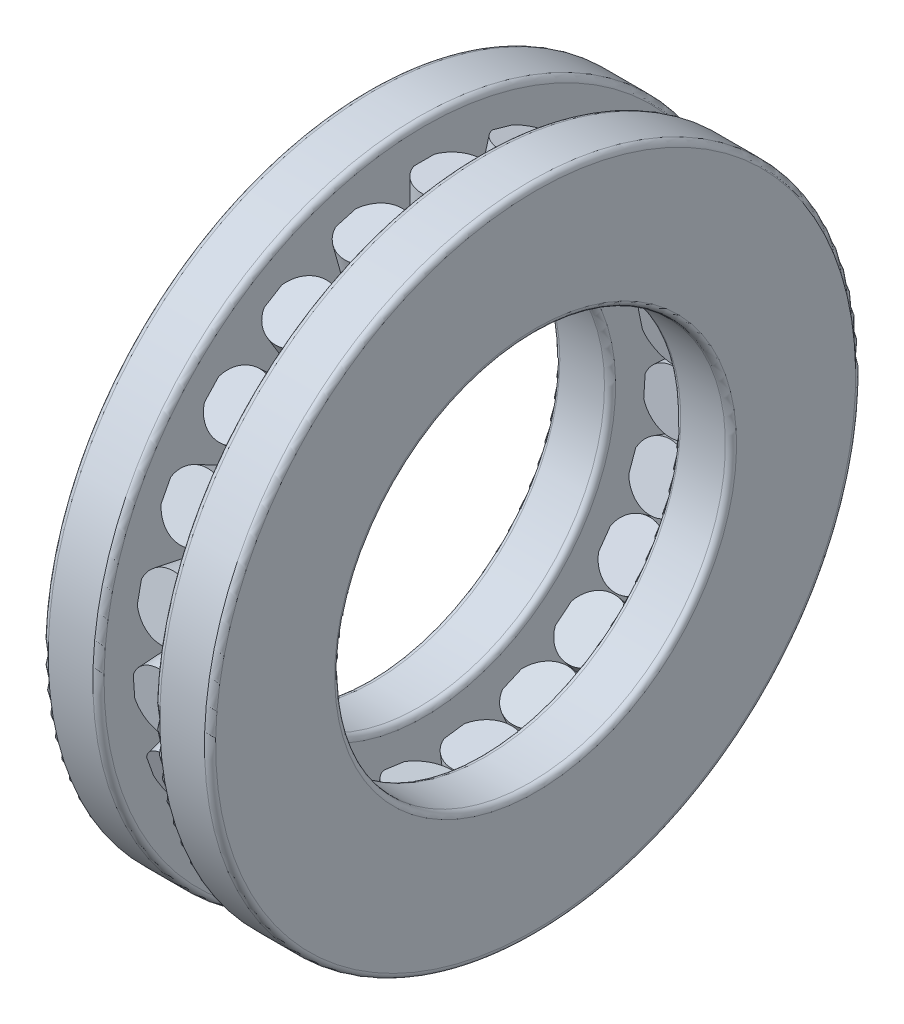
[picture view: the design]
ISO-10303-21;
HEADER;
FILE_DESCRIPTION(('STEP AP214'),'2;1');
FILE_NAME('part.step','',(''),(''),'','','');
FILE_SCHEMA(('AUTOMOTIVE_DESIGN { 1 0 10303 214 1 1 1 1 }'));
ENDSEC;
DATA;
#1=APPLICATION_CONTEXT('core data for automotive mechanical design processes');
#2=APPLICATION_PROTOCOL_DEFINITION('international standard','automotive_design',2000,#1);
#3=PRODUCT_CONTEXT('',#1,'mechanical');
#4=PRODUCT('Part','Part','',(#3));
#5=PRODUCT_RELATED_PRODUCT_CATEGORY('part','',(#4));
#6=PRODUCT_DEFINITION_FORMATION('','',#4);
#7=PRODUCT_DEFINITION_CONTEXT('part definition',#1,'design');
#8=PRODUCT_DEFINITION('design','',#6,#7);
#9=PRODUCT_DEFINITION_SHAPE('','',#8);
#10=(LENGTH_UNIT() NAMED_UNIT(*) SI_UNIT(.MILLI.,.METRE.));
#11=(NAMED_UNIT(*) PLANE_ANGLE_UNIT() SI_UNIT($,.RADIAN.));
#12=(NAMED_UNIT(*) SI_UNIT($,.STERADIAN.) SOLID_ANGLE_UNIT());
#13=UNCERTAINTY_MEASURE_WITH_UNIT(LENGTH_MEASURE(1.E-05),#10,'distance_accuracy_value','');
#14=(GEOMETRIC_REPRESENTATION_CONTEXT(3) GLOBAL_UNCERTAINTY_ASSIGNED_CONTEXT((#13)) GLOBAL_UNIT_ASSIGNED_CONTEXT((#10,
#11,#12)) REPRESENTATION_CONTEXT('',''));
#15=CARTESIAN_POINT('',(0.,0.,0.));
#16=DIRECTION('',(0.,0.,1.));
#17=DIRECTION('',(1.,0.,0.));
#18=AXIS2_PLACEMENT_3D('',#15,#16,#17);
#19=CARTESIAN_POINT('',(0.,-17.5,0.));
#20=DIRECTION('',(1.,0.,0.));
#21=DIRECTION('',(0.,1.,0.));
#22=AXIS2_PLACEMENT_3D('',#19,#20,#21);
#23=PLANE('',#22);
#24=CARTESIAN_POINT('',(0.,0.,0.));
#25=DIRECTION('',(1.,0.,0.));
#26=DIRECTION('',(0.,1.,0.));
#27=AXIS2_PLACEMENT_3D('',#24,#25,#26);
#28=CIRCLE('',#27,10.3);
#29=CARTESIAN_POINT('',(0.,10.3,0.));
#30=VERTEX_POINT('',#29);
#31=EDGE_CURVE('E644',#30,#30,#28,.F.);
#32=ORIENTED_EDGE('',*,*,#31,.T.);
#33=EDGE_LOOP('',(#32));
#34=FACE_BOUND('',#33,.T.);
#35=CARTESIAN_POINT('',(0.,0.,0.));
#36=DIRECTION('',(1.,0.,0.));
#37=DIRECTION('',(0.,1.,0.));
#38=AXIS2_PLACEMENT_3D('',#35,#36,#37);
#39=CIRCLE('',#38,17.2);
#40=CARTESIAN_POINT('',(0.,17.2,0.));
#41=VERTEX_POINT('',#40);
#42=EDGE_CURVE('E641',#41,#41,#39,.T.);
#43=ORIENTED_EDGE('',*,*,#42,.T.);
#44=EDGE_LOOP('',(#43));
#45=FACE_BOUND('',#44,.T.);
#46=DIRECTION('',(0.,1.,0.));
#47=VECTOR('',#46,1.);
#48=CARTESIAN_POINT('',(0.,16.5461402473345,0.556776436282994));
#49=LINE('',#48,#47);
#50=CARTESIAN_POINT('',(0.,11.875,0.556776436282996));
#51=VERTEX_POINT('',#50);
#52=CARTESIAN_POINT('',(0.,15.625,0.556776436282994));
#53=VERTEX_POINT('',#52);
#54=EDGE_CURVE('E1057',#51,#53,#49,.T.);
#55=ORIENTED_EDGE('',*,*,#54,.T.);
#56=DIRECTION('',(0.,0.,-1.));
#57=VECTOR('',#56,1.);
#58=CARTESIAN_POINT('',(0.,15.625,0.));
#59=LINE('',#58,#57);
#60=CARTESIAN_POINT('',(0.,15.625,-0.556776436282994));
#61=VERTEX_POINT('',#60);
#62=EDGE_CURVE('E1076',#53,#61,#59,.T.);
#63=ORIENTED_EDGE('',*,*,#62,.T.);
#64=DIRECTION('',(0.,1.,0.));
#65=VECTOR('',#64,1.);
#66=CARTESIAN_POINT('',(0.,16.5461402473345,-0.556776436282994));
#67=LINE('',#66,#65);
#68=CARTESIAN_POINT('',(0.,11.875,-0.556776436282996));
#69=VERTEX_POINT('',#68);
#70=EDGE_CURVE('E1073',#61,#69,#67,.F.);
#71=ORIENTED_EDGE('',*,*,#70,.T.);
#72=DIRECTION('',(0.,0.,1.));
#73=VECTOR('',#72,1.);
#74=CARTESIAN_POINT('',(0.,11.875,0.));
#75=LINE('',#74,#73);
#76=EDGE_CURVE('E1070',#69,#51,#75,.T.);
#77=ORIENTED_EDGE('',*,*,#76,.T.);
#78=EDGE_LOOP('',(#55,#63,#71,#77));
#79=FACE_BOUND('',#78,.T.);
#80=DIRECTION('',(0.,0.962917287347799,0.269796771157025));
#81=VECTOR('',#80,1.);
#82=CARTESIAN_POINT('',(0.,15.7823479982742,5.00022486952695));
#83=LINE('',#82,#81);
#84=CARTESIAN_POINT('',(0.,11.2844263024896,3.73996631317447));
#85=VERTEX_POINT('',#84);
#86=CARTESIAN_POINT('',(0.,14.8953661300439,4.75170420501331));
#87=VERTEX_POINT('',#86);
#88=EDGE_CURVE('E1750',#85,#87,#83,.T.);
#89=ORIENTED_EDGE('',*,*,#88,.T.);
#90=DIRECTION('',(0.,0.269796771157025,-0.962917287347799));
#91=VECTOR('',#90,1.);
#92=CARTESIAN_POINT('',(0.,13.7717524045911,8.76193411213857));
#93=LINE('',#92,#91);
#94=CARTESIAN_POINT('',(0.,15.1957990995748,3.67944489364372));
#95=VERTEX_POINT('',#94);
#96=EDGE_CURVE('E1756',#87,#95,#93,.T.);
#97=ORIENTED_EDGE('',*,*,#96,.T.);
#98=DIRECTION('',(0.,0.962917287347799,0.269796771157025));
#99=VECTOR('',#98,1.);
#100=CARTESIAN_POINT('',(0.,16.0827809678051,3.92796555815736));
#101=LINE('',#100,#99);
#102=CARTESIAN_POINT('',(0.,11.5848592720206,2.66770700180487));
#103=VERTEX_POINT('',#102);
#104=EDGE_CURVE('E1753',#95,#103,#101,.F.);
#105=ORIENTED_EDGE('',*,*,#104,.T.);
#106=DIRECTION('',(0.,-0.269796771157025,0.962917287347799));
#107=VECTOR('',#106,1.);
#108=CARTESIAN_POINT('',(0.,10.1608125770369,7.75019622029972));
#109=LINE('',#108,#107);
#110=EDGE_CURVE('E1747',#103,#85,#109,.T.);
#111=ORIENTED_EDGE('',*,*,#110,.T.);
#112=EDGE_LOOP('',(#89,#97,#105,#111));
#113=FACE_BOUND('',#112,.T.);
#114=DIRECTION('',(0.,0.854419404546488,0.519583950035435));
#115=VECTOR('',#114,1.);
#116=CARTESIAN_POINT('',(0.,13.8480511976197,9.0728294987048));
#117=LINE('',#116,#115);
#118=CARTESIAN_POINT('',(0.,9.85693832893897,6.64577999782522));
#119=VERTEX_POINT('',#118);
#120=CARTESIAN_POINT('',(0.,13.0610110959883,8.59421981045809));
#121=VERTEX_POINT('',#120);
#122=EDGE_CURVE('E1730',#119,#121,#117,.T.);
#123=ORIENTED_EDGE('',*,*,#122,.T.);
#124=DIRECTION('',(0.,0.519583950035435,-0.854419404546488));
#125=VECTOR('',#124,1.);
#126=CARTESIAN_POINT('',(0.,8.62587227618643,15.8874948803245));
#127=LINE('',#126,#125);
#128=CARTESIAN_POINT('',(0.,13.6395952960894,7.64277862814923));
#129=VERTEX_POINT('',#128);
#130=EDGE_CURVE('E1736',#121,#129,#127,.T.);
#131=ORIENTED_EDGE('',*,*,#130,.T.);
#132=DIRECTION('',(0.,0.854419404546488,0.519583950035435));
#133=VECTOR('',#132,1.);
#134=CARTESIAN_POINT('',(0.,14.4266353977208,8.12138831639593));
#135=LINE('',#134,#133);
#136=CARTESIAN_POINT('',(0.,10.4355225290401,5.69433881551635));
#137=VERTEX_POINT('',#136);
#138=EDGE_CURVE('E1733',#129,#137,#135,.F.);
#139=ORIENTED_EDGE('',*,*,#138,.T.);
#140=DIRECTION('',(0.,-0.519583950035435,0.854419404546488));
#141=VECTOR('',#140,1.);
#142=CARTESIAN_POINT('',(0.,5.42179950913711,13.9390550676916));
#143=LINE('',#142,#141);
#144=EDGE_CURVE('E1727',#137,#119,#143,.T.);
#145=ORIENTED_EDGE('',*,*,#144,.T.);
#146=EDGE_LOOP('',(#123,#131,#139,#145));
#147=FACE_BOUND('',#146,.T.);
#148=DIRECTION('',(0.,0.682553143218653,0.730835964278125));
#149=VECTOR('',#148,1.);
#150=CARTESIAN_POINT('',(0.,10.8867077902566,12.4725438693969));
#151=LINE('',#150,#149);
#152=CARTESIAN_POINT('',(0.,7.69840633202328,9.05870658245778));
#153=VERTEX_POINT('',#152);
#154=CARTESIAN_POINT('',(0.,10.2579806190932,11.7993414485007));
#155=VERTEX_POINT('',#154);
#156=EDGE_CURVE('E1710',#153,#155,#151,.T.);
#157=ORIENTED_EDGE('',*,*,#156,.T.);
#158=DIRECTION('',(0.,0.730835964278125,-0.682553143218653));
#159=VECTOR('',#158,1.);
#160=CARTESIAN_POINT('',(0.,1.31777174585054,20.1489136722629));
#161=LINE('',#160,#159);
#162=CARTESIAN_POINT('',(0.,11.0718051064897,11.0392824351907));
#163=VERTEX_POINT('',#162);
#164=EDGE_CURVE('E1716',#155,#163,#161,.T.);
#165=ORIENTED_EDGE('',*,*,#164,.T.);
#166=DIRECTION('',(0.,0.682553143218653,0.730835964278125));
#167=VECTOR('',#166,1.);
#168=CARTESIAN_POINT('',(0.,11.7005322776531,11.7124848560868));
#169=LINE('',#168,#167);
#170=CARTESIAN_POINT('',(0.,8.51223081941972,8.2986475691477));
#171=VERTEX_POINT('',#170);
#172=EDGE_CURVE('E1713',#163,#171,#169,.F.);
#173=ORIENTED_EDGE('',*,*,#172,.T.);
#174=DIRECTION('',(0.,-0.730835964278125,0.682553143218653));
#175=VECTOR('',#174,1.);
#176=CARTESIAN_POINT('',(0.,-1.2418025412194,17.40827880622));
#177=LINE('',#176,#175);
#178=EDGE_CURVE('E1707',#171,#153,#177,.T.);
#179=ORIENTED_EDGE('',*,*,#178,.T.);
#180=EDGE_LOOP('',(#157,#165,#173,#179));
#181=FACE_BOUND('',#180,.T.);
#182=DIRECTION('',(0.,0.46006503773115,0.887885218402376));
#183=VECTOR('',#182,1.);
#184=CARTESIAN_POINT('',(0.,7.11794706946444,14.9472267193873));
#185=LINE('',#184,#183);
#186=CARTESIAN_POINT('',(0.,4.96891875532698,10.7997903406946));
#187=VERTEX_POINT('',#186);
#188=CARTESIAN_POINT('',(0.,6.69416264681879,14.1293599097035));
#189=VERTEX_POINT('',#188);
#190=EDGE_CURVE('E1690',#187,#189,#185,.T.);
#191=ORIENTED_EDGE('',*,*,#190,.T.);
#192=DIRECTION('',(0.,0.887885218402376,-0.46006503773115));
#193=VECTOR('',#192,1.);
#194=CARTESIAN_POINT('',(0.,-6.60743660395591,21.0216931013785));
#195=LINE('',#194,#193);
#196=CARTESIAN_POINT('',(0.,7.68286978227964,13.6170531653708));
#197=VERTEX_POINT('',#196);
#198=EDGE_CURVE('E1696',#189,#197,#195,.T.);
#199=ORIENTED_EDGE('',*,*,#198,.T.);
#200=DIRECTION('',(0.,0.46006503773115,0.887885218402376));
#201=VECTOR('',#200,1.);
#202=CARTESIAN_POINT('',(0.,8.10665420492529,14.4349199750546));
#203=LINE('',#202,#201);
#204=CARTESIAN_POINT('',(0.,5.95762589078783,10.2874835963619));
#205=VERTEX_POINT('',#204);
#206=EDGE_CURVE('E1693',#197,#205,#203,.F.);
#207=ORIENTED_EDGE('',*,*,#206,.T.);
#208=DIRECTION('',(0.,-0.887885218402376,0.46006503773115));
#209=VECTOR('',#208,1.);
#210=CARTESIAN_POINT('',(0.,-8.33268049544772,17.6921235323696));
#211=LINE('',#210,#209);
#212=EDGE_CURVE('E1687',#205,#187,#211,.T.);
#213=ORIENTED_EDGE('',*,*,#212,.T.);
#214=EDGE_LOOP('',(#191,#199,#207,#213));
#215=FACE_BOUND('',#214,.T.);
#216=DIRECTION('',(0.,0.203456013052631,0.979084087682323));
#217=VECTOR('',#216,1.);
#218=CARTESIAN_POINT('',(0.,2.82128077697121,16.3133421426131));
#219=LINE('',#218,#217);
#220=CARTESIAN_POINT('',(0.,1.87090920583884,11.7399030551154));
#221=VERTEX_POINT('',#220);
#222=CARTESIAN_POINT('',(0.,2.63386925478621,15.4114683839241));
#223=VERTEX_POINT('',#222);
#224=EDGE_CURVE('E1670',#221,#223,#219,.T.);
#225=ORIENTED_EDGE('',*,*,#224,.T.);
#226=DIRECTION('',(0.,0.979084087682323,-0.203456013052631));
#227=VECTOR('',#226,1.);
#228=CARTESIAN_POINT('',(0.,-13.5965986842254,18.7841984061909));
#229=LINE('',#228,#227);
#230=CARTESIAN_POINT('',(0.,3.72413115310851,15.1849093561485));
#231=VERTEX_POINT('',#230);
#232=EDGE_CURVE('E1676',#223,#231,#229,.T.);
#233=ORIENTED_EDGE('',*,*,#232,.T.);
#234=DIRECTION('',(0.,0.203456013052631,0.979084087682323));
#235=VECTOR('',#234,1.);
#236=CARTESIAN_POINT('',(0.,3.91154267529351,16.0867831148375));
#237=LINE('',#236,#235);
#238=CARTESIAN_POINT('',(0.,2.96117110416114,11.5133440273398));
#239=VERTEX_POINT('',#238);
#240=EDGE_CURVE('E1673',#231,#239,#237,.F.);
#241=ORIENTED_EDGE('',*,*,#240,.T.);
#242=DIRECTION('',(0.,-0.979084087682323,0.203456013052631));
#243=VECTOR('',#242,1.);
#244=CARTESIAN_POINT('',(0.,-14.3595587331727,15.1126330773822));
#245=LINE('',#244,#243);
#246=EDGE_CURVE('E1667',#239,#221,#245,.T.);
#247=ORIENTED_EDGE('',*,*,#246,.T.);
#248=EDGE_LOOP('',(#225,#233,#241,#247));
#249=FACE_BOUND('',#248,.T.);
#250=DIRECTION('',(0.,-0.0682424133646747,0.997668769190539));
#251=VECTOR('',#250,1.);
#252=CARTESIAN_POINT('',(0.,-1.68462700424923,16.4695716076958));
#253=LINE('',#252,#251);
#254=CARTESIAN_POINT('',(0.,-1.36585712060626,11.8093208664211));
#255=VERTEX_POINT('',#254);
#256=CARTESIAN_POINT('',(0.,-1.62176617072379,15.5505787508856));
#257=VERTEX_POINT('',#256);
#258=EDGE_CURVE('E1650',#255,#257,#253,.T.);
#259=ORIENTED_EDGE('',*,*,#258,.T.);
#260=DIRECTION('',(0.,0.997668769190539,0.0682424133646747));
#261=VECTOR('',#260,1.);
#262=CARTESIAN_POINT('',(0.,-18.4847897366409,14.3971163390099));
#263=LINE('',#262,#261);
#264=CARTESIAN_POINT('',(0.,-0.510809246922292,15.6265702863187));
#265=VERTEX_POINT('',#264);
#266=EDGE_CURVE('E1656',#257,#265,#263,.T.);
#267=ORIENTED_EDGE('',*,*,#266,.T.);
#268=DIRECTION('',(0.,-0.0682424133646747,0.997668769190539));
#269=VECTOR('',#268,1.);
#270=CARTESIAN_POINT('',(0.,-0.573670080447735,16.5455631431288));
#271=LINE('',#270,#269);
#272=CARTESIAN_POINT('',(0.,-0.254900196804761,11.8853124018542));
#273=VERTEX_POINT('',#272);
#274=EDGE_CURVE('E1653',#265,#273,#271,.F.);
#275=ORIENTED_EDGE('',*,*,#274,.T.);
#276=DIRECTION('',(0.,-0.997668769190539,-0.0682424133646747));
#277=VECTOR('',#276,1.);
#278=CARTESIAN_POINT('',(0.,-18.2288806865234,10.6558584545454));
#279=LINE('',#278,#277);
#280=EDGE_CURVE('E1647',#273,#255,#279,.T.);
#281=ORIENTED_EDGE('',*,*,#280,.T.);
#282=EDGE_LOOP('',(#259,#267,#275,#281));
#283=FACE_BOUND('',#282,.T.);
#284=DIRECTION('',(0.,-0.33487961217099,0.942260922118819));
#285=VECTOR('',#284,1.);
#286=CARTESIAN_POINT('',(0.,-6.06559370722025,15.4043282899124));
#287=LINE('',#286,#285);
#288=CARTESIAN_POINT('',(0.,-4.50132407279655,11.0028953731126));
#289=VERTEX_POINT('',#288);
#290=CARTESIAN_POINT('',(0.,-5.75712261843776,14.5363738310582));
#291=VERTEX_POINT('',#290);
#292=EDGE_CURVE('E1630',#289,#291,#287,.T.);
#293=ORIENTED_EDGE('',*,*,#292,.T.);
#294=DIRECTION('',(0.,0.942260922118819,0.33487961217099));
#295=VECTOR('',#294,1.);
#296=CARTESIAN_POINT('',(0.,-20.7699677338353,9.20080739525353));
#297=LINE('',#296,#295);
#298=CARTESIAN_POINT('',(0.,-4.70786526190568,14.9092799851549));
#299=VERTEX_POINT('',#298);
#300=EDGE_CURVE('E1636',#291,#299,#297,.T.);
#301=ORIENTED_EDGE('',*,*,#300,.T.);
#302=DIRECTION('',(0.,-0.33487961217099,0.942260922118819));
#303=VECTOR('',#302,1.);
#304=CARTESIAN_POINT('',(0.,-5.01633635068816,15.7772344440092));
#305=LINE('',#304,#303);
#306=CARTESIAN_POINT('',(0.,-3.45206671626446,11.3758015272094));
#307=VERTEX_POINT('',#306);
#308=EDGE_CURVE('E1633',#299,#307,#305,.F.);
#309=ORIENTED_EDGE('',*,*,#308,.T.);
#310=DIRECTION('',(0.,-0.942260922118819,-0.33487961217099));
#311=VECTOR('',#310,1.);
#312=CARTESIAN_POINT('',(0.,-19.5141691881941,5.66732893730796));
#313=LINE('',#312,#311);
#314=EDGE_CURVE('E1627',#307,#289,#313,.T.);
#315=ORIENTED_EDGE('',*,*,#314,.T.);
#316=EDGE_LOOP('',(#293,#301,#309,#315));
#317=FACE_BOUND('',#316,.T.);
#318=DIRECTION('',(0.,-0.576680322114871,0.816969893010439));
#319=VECTOR('',#318,1.);
#320=CARTESIAN_POINT('',(0.,-9.99670307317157,13.196616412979));
#321=LINE('',#320,#319);
#322=CARTESIAN_POINT('',(0.,-7.30294841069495,9.38043546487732));
#323=VERTEX_POINT('',#322);
#324=CARTESIAN_POINT('',(0.,-9.46549961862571,12.4440725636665));
#325=VERTEX_POINT('',#324);
#326=EDGE_CURVE('E1610',#323,#325,#321,.T.);
#327=ORIENTED_EDGE('',*,*,#326,.T.);
#328=DIRECTION('',(0.,0.816969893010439,0.576680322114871));
#329=VECTOR('',#328,1.);
#330=CARTESIAN_POINT('',(0.,-20.6908266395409,4.5203715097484));
#331=LINE('',#330,#329);
#332=CARTESIAN_POINT('',(0.,-8.55576044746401,13.0862365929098));
#333=VERTEX_POINT('',#332);
#334=EDGE_CURVE('E1616',#325,#333,#331,.T.);
#335=ORIENTED_EDGE('',*,*,#334,.T.);
#336=DIRECTION('',(0.,-0.576680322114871,0.816969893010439));
#337=VECTOR('',#336,1.);
#338=CARTESIAN_POINT('',(0.,-9.08696390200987,13.8387804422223));
#339=LINE('',#338,#337);
#340=CARTESIAN_POINT('',(0.,-6.39320923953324,10.0225994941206));
#341=VERTEX_POINT('',#340);
#342=EDGE_CURVE('E1613',#333,#341,#339,.F.);
#343=ORIENTED_EDGE('',*,*,#342,.T.);
#344=DIRECTION('',(0.,-0.816969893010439,-0.576680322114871));
#345=VECTOR('',#344,1.);
#346=CARTESIAN_POINT('',(0.,-18.5282754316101,1.45673441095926));
#347=LINE('',#346,#345);
#348=EDGE_CURVE('E1607',#341,#323,#347,.T.);
#349=ORIENTED_EDGE('',*,*,#348,.T.);
#350=EDGE_LOOP('',(#327,#335,#343,#349));
#351=FACE_BOUND('',#350,.T.);
#352=DIRECTION('',(0.,-0.775711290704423,0.631087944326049));
#353=VECTOR('',#352,1.);
#354=CARTESIAN_POINT('',(0.,-13.1864027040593,10.010171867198));
#355=LINE('',#354,#353);
#356=CARTESIAN_POINT('',(0.,-9.56294647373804,7.06227157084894));
#357=VERTEX_POINT('',#356);
#358=CARTESIAN_POINT('',(0.,-12.4718638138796,9.42885136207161));
#359=VERTEX_POINT('',#358);
#360=EDGE_CURVE('E1590',#357,#359,#355,.T.);
#361=ORIENTED_EDGE('',*,*,#360,.T.);
#362=DIRECTION('',(0.,0.631087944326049,0.775711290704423));
#363=VECTOR('',#362,1.);
#364=CARTESIAN_POINT('',(0.,-19.090248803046,1.2937633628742));
#365=LINE('',#364,#363);
#366=CARTESIAN_POINT('',(0.,-11.7691140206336,10.2926468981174));
#367=VERTEX_POINT('',#366);
#368=EDGE_CURVE('E1596',#359,#367,#365,.T.);
#369=ORIENTED_EDGE('',*,*,#368,.T.);
#370=DIRECTION('',(0.,-0.775711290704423,0.631087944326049));
#371=VECTOR('',#370,1.);
#372=CARTESIAN_POINT('',(0.,-12.4836529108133,10.8739674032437));
#373=LINE('',#372,#371);
#374=CARTESIAN_POINT('',(0.,-8.86019668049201,7.92606710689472));
#375=VERTEX_POINT('',#374);
#376=EDGE_CURVE('E1593',#367,#375,#373,.F.);
#377=ORIENTED_EDGE('',*,*,#376,.T.);
#378=DIRECTION('',(0.,-0.631087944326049,-0.775711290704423));
#379=VECTOR('',#378,1.);
#380=CARTESIAN_POINT('',(0.,-16.1813314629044,-1.07281642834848));
#381=LINE('',#380,#379);
#382=EDGE_CURVE('E1587',#375,#357,#381,.T.);
#383=ORIENTED_EDGE('',*,*,#382,.T.);
#384=EDGE_LOOP('',(#361,#369,#377,#383));
#385=FACE_BOUND('',#384,.T.);
#386=DIRECTION('',(0.,-0.917211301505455,0.398401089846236));
#387=VECTOR('',#386,1.);
#388=CARTESIAN_POINT('',(0.,-15.3981271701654,6.08131866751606));
#389=LINE('',#388,#387);
#390=CARTESIAN_POINT('',(0.,-11.1137045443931,4.22033130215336));
#391=VERTEX_POINT('',#390);
#392=CARTESIAN_POINT('',(0.,-14.5532469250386,5.71433538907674));
#393=VERTEX_POINT('',#392);
#394=EDGE_CURVE('E1570',#391,#393,#389,.T.);
#395=ORIENTED_EDGE('',*,*,#394,.T.);
#396=DIRECTION('',(0.,0.398401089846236,0.917211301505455));
#397=VECTOR('',#396,1.);
#398=CARTESIAN_POINT('',(0.,-17.1090865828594,-0.169797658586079));
#399=LINE('',#398,#397);
#400=CARTESIAN_POINT('',(0.,-14.1096062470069,6.73569866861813));
#401=VERTEX_POINT('',#400);
#402=EDGE_CURVE('E1576',#393,#401,#399,.T.);
#403=ORIENTED_EDGE('',*,*,#402,.T.);
#404=DIRECTION('',(0.,-0.917211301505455,0.398401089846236));
#405=VECTOR('',#404,1.);
#406=CARTESIAN_POINT('',(0.,-14.9544864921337,7.10268194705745));
#407=LINE('',#406,#405);
#408=CARTESIAN_POINT('',(0.,-10.6700638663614,5.24169458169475));
#409=VERTEX_POINT('',#408);
#410=EDGE_CURVE('E1573',#401,#409,#407,.F.);
#411=ORIENTED_EDGE('',*,*,#410,.T.);
#412=DIRECTION('',(0.,-0.398401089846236,-0.917211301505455));
#413=VECTOR('',#412,1.);
#414=CARTESIAN_POINT('',(0.,-13.669544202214,-1.66380174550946));
#415=LINE('',#414,#413);
#416=EDGE_CURVE('E1567',#409,#391,#415,.T.);
#417=ORIENTED_EDGE('',*,*,#416,.T.);
#418=EDGE_LOOP('',(#395,#403,#411,#417));
#419=FACE_BOUND('',#418,.T.);
#420=DIRECTION('',(0.,-0.990685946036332,0.13616664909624));
#421=VECTOR('',#420,1.);
#422=CARTESIAN_POINT('',(0.,-16.4678429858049,1.70144188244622));
#423=LINE('',#422,#421);
#424=CARTESIAN_POINT('',(0.,-11.8402099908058,1.06538836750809));
#425=VERTEX_POINT('',#424);
#426=CARTESIAN_POINT('',(0.,-15.5552822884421,1.57601330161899));
#427=VERTEX_POINT('',#426);
#428=EDGE_CURVE('E1550',#425,#427,#423,.T.);
#429=ORIENTED_EDGE('',*,*,#428,.T.);
#430=DIRECTION('',(0.,0.13616664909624,0.990685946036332));
#431=VECTOR('',#430,1.);
#432=CARTESIAN_POINT('',(0.,-15.8039416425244,-0.233117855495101));
#433=LINE('',#432,#431);
#434=CARTESIAN_POINT('',(0.,-15.4036535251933,2.67919448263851));
#435=VERTEX_POINT('',#434);
#436=EDGE_CURVE('E1556',#427,#435,#433,.T.);
#437=ORIENTED_EDGE('',*,*,#436,.T.);
#438=DIRECTION('',(0.,-0.990685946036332,0.13616664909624));
#439=VECTOR('',#438,1.);
#440=CARTESIAN_POINT('',(0.,-16.316214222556,2.80462306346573));
#441=LINE('',#440,#439);
#442=CARTESIAN_POINT('',(0.,-11.688581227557,2.16856954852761));
#443=VERTEX_POINT('',#442);
#444=EDGE_CURVE('E1553',#435,#443,#441,.F.);
#445=ORIENTED_EDGE('',*,*,#444,.T.);
#446=DIRECTION('',(0.,-0.13616664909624,-0.990685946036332));
#447=VECTOR('',#446,1.);
#448=CARTESIAN_POINT('',(0.,-12.0888693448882,-0.743742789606));
#449=LINE('',#448,#447);
#450=EDGE_CURVE('E1547',#443,#425,#449,.T.);
#451=ORIENTED_EDGE('',*,*,#450,.T.);
#452=EDGE_LOOP('',(#429,#437,#445,#451));
#453=FACE_BOUND('',#452,.T.);
#454=DIRECTION('',(0.,-0.99068594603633,-0.136166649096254));
#455=VECTOR('',#454,1.);
#456=CARTESIAN_POINT('',(0.,-16.316214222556,-2.80462306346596));
#457=LINE('',#456,#455);
#458=CARTESIAN_POINT('',(0.,-11.688581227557,-2.16856954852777));
#459=VERTEX_POINT('',#458);
#460=CARTESIAN_POINT('',(0.,-15.4036535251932,-2.67919448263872));
#461=VERTEX_POINT('',#460);
#462=EDGE_CURVE('E1530',#459,#461,#457,.T.);
#463=ORIENTED_EDGE('',*,*,#462,.T.);
#464=DIRECTION('',(0.,-0.136166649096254,0.99068594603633));
#465=VECTOR('',#464,1.);
#466=CARTESIAN_POINT('',(0.,-15.8039416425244,0.23311785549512));
#467=LINE('',#466,#465);
#468=CARTESIAN_POINT('',(0.,-15.5552822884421,-1.57601330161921));
#469=VERTEX_POINT('',#468);
#470=EDGE_CURVE('E1536',#461,#469,#467,.T.);
#471=ORIENTED_EDGE('',*,*,#470,.T.);
#472=DIRECTION('',(0.,-0.99068594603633,-0.136166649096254));
#473=VECTOR('',#472,1.);
#474=CARTESIAN_POINT('',(0.,-16.4678429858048,-1.70144188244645));
#475=LINE('',#474,#473);
#476=CARTESIAN_POINT('',(0.,-11.8402099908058,-1.06538836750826));
#477=VERTEX_POINT('',#476);
#478=EDGE_CURVE('E1533',#469,#477,#475,.F.);
#479=ORIENTED_EDGE('',*,*,#478,.T.);
#480=DIRECTION('',(0.,0.136166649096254,-0.99068594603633));
#481=VECTOR('',#480,1.);
#482=CARTESIAN_POINT('',(0.,-12.0888693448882,0.743742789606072));
#483=LINE('',#482,#481);
#484=EDGE_CURVE('E1527',#477,#459,#483,.T.);
#485=ORIENTED_EDGE('',*,*,#484,.T.);
#486=EDGE_LOOP('',(#463,#471,#479,#485));
#487=FACE_BOUND('',#486,.T.);
#488=DIRECTION('',(0.,-0.91721130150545,-0.398401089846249));
#489=VECTOR('',#488,1.);
#490=CARTESIAN_POINT('',(0.,-14.9544864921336,-7.10268194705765));
#491=LINE('',#490,#489);
#492=CARTESIAN_POINT('',(0.,-10.6700638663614,-5.24169458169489));
#493=VERTEX_POINT('',#492);
#494=CARTESIAN_POINT('',(0.,-14.1096062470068,-6.73569866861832));
#495=VERTEX_POINT('',#494);
#496=EDGE_CURVE('E1510',#493,#495,#491,.T.);
#497=ORIENTED_EDGE('',*,*,#496,.T.);
#498=DIRECTION('',(0.,-0.398401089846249,0.91721130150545));
#499=VECTOR('',#498,1.);
#500=CARTESIAN_POINT('',(0.,-17.1090865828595,0.169797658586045));
#501=LINE('',#500,#499);
#502=CARTESIAN_POINT('',(0.,-14.5532469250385,-5.71433538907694));
#503=VERTEX_POINT('',#502);
#504=EDGE_CURVE('E1516',#495,#503,#501,.T.);
#505=ORIENTED_EDGE('',*,*,#504,.T.);
#506=DIRECTION('',(0.,-0.91721130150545,-0.398401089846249));
#507=VECTOR('',#506,1.);
#508=CARTESIAN_POINT('',(0.,-15.3981271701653,-6.08131866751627));
#509=LINE('',#508,#507);
#510=CARTESIAN_POINT('',(0.,-11.1137045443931,-4.22033130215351));
#511=VERTEX_POINT('',#510);
#512=EDGE_CURVE('E1513',#503,#511,#509,.F.);
#513=ORIENTED_EDGE('',*,*,#512,.T.);
#514=DIRECTION('',(0.,0.398401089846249,-0.91721130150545));
#515=VECTOR('',#514,1.);
#516=CARTESIAN_POINT('',(0.,-13.6695442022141,1.66380174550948));
#517=LINE('',#516,#515);
#518=EDGE_CURVE('E1507',#511,#493,#517,.T.);
#519=ORIENTED_EDGE('',*,*,#518,.T.);
#520=EDGE_LOOP('',(#497,#505,#513,#519));
#521=FACE_BOUND('',#520,.T.);
#522=DIRECTION('',(0.,-0.775711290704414,-0.631087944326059));
#523=VECTOR('',#522,1.);
#524=CARTESIAN_POINT('',(0.,-12.4836529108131,-10.8739674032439));
#525=LINE('',#524,#523);
#526=CARTESIAN_POINT('',(0.,-8.8601966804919,-7.92606710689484));
#527=VERTEX_POINT('',#526);
#528=CARTESIAN_POINT('',(0.,-11.7691140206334,-10.2926468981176));
#529=VERTEX_POINT('',#528);
#530=EDGE_CURVE('E1490',#527,#529,#525,.T.);
#531=ORIENTED_EDGE('',*,*,#530,.T.);
#532=DIRECTION('',(0.,-0.631087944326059,0.775711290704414));
#533=VECTOR('',#532,1.);
#534=CARTESIAN_POINT('',(0.,-19.0902488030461,-1.29376336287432));
#535=LINE('',#534,#533);
#536=CARTESIAN_POINT('',(0.,-12.4718638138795,-9.42885136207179));
#537=VERTEX_POINT('',#536);
#538=EDGE_CURVE('E1496',#529,#537,#535,.T.);
#539=ORIENTED_EDGE('',*,*,#538,.T.);
#540=DIRECTION('',(0.,-0.775711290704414,-0.631087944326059));
#541=VECTOR('',#540,1.);
#542=CARTESIAN_POINT('',(0.,-13.1864027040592,-10.0101718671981));
#543=LINE('',#542,#541);
#544=CARTESIAN_POINT('',(0.,-9.56294647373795,-7.06227157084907));
#545=VERTEX_POINT('',#544);
#546=EDGE_CURVE('E1493',#537,#545,#543,.F.);
#547=ORIENTED_EDGE('',*,*,#546,.T.);
#548=DIRECTION('',(0.,0.631087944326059,-0.775711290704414));
#549=VECTOR('',#548,1.);
#550=CARTESIAN_POINT('',(0.,-16.1813314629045,1.0728164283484));
#551=LINE('',#550,#549);
#552=EDGE_CURVE('E1487',#545,#527,#551,.T.);
#553=ORIENTED_EDGE('',*,*,#552,.T.);
#554=EDGE_LOOP('',(#531,#539,#547,#553));
#555=FACE_BOUND('',#554,.T.);
#556=DIRECTION('',(0.,-0.57668032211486,-0.816969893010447));
#557=VECTOR('',#556,1.);
#558=CARTESIAN_POINT('',(0.,-9.08696390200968,-13.8387804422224));
#559=LINE('',#558,#557);
#560=CARTESIAN_POINT('',(0.,-6.39320923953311,-10.0225994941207));
#561=VERTEX_POINT('',#560);
#562=CARTESIAN_POINT('',(0.,-8.55576044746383,-13.0862365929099));
#563=VERTEX_POINT('',#562);
#564=EDGE_CURVE('E1470',#561,#563,#559,.T.);
#565=ORIENTED_EDGE('',*,*,#564,.T.);
#566=DIRECTION('',(0.,-0.816969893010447,0.57668032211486));
#567=VECTOR('',#566,1.);
#568=CARTESIAN_POINT('',(0.,-20.690826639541,-4.5203715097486));
#569=LINE('',#568,#567);
#570=CARTESIAN_POINT('',(0.,-9.46549961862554,-12.4440725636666));
#571=VERTEX_POINT('',#570);
#572=EDGE_CURVE('E1476',#563,#571,#569,.T.);
#573=ORIENTED_EDGE('',*,*,#572,.T.);
#574=DIRECTION('',(0.,-0.57668032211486,-0.816969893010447));
#575=VECTOR('',#574,1.);
#576=CARTESIAN_POINT('',(0.,-9.99670307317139,-13.1966164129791));
#577=LINE('',#576,#575);
#578=CARTESIAN_POINT('',(0.,-7.30294841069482,-9.38043546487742));
#579=VERTEX_POINT('',#578);
#580=EDGE_CURVE('E1473',#571,#579,#577,.F.);
#581=ORIENTED_EDGE('',*,*,#580,.T.);
#582=DIRECTION('',(0.,0.816969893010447,-0.57668032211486));
#583=VECTOR('',#582,1.);
#584=CARTESIAN_POINT('',(0.,-18.5282754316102,-1.45673441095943));
#585=LINE('',#584,#583);
#586=EDGE_CURVE('E1467',#579,#561,#585,.T.);
#587=ORIENTED_EDGE('',*,*,#586,.T.);
#588=EDGE_LOOP('',(#565,#573,#581,#587));
#589=FACE_BOUND('',#588,.T.);
#590=DIRECTION('',(0.,-0.334879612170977,-0.942260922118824));
#591=VECTOR('',#590,1.);
#592=CARTESIAN_POINT('',(0.,-5.01633635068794,-15.7772344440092));
#593=LINE('',#592,#591);
#594=CARTESIAN_POINT('',(0.,-3.45206671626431,-11.3758015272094));
#595=VERTEX_POINT('',#594);
#596=CARTESIAN_POINT('',(0.,-4.70786526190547,-14.909279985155));
#597=VERTEX_POINT('',#596);
#598=EDGE_CURVE('E1450',#595,#597,#593,.T.);
#599=ORIENTED_EDGE('',*,*,#598,.T.);
#600=DIRECTION('',(0.,-0.942260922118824,0.334879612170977));
#601=VECTOR('',#600,1.);
#602=CARTESIAN_POINT('',(0.,-20.7699677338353,-9.20080739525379));
#603=LINE('',#602,#601);
#604=CARTESIAN_POINT('',(0.,-5.75712261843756,-14.5363738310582));
#605=VERTEX_POINT('',#604);
#606=EDGE_CURVE('E1456',#597,#605,#603,.T.);
#607=ORIENTED_EDGE('',*,*,#606,.T.);
#608=DIRECTION('',(0.,-0.334879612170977,-0.942260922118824));
#609=VECTOR('',#608,1.);
#610=CARTESIAN_POINT('',(0.,-6.06559370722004,-15.4043282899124));
#611=LINE('',#610,#609);
#612=CARTESIAN_POINT('',(0.,-4.5013240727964,-11.0028953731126));
#613=VERTEX_POINT('',#612);
#614=EDGE_CURVE('E1453',#605,#613,#611,.F.);
#615=ORIENTED_EDGE('',*,*,#614,.T.);
#616=DIRECTION('',(0.,0.942260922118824,-0.334879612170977));
#617=VECTOR('',#616,1.);
#618=CARTESIAN_POINT('',(0.,-19.5141691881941,-5.6673289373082));
#619=LINE('',#618,#617);
#620=EDGE_CURVE('E1447',#613,#595,#619,.T.);
#621=ORIENTED_EDGE('',*,*,#620,.T.);
#622=EDGE_LOOP('',(#599,#607,#615,#621));
#623=FACE_BOUND('',#622,.T.);
#624=DIRECTION('',(0.,-0.0682424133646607,-0.99766876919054));
#625=VECTOR('',#624,1.);
#626=CARTESIAN_POINT('',(0.,-0.573670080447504,-16.5455631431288));
#627=LINE('',#626,#625);
#628=CARTESIAN_POINT('',(0.,-0.254900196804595,-11.8853124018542));
#629=VERTEX_POINT('',#628);
#630=CARTESIAN_POINT('',(0.,-0.510809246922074,-15.6265702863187));
#631=VERTEX_POINT('',#630);
#632=EDGE_CURVE('E1430',#629,#631,#627,.T.);
#633=ORIENTED_EDGE('',*,*,#632,.T.);
#634=DIRECTION('',(0.,-0.99766876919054,0.0682424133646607));
#635=VECTOR('',#634,1.);
#636=CARTESIAN_POINT('',(0.,-18.4847897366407,-14.3971163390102));
#637=LINE('',#636,#635);
#638=CARTESIAN_POINT('',(0.,-1.62176617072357,-15.5505787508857));
#639=VERTEX_POINT('',#638);
#640=EDGE_CURVE('E1436',#631,#639,#637,.T.);
#641=ORIENTED_EDGE('',*,*,#640,.T.);
#642=DIRECTION('',(0.,-0.0682424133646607,-0.99766876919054));
#643=VECTOR('',#642,1.);
#644=CARTESIAN_POINT('',(0.,-1.684627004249,-16.4695716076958));
#645=LINE('',#644,#643);
#646=CARTESIAN_POINT('',(0.,-1.3658571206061,-11.8093208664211));
#647=VERTEX_POINT('',#646);
#648=EDGE_CURVE('E1433',#639,#647,#645,.F.);
#649=ORIENTED_EDGE('',*,*,#648,.T.);
#650=DIRECTION('',(0.,0.99766876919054,-0.0682424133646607));
#651=VECTOR('',#650,1.);
#652=CARTESIAN_POINT('',(0.,-18.2288806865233,-10.6558584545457));
#653=LINE('',#652,#651);
#654=EDGE_CURVE('E1427',#647,#629,#653,.T.);
#655=ORIENTED_EDGE('',*,*,#654,.T.);
#656=EDGE_LOOP('',(#633,#641,#649,#655));
#657=FACE_BOUND('',#656,.T.);
#658=DIRECTION('',(0.,0.203456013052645,-0.979084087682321));
#659=VECTOR('',#658,1.);
#660=CARTESIAN_POINT('',(0.,3.91154267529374,-16.0867831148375));
#661=LINE('',#660,#659);
#662=CARTESIAN_POINT('',(0.,2.9611711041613,-11.5133440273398));
#663=VERTEX_POINT('',#662);
#664=CARTESIAN_POINT('',(0.,3.72413115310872,-15.1849093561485));
#665=VERTEX_POINT('',#664);
#666=EDGE_CURVE('E1410',#663,#665,#661,.T.);
#667=ORIENTED_EDGE('',*,*,#666,.T.);
#668=DIRECTION('',(0.,-0.979084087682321,-0.203456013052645));
#669=VECTOR('',#668,1.);
#670=CARTESIAN_POINT('',(0.,-13.5965986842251,-18.7841984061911));
#671=LINE('',#670,#669);
#672=CARTESIAN_POINT('',(0.,2.63386925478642,-15.4114683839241));
#673=VERTEX_POINT('',#672);
#674=EDGE_CURVE('E1416',#665,#673,#671,.T.);
#675=ORIENTED_EDGE('',*,*,#674,.T.);
#676=DIRECTION('',(0.,0.203456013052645,-0.979084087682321));
#677=VECTOR('',#676,1.);
#678=CARTESIAN_POINT('',(0.,2.82128077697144,-16.3133421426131));
#679=LINE('',#678,#677);
#680=CARTESIAN_POINT('',(0.,1.87090920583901,-11.7399030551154));
#681=VERTEX_POINT('',#680);
#682=EDGE_CURVE('E1413',#673,#681,#679,.F.);
#683=ORIENTED_EDGE('',*,*,#682,.T.);
#684=DIRECTION('',(0.,0.979084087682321,0.203456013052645));
#685=VECTOR('',#684,1.);
#686=CARTESIAN_POINT('',(0.,-14.3595587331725,-15.1126330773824));
#687=LINE('',#686,#685);
#688=EDGE_CURVE('E1407',#681,#663,#687,.T.);
#689=ORIENTED_EDGE('',*,*,#688,.T.);
#690=EDGE_LOOP('',(#667,#675,#683,#689));
#691=FACE_BOUND('',#690,.T.);
#692=DIRECTION('',(0.,0.460065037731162,-0.88788521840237));
#693=VECTOR('',#692,1.);
#694=CARTESIAN_POINT('',(0.,8.10665420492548,-14.4349199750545));
#695=LINE('',#694,#693);
#696=CARTESIAN_POINT('',(0.,5.95762589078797,-10.2874835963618));
#697=VERTEX_POINT('',#696);
#698=CARTESIAN_POINT('',(0.,7.68286978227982,-13.6170531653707));
#699=VERTEX_POINT('',#698);
#700=EDGE_CURVE('E1390',#697,#699,#695,.T.);
#701=ORIENTED_EDGE('',*,*,#700,.T.);
#702=DIRECTION('',(0.,-0.88788521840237,-0.460065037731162));
#703=VECTOR('',#702,1.);
#704=CARTESIAN_POINT('',(0.,-6.60743660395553,-21.0216931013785));
#705=LINE('',#704,#703);
#706=CARTESIAN_POINT('',(0.,6.69416264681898,-14.1293599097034));
#707=VERTEX_POINT('',#706);
#708=EDGE_CURVE('E1396',#699,#707,#705,.T.);
#709=ORIENTED_EDGE('',*,*,#708,.T.);
#710=DIRECTION('',(0.,0.460065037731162,-0.88788521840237));
#711=VECTOR('',#710,1.);
#712=CARTESIAN_POINT('',(0.,7.11794706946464,-14.9472267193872));
#713=LINE('',#712,#711);
#714=CARTESIAN_POINT('',(0.,4.96891875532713,-10.7997903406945));
#715=VERTEX_POINT('',#714);
#716=EDGE_CURVE('E1393',#707,#715,#713,.F.);
#717=ORIENTED_EDGE('',*,*,#716,.T.);
#718=DIRECTION('',(0.,0.88788521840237,0.460065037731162));
#719=VECTOR('',#718,1.);
#720=CARTESIAN_POINT('',(0.,-8.33268049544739,-17.6921235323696));
#721=LINE('',#720,#719);
#722=EDGE_CURVE('E1387',#715,#697,#721,.T.);
#723=ORIENTED_EDGE('',*,*,#722,.T.);
#724=EDGE_LOOP('',(#701,#709,#717,#723));
#725=FACE_BOUND('',#724,.T.);
#726=DIRECTION('',(0.,0.682553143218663,-0.730835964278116));
#727=VECTOR('',#726,1.);
#728=CARTESIAN_POINT('',(0.,11.7005322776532,-11.7124848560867));
#729=LINE('',#728,#727);
#730=CARTESIAN_POINT('',(0.,8.51223081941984,-8.29864756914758));
#731=VERTEX_POINT('',#730);
#732=CARTESIAN_POINT('',(0.,11.0718051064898,-11.0392824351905));
#733=VERTEX_POINT('',#732);
#734=EDGE_CURVE('E1370',#731,#733,#729,.T.);
#735=ORIENTED_EDGE('',*,*,#734,.T.);
#736=DIRECTION('',(0.,-0.730835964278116,-0.682553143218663));
#737=VECTOR('',#736,1.);
#738=CARTESIAN_POINT('',(0.,1.31777174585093,-20.1489136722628));
#739=LINE('',#738,#737);
#740=CARTESIAN_POINT('',(0.,10.2579806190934,-11.7993414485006));
#741=VERTEX_POINT('',#740);
#742=EDGE_CURVE('E1376',#733,#741,#739,.T.);
#743=ORIENTED_EDGE('',*,*,#742,.T.);
#744=DIRECTION('',(0.,0.682553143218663,-0.730835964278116));
#745=VECTOR('',#744,1.);
#746=CARTESIAN_POINT('',(0.,10.8867077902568,-12.4725438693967));
#747=LINE('',#746,#745);
#748=CARTESIAN_POINT('',(0.,7.6984063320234,-9.05870658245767));
#749=VERTEX_POINT('',#748);
#750=EDGE_CURVE('E1373',#741,#749,#747,.F.);
#751=ORIENTED_EDGE('',*,*,#750,.T.);
#752=DIRECTION('',(0.,0.730835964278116,0.682553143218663));
#753=VECTOR('',#752,1.);
#754=CARTESIAN_POINT('',(0.,-1.24180254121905,-17.4082788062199));
#755=LINE('',#754,#753);
#756=EDGE_CURVE('E1367',#749,#731,#755,.T.);
#757=ORIENTED_EDGE('',*,*,#756,.T.);
#758=EDGE_LOOP('',(#735,#743,#751,#757));
#759=FACE_BOUND('',#758,.T.);
#760=DIRECTION('',(0.,0.854419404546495,-0.519583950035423));
#761=VECTOR('',#760,1.);
#762=CARTESIAN_POINT('',(0.,14.426635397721,-8.12138831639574));
#763=LINE('',#762,#761);
#764=CARTESIAN_POINT('',(0.,10.4355225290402,-5.69433881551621));
#765=VERTEX_POINT('',#764);
#766=CARTESIAN_POINT('',(0.,13.6395952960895,-7.64277862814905));
#767=VERTEX_POINT('',#766);
#768=EDGE_CURVE('E1347',#765,#767,#763,.T.);
#769=ORIENTED_EDGE('',*,*,#768,.T.);
#770=DIRECTION('',(0.,-0.519583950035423,-0.854419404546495));
#771=VECTOR('',#770,1.);
#772=CARTESIAN_POINT('',(0.,8.62587227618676,-15.8874948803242));
#773=LINE('',#772,#771);
#774=CARTESIAN_POINT('',(0.,13.0610110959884,-8.59421981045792));
#775=VERTEX_POINT('',#774);
#776=EDGE_CURVE('E1357',#767,#775,#773,.T.);
#777=ORIENTED_EDGE('',*,*,#776,.T.);
#778=DIRECTION('',(0.,0.854419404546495,-0.519583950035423));
#779=VECTOR('',#778,1.);
#780=CARTESIAN_POINT('',(0.,13.8480511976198,-9.07282949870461));
#781=LINE('',#780,#779);
#782=CARTESIAN_POINT('',(0.,9.85693832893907,-6.64577999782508));
#783=VERTEX_POINT('',#782);
#784=EDGE_CURVE('E1343',#775,#783,#781,.F.);
#785=ORIENTED_EDGE('',*,*,#784,.T.);
#786=DIRECTION('',(0.,0.519583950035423,0.854419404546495));
#787=VECTOR('',#786,1.);
#788=CARTESIAN_POINT('',(0.,5.4217995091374,-13.9390550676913));
#789=LINE('',#788,#787);
#790=EDGE_CURVE('E1344',#783,#765,#789,.T.);
#791=ORIENTED_EDGE('',*,*,#790,.T.);
#792=EDGE_LOOP('',(#769,#777,#785,#791));
#793=FACE_BOUND('',#792,.T.);
#794=DIRECTION('',(0.,0.962917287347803,-0.269796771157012));
#795=VECTOR('',#794,1.);
#796=CARTESIAN_POINT('',(0.,16.0827809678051,-3.92796555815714));
#797=LINE('',#796,#795);
#798=CARTESIAN_POINT('',(0.,11.5848592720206,-2.66770700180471));
#799=VERTEX_POINT('',#798);
#800=CARTESIAN_POINT('',(0.,15.1957990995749,-3.67944489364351));
#801=VERTEX_POINT('',#800);
#802=EDGE_CURVE('E613',#799,#801,#797,.T.);
#803=ORIENTED_EDGE('',*,*,#802,.T.);
#804=DIRECTION('',(0.,-0.269796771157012,-0.962917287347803));
#805=VECTOR('',#804,1.);
#806=CARTESIAN_POINT('',(0.,13.7717524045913,-8.76193411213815));
#807=LINE('',#806,#805);
#808=CARTESIAN_POINT('',(0.,14.895366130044,-4.7517042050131));
#809=VERTEX_POINT('',#808);
#810=EDGE_CURVE('E1820',#801,#809,#807,.T.);
#811=ORIENTED_EDGE('',*,*,#810,.T.);
#812=DIRECTION('',(0.,0.962917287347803,-0.269796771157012));
#813=VECTOR('',#812,1.);
#814=CARTESIAN_POINT('',(0.,15.7823479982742,-5.00022486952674));
#815=LINE('',#814,#813);
#816=CARTESIAN_POINT('',(0.,11.2844263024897,-3.73996631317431));
#817=VERTEX_POINT('',#816);
#818=EDGE_CURVE('E1822',#809,#817,#815,.F.);
#819=ORIENTED_EDGE('',*,*,#818,.T.);
#820=DIRECTION('',(0.,0.269796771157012,0.962917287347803));
#821=VECTOR('',#820,1.);
#822=CARTESIAN_POINT('',(0.,10.160812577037,-7.75019622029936));
#823=LINE('',#822,#821);
#824=EDGE_CURVE('E1821',#817,#799,#823,.T.);
#825=ORIENTED_EDGE('',*,*,#824,.T.);
#826=EDGE_LOOP('',(#803,#811,#819,#825));
#827=FACE_BOUND('',#826,.T.);
#828=ADVANCED_FACE('F33',(#34,#45,#79,#113,#147,#181,#215,#249,#283,#317,#351,#385,#419,#453,
#487,#521,#555,#589,#623,#657,#691,#725,#759,#793,#827),#23,.T.);
#829=CARTESIAN_POINT('',(3.,-17.5,0.));
#830=DIRECTION('',(-1.,0.,0.));
#831=DIRECTION('',(0.,-1.,0.));
#832=AXIS2_PLACEMENT_3D('',#829,#830,#831);
#833=PLANE('',#832);
#834=CARTESIAN_POINT('',(3.,0.,0.));
#835=DIRECTION('',(-1.,0.,0.));
#836=DIRECTION('',(0.,-1.,0.));
#837=AXIS2_PLACEMENT_3D('',#834,#835,#836);
#838=CIRCLE('',#837,10.8);
#839=CARTESIAN_POINT('',(3.,-10.8,0.));
#840=VERTEX_POINT('',#839);
#841=EDGE_CURVE('E632',#840,#840,#838,.F.);
#842=ORIENTED_EDGE('',*,*,#841,.T.);
#843=EDGE_LOOP('',(#842));
#844=FACE_BOUND('',#843,.T.);
#845=CARTESIAN_POINT('',(3.,0.,0.));
#846=DIRECTION('',(-1.,0.,0.));
#847=DIRECTION('',(0.,-1.,0.));
#848=AXIS2_PLACEMENT_3D('',#845,#846,#847);
#849=CIRCLE('',#848,17.2);
#850=CARTESIAN_POINT('',(3.,-17.2,0.));
#851=VERTEX_POINT('',#850);
#852=EDGE_CURVE('E629',#851,#851,#849,.T.);
#853=ORIENTED_EDGE('',*,*,#852,.T.);
#854=EDGE_LOOP('',(#853));
#855=FACE_BOUND('',#854,.T.);
#856=DIRECTION('',(0.,0.,-1.));
#857=VECTOR('',#856,1.);
#858=CARTESIAN_POINT('',(3.,15.625,0.));
#859=LINE('',#858,#857);
#860=CARTESIAN_POINT('',(3.,15.625,0.556776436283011));
#861=VERTEX_POINT('',#860);
#862=CARTESIAN_POINT('',(3.,15.625,-0.556776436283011));
#863=VERTEX_POINT('',#862);
#864=EDGE_CURVE('E1066',#861,#863,#859,.T.);
#865=ORIENTED_EDGE('',*,*,#864,.F.);
#866=DIRECTION('',(0.,1.,0.));
#867=VECTOR('',#866,1.);
#868=CARTESIAN_POINT('',(3.,16.5461402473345,0.556776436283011));
#869=LINE('',#868,#867);
#870=CARTESIAN_POINT('',(3.,11.875,0.55677643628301));
#871=VERTEX_POINT('',#870);
#872=EDGE_CURVE('E1054',#871,#861,#869,.T.);
#873=ORIENTED_EDGE('',*,*,#872,.F.);
#874=DIRECTION('',(0.,0.,1.));
#875=VECTOR('',#874,1.);
#876=CARTESIAN_POINT('',(3.,11.875,0.));
#877=LINE('',#876,#875);
#878=CARTESIAN_POINT('',(3.,11.875,-0.55677643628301));
#879=VERTEX_POINT('',#878);
#880=EDGE_CURVE('E1079',#879,#871,#877,.T.);
#881=ORIENTED_EDGE('',*,*,#880,.F.);
#882=DIRECTION('',(0.,1.,0.));
#883=VECTOR('',#882,1.);
#884=CARTESIAN_POINT('',(3.,16.5461402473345,-0.556776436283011));
#885=LINE('',#884,#883);
#886=EDGE_CURVE('E1759',#863,#879,#885,.F.);
#887=ORIENTED_EDGE('',*,*,#886,.F.);
#888=EDGE_LOOP('',(#865,#873,#881,#887));
#889=FACE_BOUND('',#888,.T.);
#890=DIRECTION('',(0.,0.962917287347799,0.269796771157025));
#891=VECTOR('',#890,1.);
#892=CARTESIAN_POINT('',(3.,16.0827809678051,3.92796555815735));
#893=LINE('',#892,#891);
#894=CARTESIAN_POINT('',(3.,11.5848592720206,2.66770700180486));
#895=VERTEX_POINT('',#894);
#896=CARTESIAN_POINT('',(3.,15.1957990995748,3.6794448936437));
#897=VERTEX_POINT('',#896);
#898=EDGE_CURVE('E1084',#895,#897,#893,.T.);
#899=ORIENTED_EDGE('',*,*,#898,.T.);
#900=DIRECTION('',(0.,-0.269796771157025,0.962917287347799));
#901=VECTOR('',#900,1.);
#902=CARTESIAN_POINT('',(3.,13.7717524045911,8.76193411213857));
#903=LINE('',#902,#901);
#904=CARTESIAN_POINT('',(3.,14.8953661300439,4.75170420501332));
#905=VERTEX_POINT('',#904);
#906=EDGE_CURVE('E1090',#897,#905,#903,.T.);
#907=ORIENTED_EDGE('',*,*,#906,.T.);
#908=DIRECTION('',(0.,0.962917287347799,0.269796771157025));
#909=VECTOR('',#908,1.);
#910=CARTESIAN_POINT('',(3.,15.7823479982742,5.00022486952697));
#911=LINE('',#910,#909);
#912=CARTESIAN_POINT('',(3.,11.2844263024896,3.73996631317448));
#913=VERTEX_POINT('',#912);
#914=EDGE_CURVE('E1087',#905,#913,#911,.F.);
#915=ORIENTED_EDGE('',*,*,#914,.T.);
#916=DIRECTION('',(0.,0.269796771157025,-0.962917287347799));
#917=VECTOR('',#916,1.);
#918=CARTESIAN_POINT('',(3.,10.1608125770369,7.75019622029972));
#919=LINE('',#918,#917);
#920=EDGE_CURVE('E1081',#913,#895,#919,.T.);
#921=ORIENTED_EDGE('',*,*,#920,.T.);
#922=EDGE_LOOP('',(#899,#907,#915,#921));
#923=FACE_BOUND('',#922,.T.);
#924=DIRECTION('',(0.,0.854419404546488,0.519583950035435));
#925=VECTOR('',#924,1.);
#926=CARTESIAN_POINT('',(3.,14.4266353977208,8.12138831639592));
#927=LINE('',#926,#925);
#928=CARTESIAN_POINT('',(3.,10.4355225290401,5.69433881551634));
#929=VERTEX_POINT('',#928);
#930=CARTESIAN_POINT('',(3.,13.6395952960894,7.64277862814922));
#931=VERTEX_POINT('',#930);
#932=EDGE_CURVE('E1096',#929,#931,#927,.T.);
#933=ORIENTED_EDGE('',*,*,#932,.T.);
#934=DIRECTION('',(0.,-0.519583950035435,0.854419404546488));
#935=VECTOR('',#934,1.);
#936=CARTESIAN_POINT('',(3.,8.62587227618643,15.8874948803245));
#937=LINE('',#936,#935);
#938=CARTESIAN_POINT('',(3.,13.0610110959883,8.59421981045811));
#939=VERTEX_POINT('',#938);
#940=EDGE_CURVE('E1102',#931,#939,#937,.T.);
#941=ORIENTED_EDGE('',*,*,#940,.T.);
#942=DIRECTION('',(0.,0.854419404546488,0.519583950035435));
#943=VECTOR('',#942,1.);
#944=CARTESIAN_POINT('',(3.,13.8480511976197,9.07282949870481));
#945=LINE('',#944,#943);
#946=CARTESIAN_POINT('',(3.,9.85693832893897,6.64577999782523));
#947=VERTEX_POINT('',#946);
#948=EDGE_CURVE('E1099',#939,#947,#945,.F.);
#949=ORIENTED_EDGE('',*,*,#948,.T.);
#950=DIRECTION('',(0.,0.519583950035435,-0.854419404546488));
#951=VECTOR('',#950,1.);
#952=CARTESIAN_POINT('',(3.,5.42179950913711,13.9390550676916));
#953=LINE('',#952,#951);
#954=EDGE_CURVE('E1093',#947,#929,#953,.T.);
#955=ORIENTED_EDGE('',*,*,#954,.T.);
#956=EDGE_LOOP('',(#933,#941,#949,#955));
#957=FACE_BOUND('',#956,.T.);
#958=DIRECTION('',(0.,0.682553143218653,0.730835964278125));
#959=VECTOR('',#958,1.);
#960=CARTESIAN_POINT('',(3.,11.7005322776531,11.7124848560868));
#961=LINE('',#960,#959);
#962=CARTESIAN_POINT('',(3.,8.51223081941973,8.29864756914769));
#963=VERTEX_POINT('',#962);
#964=CARTESIAN_POINT('',(3.,11.0718051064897,11.0392824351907));
#965=VERTEX_POINT('',#964);
#966=EDGE_CURVE('E1108',#963,#965,#961,.T.);
#967=ORIENTED_EDGE('',*,*,#966,.T.);
#968=DIRECTION('',(0.,-0.730835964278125,0.682553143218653));
#969=VECTOR('',#968,1.);
#970=CARTESIAN_POINT('',(3.,1.31777174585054,20.1489136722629));
#971=LINE('',#970,#969);
#972=CARTESIAN_POINT('',(3.,10.2579806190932,11.7993414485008));
#973=VERTEX_POINT('',#972);
#974=EDGE_CURVE('E1114',#965,#973,#971,.T.);
#975=ORIENTED_EDGE('',*,*,#974,.T.);
#976=DIRECTION('',(0.,0.682553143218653,0.730835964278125));
#977=VECTOR('',#976,1.);
#978=CARTESIAN_POINT('',(3.,10.8867077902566,12.4725438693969));
#979=LINE('',#978,#977);
#980=CARTESIAN_POINT('',(3.,7.69840633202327,9.05870658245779));
#981=VERTEX_POINT('',#980);
#982=EDGE_CURVE('E1111',#973,#981,#979,.F.);
#983=ORIENTED_EDGE('',*,*,#982,.T.);
#984=DIRECTION('',(0.,0.730835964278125,-0.682553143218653));
#985=VECTOR('',#984,1.);
#986=CARTESIAN_POINT('',(3.,-1.2418025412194,17.40827880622));
#987=LINE('',#986,#985);
#988=EDGE_CURVE('E1105',#981,#963,#987,.T.);
#989=ORIENTED_EDGE('',*,*,#988,.T.);
#990=EDGE_LOOP('',(#967,#975,#983,#989));
#991=FACE_BOUND('',#990,.T.);
#992=DIRECTION('',(0.,0.46006503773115,0.887885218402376));
#993=VECTOR('',#992,1.);
#994=CARTESIAN_POINT('',(3.,8.10665420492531,14.4349199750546));
#995=LINE('',#994,#993);
#996=CARTESIAN_POINT('',(3.,5.95762589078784,10.2874835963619));
#997=VERTEX_POINT('',#996);
#998=CARTESIAN_POINT('',(3.,7.68286978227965,13.6170531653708));
#999=VERTEX_POINT('',#998);
#1000=EDGE_CURVE('E1120',#997,#999,#995,.T.);
#1001=ORIENTED_EDGE('',*,*,#1000,.T.);
#1002=DIRECTION('',(0.,-0.887885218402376,0.46006503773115));
#1003=VECTOR('',#1002,1.);
#1004=CARTESIAN_POINT('',(3.,-6.60743660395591,21.0216931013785));
#1005=LINE('',#1004,#1003);
#1006=CARTESIAN_POINT('',(3.,6.69416264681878,14.1293599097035));
#1007=VERTEX_POINT('',#1006);
#1008=EDGE_CURVE('E1126',#999,#1007,#1005,.T.);
#1009=ORIENTED_EDGE('',*,*,#1008,.T.);
#1010=DIRECTION('',(0.,0.46006503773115,0.887885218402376));
#1011=VECTOR('',#1010,1.);
#1012=CARTESIAN_POINT('',(3.,7.11794706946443,14.9472267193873));
#1013=LINE('',#1012,#1011);
#1014=CARTESIAN_POINT('',(3.,4.96891875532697,10.7997903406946));
#1015=VERTEX_POINT('',#1014);
#1016=EDGE_CURVE('E1123',#1007,#1015,#1013,.F.);
#1017=ORIENTED_EDGE('',*,*,#1016,.T.);
#1018=DIRECTION('',(0.,0.887885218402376,-0.46006503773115));
#1019=VECTOR('',#1018,1.);
#1020=CARTESIAN_POINT('',(3.,-8.33268049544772,17.6921235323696));
#1021=LINE('',#1020,#1019);
#1022=EDGE_CURVE('E1117',#1015,#997,#1021,.T.);
#1023=ORIENTED_EDGE('',*,*,#1022,.T.);
#1024=EDGE_LOOP('',(#1001,#1009,#1017,#1023));
#1025=FACE_BOUND('',#1024,.T.);
#1026=DIRECTION('',(0.,0.203456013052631,0.979084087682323));
#1027=VECTOR('',#1026,1.);
#1028=CARTESIAN_POINT('',(3.,3.91154267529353,16.0867831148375));
#1029=LINE('',#1028,#1027);
#1030=CARTESIAN_POINT('',(3.,2.96117110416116,11.5133440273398));
#1031=VERTEX_POINT('',#1030);
#1032=CARTESIAN_POINT('',(3.,3.72413115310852,15.1849093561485));
#1033=VERTEX_POINT('',#1032);
#1034=EDGE_CURVE('E1132',#1031,#1033,#1029,.T.);
#1035=ORIENTED_EDGE('',*,*,#1034,.T.);
#1036=DIRECTION('',(0.,-0.979084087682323,0.203456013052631));
#1037=VECTOR('',#1036,1.);
#1038=CARTESIAN_POINT('',(3.,-13.5965986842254,18.7841984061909));
#1039=LINE('',#1038,#1037);
#1040=CARTESIAN_POINT('',(3.,2.63386925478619,15.4114683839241));
#1041=VERTEX_POINT('',#1040);
#1042=EDGE_CURVE('E1138',#1033,#1041,#1039,.T.);
#1043=ORIENTED_EDGE('',*,*,#1042,.T.);
#1044=DIRECTION('',(0.,0.203456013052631,0.979084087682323));
#1045=VECTOR('',#1044,1.);
#1046=CARTESIAN_POINT('',(3.,2.82128077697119,16.3133421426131));
#1047=LINE('',#1046,#1045);
#1048=CARTESIAN_POINT('',(3.,1.87090920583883,11.7399030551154));
#1049=VERTEX_POINT('',#1048);
#1050=EDGE_CURVE('E1135',#1041,#1049,#1047,.F.);
#1051=ORIENTED_EDGE('',*,*,#1050,.T.);
#1052=DIRECTION('',(0.,0.979084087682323,-0.203456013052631));
#1053=VECTOR('',#1052,1.);
#1054=CARTESIAN_POINT('',(3.,-14.3595587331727,15.1126330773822));
#1055=LINE('',#1054,#1053);
#1056=EDGE_CURVE('E1129',#1049,#1031,#1055,.T.);
#1057=ORIENTED_EDGE('',*,*,#1056,.T.);
#1058=EDGE_LOOP('',(#1035,#1043,#1051,#1057));
#1059=FACE_BOUND('',#1058,.T.);
#1060=DIRECTION('',(0.,-0.0682424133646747,0.997668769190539));
#1061=VECTOR('',#1060,1.);
#1062=CARTESIAN_POINT('',(3.,-0.573670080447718,16.5455631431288));
#1063=LINE('',#1062,#1061);
#1064=CARTESIAN_POINT('',(3.,-0.254900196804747,11.8853124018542));
#1065=VERTEX_POINT('',#1064);
#1066=CARTESIAN_POINT('',(3.,-0.510809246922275,15.6265702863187));
#1067=VERTEX_POINT('',#1066);
#1068=EDGE_CURVE('E1144',#1065,#1067,#1063,.T.);
#1069=ORIENTED_EDGE('',*,*,#1068,.T.);
#1070=DIRECTION('',(0.,-0.997668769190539,-0.0682424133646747));
#1071=VECTOR('',#1070,1.);
#1072=CARTESIAN_POINT('',(3.,-18.4847897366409,14.3971163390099));
#1073=LINE('',#1072,#1071);
#1074=CARTESIAN_POINT('',(3.,-1.62176617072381,15.5505787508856));
#1075=VERTEX_POINT('',#1074);
#1076=EDGE_CURVE('E1150',#1067,#1075,#1073,.T.);
#1077=ORIENTED_EDGE('',*,*,#1076,.T.);
#1078=DIRECTION('',(0.,-0.0682424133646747,0.997668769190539));
#1079=VECTOR('',#1078,1.);
#1080=CARTESIAN_POINT('',(3.,-1.68462700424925,16.4695716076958));
#1081=LINE('',#1080,#1079);
#1082=CARTESIAN_POINT('',(3.,-1.36585712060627,11.8093208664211));
#1083=VERTEX_POINT('',#1082);
#1084=EDGE_CURVE('E1147',#1075,#1083,#1081,.F.);
#1085=ORIENTED_EDGE('',*,*,#1084,.T.);
#1086=DIRECTION('',(0.,0.997668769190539,0.0682424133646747));
#1087=VECTOR('',#1086,1.);
#1088=CARTESIAN_POINT('',(3.,-18.2288806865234,10.6558584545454));
#1089=LINE('',#1088,#1087);
#1090=EDGE_CURVE('E1141',#1083,#1065,#1089,.T.);
#1091=ORIENTED_EDGE('',*,*,#1090,.T.);
#1092=EDGE_LOOP('',(#1069,#1077,#1085,#1091));
#1093=FACE_BOUND('',#1092,.T.);
#1094=DIRECTION('',(0.,-0.33487961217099,0.942260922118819));
#1095=VECTOR('',#1094,1.);
#1096=CARTESIAN_POINT('',(3.,-5.01633635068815,15.7772344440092));
#1097=LINE('',#1096,#1095);
#1098=CARTESIAN_POINT('',(3.,-3.45206671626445,11.3758015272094));
#1099=VERTEX_POINT('',#1098);
#1100=CARTESIAN_POINT('',(3.,-4.70786526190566,14.9092799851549));
#1101=VERTEX_POINT('',#1100);
#1102=EDGE_CURVE('E1156',#1099,#1101,#1097,.T.);
#1103=ORIENTED_EDGE('',*,*,#1102,.T.);
#1104=DIRECTION('',(0.,-0.942260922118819,-0.33487961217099));
#1105=VECTOR('',#1104,1.);
#1106=CARTESIAN_POINT('',(3.,-20.7699677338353,9.20080739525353));
#1107=LINE('',#1106,#1105);
#1108=CARTESIAN_POINT('',(3.,-5.75712261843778,14.5363738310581));
#1109=VERTEX_POINT('',#1108);
#1110=EDGE_CURVE('E1162',#1101,#1109,#1107,.T.);
#1111=ORIENTED_EDGE('',*,*,#1110,.T.);
#1112=DIRECTION('',(0.,-0.33487961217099,0.942260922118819));
#1113=VECTOR('',#1112,1.);
#1114=CARTESIAN_POINT('',(3.,-6.06559370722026,15.4043282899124));
#1115=LINE('',#1114,#1113);
#1116=CARTESIAN_POINT('',(3.,-4.50132407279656,11.0028953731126));
#1117=VERTEX_POINT('',#1116);
#1118=EDGE_CURVE('E1159',#1109,#1117,#1115,.F.);
#1119=ORIENTED_EDGE('',*,*,#1118,.T.);
#1120=DIRECTION('',(0.,0.942260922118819,0.33487961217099));
#1121=VECTOR('',#1120,1.);
#1122=CARTESIAN_POINT('',(3.,-19.5141691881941,5.66732893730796));
#1123=LINE('',#1122,#1121);
#1124=EDGE_CURVE('E1153',#1117,#1099,#1123,.T.);
#1125=ORIENTED_EDGE('',*,*,#1124,.T.);
#1126=EDGE_LOOP('',(#1103,#1111,#1119,#1125));
#1127=FACE_BOUND('',#1126,.T.);
#1128=DIRECTION('',(0.,-0.576680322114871,0.816969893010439));
#1129=VECTOR('',#1128,1.);
#1130=CARTESIAN_POINT('',(3.,-9.08696390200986,13.8387804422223));
#1131=LINE('',#1130,#1129);
#1132=CARTESIAN_POINT('',(3.,-6.39320923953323,10.0225994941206));
#1133=VERTEX_POINT('',#1132);
#1134=CARTESIAN_POINT('',(3.,-8.55576044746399,13.0862365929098));
#1135=VERTEX_POINT('',#1134);
#1136=EDGE_CURVE('E1168',#1133,#1135,#1131,.T.);
#1137=ORIENTED_EDGE('',*,*,#1136,.T.);
#1138=DIRECTION('',(0.,-0.816969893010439,-0.576680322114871));
#1139=VECTOR('',#1138,1.);
#1140=CARTESIAN_POINT('',(3.,-20.6908266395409,4.5203715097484));
#1141=LINE('',#1140,#1139);
#1142=CARTESIAN_POINT('',(3.,-9.46549961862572,12.4440725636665));
#1143=VERTEX_POINT('',#1142);
#1144=EDGE_CURVE('E1174',#1135,#1143,#1141,.T.);
#1145=ORIENTED_EDGE('',*,*,#1144,.T.);
#1146=DIRECTION('',(0.,-0.576680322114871,0.816969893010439));
#1147=VECTOR('',#1146,1.);
#1148=CARTESIAN_POINT('',(3.,-9.99670307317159,13.196616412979));
#1149=LINE('',#1148,#1147);
#1150=CARTESIAN_POINT('',(3.,-7.30294841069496,9.38043546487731));
#1151=VERTEX_POINT('',#1150);
#1152=EDGE_CURVE('E1171',#1143,#1151,#1149,.F.);
#1153=ORIENTED_EDGE('',*,*,#1152,.T.);
#1154=DIRECTION('',(0.,0.816969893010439,0.576680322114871));
#1155=VECTOR('',#1154,1.);
#1156=CARTESIAN_POINT('',(3.,-18.5282754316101,1.45673441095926));
#1157=LINE('',#1156,#1155);
#1158=EDGE_CURVE('E1165',#1151,#1133,#1157,.T.);
#1159=ORIENTED_EDGE('',*,*,#1158,.T.);
#1160=EDGE_LOOP('',(#1137,#1145,#1153,#1159));
#1161=FACE_BOUND('',#1160,.T.);
#1162=DIRECTION('',(0.,-0.775711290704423,0.631087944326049));
#1163=VECTOR('',#1162,1.);
#1164=CARTESIAN_POINT('',(3.,-12.4836529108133,10.8739674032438));
#1165=LINE('',#1164,#1163);
#1166=CARTESIAN_POINT('',(3.,-8.860196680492,7.92606710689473));
#1167=VERTEX_POINT('',#1166);
#1168=CARTESIAN_POINT('',(3.,-11.7691140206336,10.2926468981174));
#1169=VERTEX_POINT('',#1168);
#1170=EDGE_CURVE('E1180',#1167,#1169,#1165,.T.);
#1171=ORIENTED_EDGE('',*,*,#1170,.T.);
#1172=DIRECTION('',(0.,-0.631087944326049,-0.775711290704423));
#1173=VECTOR('',#1172,1.);
#1174=CARTESIAN_POINT('',(3.,-19.090248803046,1.2937633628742));
#1175=LINE('',#1174,#1173);
#1176=CARTESIAN_POINT('',(3.,-12.4718638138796,9.4288513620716));
#1177=VERTEX_POINT('',#1176);
#1178=EDGE_CURVE('E1186',#1169,#1177,#1175,.T.);
#1179=ORIENTED_EDGE('',*,*,#1178,.T.);
#1180=DIRECTION('',(0.,-0.775711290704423,0.631087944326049));
#1181=VECTOR('',#1180,1.);
#1182=CARTESIAN_POINT('',(3.,-13.1864027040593,10.010171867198));
#1183=LINE('',#1182,#1181);
#1184=CARTESIAN_POINT('',(3.,-9.56294647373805,7.06227157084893));
#1185=VERTEX_POINT('',#1184);
#1186=EDGE_CURVE('E1183',#1177,#1185,#1183,.F.);
#1187=ORIENTED_EDGE('',*,*,#1186,.T.);
#1188=DIRECTION('',(0.,0.631087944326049,0.775711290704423));
#1189=VECTOR('',#1188,1.);
#1190=CARTESIAN_POINT('',(3.,-16.1813314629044,-1.07281642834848));
#1191=LINE('',#1190,#1189);
#1192=EDGE_CURVE('E1177',#1185,#1167,#1191,.T.);
#1193=ORIENTED_EDGE('',*,*,#1192,.T.);
#1194=EDGE_LOOP('',(#1171,#1179,#1187,#1193));
#1195=FACE_BOUND('',#1194,.T.);
#1196=DIRECTION('',(0.,-0.917211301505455,0.398401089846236));
#1197=VECTOR('',#1196,1.);
#1198=CARTESIAN_POINT('',(3.,-14.9544864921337,7.10268194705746));
#1199=LINE('',#1198,#1197);
#1200=CARTESIAN_POINT('',(3.,-10.6700638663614,5.24169458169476));
#1201=VERTEX_POINT('',#1200);
#1202=CARTESIAN_POINT('',(3.,-14.1096062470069,6.73569866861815));
#1203=VERTEX_POINT('',#1202);
#1204=EDGE_CURVE('E1192',#1201,#1203,#1199,.T.);
#1205=ORIENTED_EDGE('',*,*,#1204,.T.);
#1206=DIRECTION('',(0.,-0.398401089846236,-0.917211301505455));
#1207=VECTOR('',#1206,1.);
#1208=CARTESIAN_POINT('',(3.,-17.1090865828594,-0.169797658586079));
#1209=LINE('',#1208,#1207);
#1210=CARTESIAN_POINT('',(3.,-14.5532469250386,5.71433538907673));
#1211=VERTEX_POINT('',#1210);
#1212=EDGE_CURVE('E1198',#1203,#1211,#1209,.T.);
#1213=ORIENTED_EDGE('',*,*,#1212,.T.);
#1214=DIRECTION('',(0.,-0.917211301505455,0.398401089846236));
#1215=VECTOR('',#1214,1.);
#1216=CARTESIAN_POINT('',(3.,-15.3981271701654,6.08131866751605));
#1217=LINE('',#1216,#1215);
#1218=CARTESIAN_POINT('',(3.,-11.1137045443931,4.22033130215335));
#1219=VERTEX_POINT('',#1218);
#1220=EDGE_CURVE('E1195',#1211,#1219,#1217,.F.);
#1221=ORIENTED_EDGE('',*,*,#1220,.T.);
#1222=DIRECTION('',(0.,0.398401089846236,0.917211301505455));
#1223=VECTOR('',#1222,1.);
#1224=CARTESIAN_POINT('',(3.,-13.669544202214,-1.66380174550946));
#1225=LINE('',#1224,#1223);
#1226=EDGE_CURVE('E1189',#1219,#1201,#1225,.T.);
#1227=ORIENTED_EDGE('',*,*,#1226,.T.);
#1228=EDGE_LOOP('',(#1205,#1213,#1221,#1227));
#1229=FACE_BOUND('',#1228,.T.);
#1230=DIRECTION('',(0.,-0.990685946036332,0.13616664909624));
#1231=VECTOR('',#1230,1.);
#1232=CARTESIAN_POINT('',(3.,-16.316214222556,2.80462306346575));
#1233=LINE('',#1232,#1231);
#1234=CARTESIAN_POINT('',(3.,-11.688581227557,2.16856954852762));
#1235=VERTEX_POINT('',#1234);
#1236=CARTESIAN_POINT('',(3.,-15.4036535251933,2.67919448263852));
#1237=VERTEX_POINT('',#1236);
#1238=EDGE_CURVE('E1204',#1235,#1237,#1233,.T.);
#1239=ORIENTED_EDGE('',*,*,#1238,.T.);
#1240=DIRECTION('',(0.,-0.13616664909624,-0.990685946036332));
#1241=VECTOR('',#1240,1.);
#1242=CARTESIAN_POINT('',(3.,-15.8039416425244,-0.233117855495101));
#1243=LINE('',#1242,#1241);
#1244=CARTESIAN_POINT('',(3.,-15.5552822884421,1.57601330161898));
#1245=VERTEX_POINT('',#1244);
#1246=EDGE_CURVE('E1210',#1237,#1245,#1243,.T.);
#1247=ORIENTED_EDGE('',*,*,#1246,.T.);
#1248=DIRECTION('',(0.,-0.990685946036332,0.13616664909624));
#1249=VECTOR('',#1248,1.);
#1250=CARTESIAN_POINT('',(3.,-16.4678429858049,1.70144188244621));
#1251=LINE('',#1250,#1249);
#1252=CARTESIAN_POINT('',(3.,-11.8402099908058,1.06538836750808));
#1253=VERTEX_POINT('',#1252);
#1254=EDGE_CURVE('E1207',#1245,#1253,#1251,.F.);
#1255=ORIENTED_EDGE('',*,*,#1254,.T.);
#1256=DIRECTION('',(0.,0.13616664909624,0.990685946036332));
#1257=VECTOR('',#1256,1.);
#1258=CARTESIAN_POINT('',(3.,-12.0888693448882,-0.743742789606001));
#1259=LINE('',#1258,#1257);
#1260=EDGE_CURVE('E1201',#1253,#1235,#1259,.T.);
#1261=ORIENTED_EDGE('',*,*,#1260,.T.);
#1262=EDGE_LOOP('',(#1239,#1247,#1255,#1261));
#1263=FACE_BOUND('',#1262,.T.);
#1264=DIRECTION('',(0.,-0.99068594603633,-0.136166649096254));
#1265=VECTOR('',#1264,1.);
#1266=CARTESIAN_POINT('',(3.,-16.4678429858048,-1.70144188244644));
#1267=LINE('',#1266,#1265);
#1268=CARTESIAN_POINT('',(3.,-11.8402099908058,-1.06538836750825));
#1269=VERTEX_POINT('',#1268);
#1270=CARTESIAN_POINT('',(3.,-15.5552822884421,-1.5760133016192));
#1271=VERTEX_POINT('',#1270);
#1272=EDGE_CURVE('E1216',#1269,#1271,#1267,.T.);
#1273=ORIENTED_EDGE('',*,*,#1272,.T.);
#1274=DIRECTION('',(0.,0.136166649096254,-0.99068594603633));
#1275=VECTOR('',#1274,1.);
#1276=CARTESIAN_POINT('',(3.,-15.8039416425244,0.23311785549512));
#1277=LINE('',#1276,#1275);
#1278=CARTESIAN_POINT('',(3.,-15.4036535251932,-2.67919448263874));
#1279=VERTEX_POINT('',#1278);
#1280=EDGE_CURVE('E1222',#1271,#1279,#1277,.T.);
#1281=ORIENTED_EDGE('',*,*,#1280,.T.);
#1282=DIRECTION('',(0.,-0.99068594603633,-0.136166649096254));
#1283=VECTOR('',#1282,1.);
#1284=CARTESIAN_POINT('',(3.,-16.316214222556,-2.80462306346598));
#1285=LINE('',#1284,#1283);
#1286=CARTESIAN_POINT('',(3.,-11.688581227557,-2.16856954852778));
#1287=VERTEX_POINT('',#1286);
#1288=EDGE_CURVE('E1219',#1279,#1287,#1285,.F.);
#1289=ORIENTED_EDGE('',*,*,#1288,.T.);
#1290=DIRECTION('',(0.,-0.136166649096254,0.99068594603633));
#1291=VECTOR('',#1290,1.);
#1292=CARTESIAN_POINT('',(3.,-12.0888693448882,0.743742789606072));
#1293=LINE('',#1292,#1291);
#1294=EDGE_CURVE('E1213',#1287,#1269,#1293,.T.);
#1295=ORIENTED_EDGE('',*,*,#1294,.T.);
#1296=EDGE_LOOP('',(#1273,#1281,#1289,#1295));
#1297=FACE_BOUND('',#1296,.T.);
#1298=DIRECTION('',(0.,-0.91721130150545,-0.398401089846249));
#1299=VECTOR('',#1298,1.);
#1300=CARTESIAN_POINT('',(3.,-15.3981271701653,-6.08131866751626));
#1301=LINE('',#1300,#1299);
#1302=CARTESIAN_POINT('',(3.,-11.1137045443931,-4.2203313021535));
#1303=VERTEX_POINT('',#1302);
#1304=CARTESIAN_POINT('',(3.,-14.5532469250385,-5.71433538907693));
#1305=VERTEX_POINT('',#1304);
#1306=EDGE_CURVE('E1228',#1303,#1305,#1301,.T.);
#1307=ORIENTED_EDGE('',*,*,#1306,.T.);
#1308=DIRECTION('',(0.,0.398401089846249,-0.91721130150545));
#1309=VECTOR('',#1308,1.);
#1310=CARTESIAN_POINT('',(3.,-17.1090865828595,0.169797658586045));
#1311=LINE('',#1310,#1309);
#1312=CARTESIAN_POINT('',(3.,-14.1096062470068,-6.73569866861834));
#1313=VERTEX_POINT('',#1312);
#1314=EDGE_CURVE('E1234',#1305,#1313,#1311,.T.);
#1315=ORIENTED_EDGE('',*,*,#1314,.T.);
#1316=DIRECTION('',(0.,-0.91721130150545,-0.398401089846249));
#1317=VECTOR('',#1316,1.);
#1318=CARTESIAN_POINT('',(3.,-14.9544864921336,-7.10268194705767));
#1319=LINE('',#1318,#1317);
#1320=CARTESIAN_POINT('',(3.,-10.6700638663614,-5.24169458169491));
#1321=VERTEX_POINT('',#1320);
#1322=EDGE_CURVE('E1231',#1313,#1321,#1319,.F.);
#1323=ORIENTED_EDGE('',*,*,#1322,.T.);
#1324=DIRECTION('',(0.,-0.398401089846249,0.91721130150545));
#1325=VECTOR('',#1324,1.);
#1326=CARTESIAN_POINT('',(3.,-13.6695442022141,1.66380174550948));
#1327=LINE('',#1326,#1325);
#1328=EDGE_CURVE('E1225',#1321,#1303,#1327,.T.);
#1329=ORIENTED_EDGE('',*,*,#1328,.T.);
#1330=EDGE_LOOP('',(#1307,#1315,#1323,#1329));
#1331=FACE_BOUND('',#1330,.T.);
#1332=DIRECTION('',(0.,-0.775711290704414,-0.631087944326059));
#1333=VECTOR('',#1332,1.);
#1334=CARTESIAN_POINT('',(3.,-13.1864027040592,-10.0101718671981));
#1335=LINE('',#1334,#1333);
#1336=CARTESIAN_POINT('',(3.,-9.56294647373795,-7.06227157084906));
#1337=VERTEX_POINT('',#1336);
#1338=CARTESIAN_POINT('',(3.,-12.4718638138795,-9.42885136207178));
#1339=VERTEX_POINT('',#1338);
#1340=EDGE_CURVE('E1240',#1337,#1339,#1335,.T.);
#1341=ORIENTED_EDGE('',*,*,#1340,.T.);
#1342=DIRECTION('',(0.,0.631087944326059,-0.775711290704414));
#1343=VECTOR('',#1342,1.);
#1344=CARTESIAN_POINT('',(3.,-19.0902488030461,-1.29376336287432));
#1345=LINE('',#1344,#1343);
#1346=CARTESIAN_POINT('',(3.,-11.7691140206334,-10.2926468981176));
#1347=VERTEX_POINT('',#1346);
#1348=EDGE_CURVE('E1246',#1339,#1347,#1345,.T.);
#1349=ORIENTED_EDGE('',*,*,#1348,.T.);
#1350=DIRECTION('',(0.,-0.775711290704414,-0.631087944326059));
#1351=VECTOR('',#1350,1.);
#1352=CARTESIAN_POINT('',(3.,-12.4836529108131,-10.8739674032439));
#1353=LINE('',#1352,#1351);
#1354=CARTESIAN_POINT('',(3.,-8.86019668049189,-7.92606710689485));
#1355=VERTEX_POINT('',#1354);
#1356=EDGE_CURVE('E1243',#1347,#1355,#1353,.F.);
#1357=ORIENTED_EDGE('',*,*,#1356,.T.);
#1358=DIRECTION('',(0.,-0.631087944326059,0.775711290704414));
#1359=VECTOR('',#1358,1.);
#1360=CARTESIAN_POINT('',(3.,-16.1813314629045,1.0728164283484));
#1361=LINE('',#1360,#1359);
#1362=EDGE_CURVE('E1237',#1355,#1337,#1361,.T.);
#1363=ORIENTED_EDGE('',*,*,#1362,.T.);
#1364=EDGE_LOOP('',(#1341,#1349,#1357,#1363));
#1365=FACE_BOUND('',#1364,.T.);
#1366=DIRECTION('',(0.,-0.57668032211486,-0.816969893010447));
#1367=VECTOR('',#1366,1.);
#1368=CARTESIAN_POINT('',(3.,-9.99670307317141,-13.1966164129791));
#1369=LINE('',#1368,#1367);
#1370=CARTESIAN_POINT('',(3.,-7.30294841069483,-9.38043546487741));
#1371=VERTEX_POINT('',#1370);
#1372=CARTESIAN_POINT('',(3.,-9.46549961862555,-12.4440725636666));
#1373=VERTEX_POINT('',#1372);
#1374=EDGE_CURVE('E1252',#1371,#1373,#1369,.T.);
#1375=ORIENTED_EDGE('',*,*,#1374,.T.);
#1376=DIRECTION('',(0.,0.816969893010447,-0.57668032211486));
#1377=VECTOR('',#1376,1.);
#1378=CARTESIAN_POINT('',(3.,-20.690826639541,-4.5203715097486));
#1379=LINE('',#1378,#1377);
#1380=CARTESIAN_POINT('',(3.,-8.55576044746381,-13.0862365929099));
#1381=VERTEX_POINT('',#1380);
#1382=EDGE_CURVE('E1258',#1373,#1381,#1379,.T.);
#1383=ORIENTED_EDGE('',*,*,#1382,.T.);
#1384=DIRECTION('',(0.,-0.57668032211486,-0.816969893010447));
#1385=VECTOR('',#1384,1.);
#1386=CARTESIAN_POINT('',(3.,-9.08696390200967,-13.8387804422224));
#1387=LINE('',#1386,#1385);
#1388=CARTESIAN_POINT('',(3.,-6.39320923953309,-10.0225994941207));
#1389=VERTEX_POINT('',#1388);
#1390=EDGE_CURVE('E1255',#1381,#1389,#1387,.F.);
#1391=ORIENTED_EDGE('',*,*,#1390,.T.);
#1392=DIRECTION('',(0.,-0.816969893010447,0.57668032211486));
#1393=VECTOR('',#1392,1.);
#1394=CARTESIAN_POINT('',(3.,-18.5282754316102,-1.45673441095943));
#1395=LINE('',#1394,#1393);
#1396=EDGE_CURVE('E1249',#1389,#1371,#1395,.T.);
#1397=ORIENTED_EDGE('',*,*,#1396,.T.);
#1398=EDGE_LOOP('',(#1375,#1383,#1391,#1397));
#1399=FACE_BOUND('',#1398,.T.);
#1400=DIRECTION('',(0.,-0.334879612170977,-0.942260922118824));
#1401=VECTOR('',#1400,1.);
#1402=CARTESIAN_POINT('',(3.,-6.06559370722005,-15.4043282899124));
#1403=LINE('',#1402,#1401);
#1404=CARTESIAN_POINT('',(3.,-4.50132407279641,-11.0028953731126));
#1405=VERTEX_POINT('',#1404);
#1406=CARTESIAN_POINT('',(3.,-5.75712261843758,-14.5363738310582));
#1407=VERTEX_POINT('',#1406);
#1408=EDGE_CURVE('E1264',#1405,#1407,#1403,.T.);
#1409=ORIENTED_EDGE('',*,*,#1408,.T.);
#1410=DIRECTION('',(0.,0.942260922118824,-0.334879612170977));
#1411=VECTOR('',#1410,1.);
#1412=CARTESIAN_POINT('',(3.,-20.7699677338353,-9.20080739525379));
#1413=LINE('',#1412,#1411);
#1414=CARTESIAN_POINT('',(3.,-4.70786526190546,-14.909279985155));
#1415=VERTEX_POINT('',#1414);
#1416=EDGE_CURVE('E1270',#1407,#1415,#1413,.T.);
#1417=ORIENTED_EDGE('',*,*,#1416,.T.);
#1418=DIRECTION('',(0.,-0.334879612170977,-0.942260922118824));
#1419=VECTOR('',#1418,1.);
#1420=CARTESIAN_POINT('',(3.,-5.01633635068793,-15.7772344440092));
#1421=LINE('',#1420,#1419);
#1422=CARTESIAN_POINT('',(3.,-3.45206671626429,-11.3758015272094));
#1423=VERTEX_POINT('',#1422);
#1424=EDGE_CURVE('E1267',#1415,#1423,#1421,.F.);
#1425=ORIENTED_EDGE('',*,*,#1424,.T.);
#1426=DIRECTION('',(0.,-0.942260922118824,0.334879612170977));
#1427=VECTOR('',#1426,1.);
#1428=CARTESIAN_POINT('',(3.,-19.5141691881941,-5.6673289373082));
#1429=LINE('',#1428,#1427);
#1430=EDGE_CURVE('E1261',#1423,#1405,#1429,.T.);
#1431=ORIENTED_EDGE('',*,*,#1430,.T.);
#1432=EDGE_LOOP('',(#1409,#1417,#1425,#1431));
#1433=FACE_BOUND('',#1432,.T.);
#1434=DIRECTION('',(0.,-0.0682424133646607,-0.99766876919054));
#1435=VECTOR('',#1434,1.);
#1436=CARTESIAN_POINT('',(3.,-1.68462700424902,-16.4695716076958));
#1437=LINE('',#1436,#1435);
#1438=CARTESIAN_POINT('',(3.,-1.36585712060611,-11.8093208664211));
#1439=VERTEX_POINT('',#1438);
#1440=CARTESIAN_POINT('',(3.,-1.62176617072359,-15.5505787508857));
#1441=VERTEX_POINT('',#1440);
#1442=EDGE_CURVE('E1276',#1439,#1441,#1437,.T.);
#1443=ORIENTED_EDGE('',*,*,#1442,.T.);
#1444=DIRECTION('',(0.,0.99766876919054,-0.0682424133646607));
#1445=VECTOR('',#1444,1.);
#1446=CARTESIAN_POINT('',(3.,-18.4847897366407,-14.3971163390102));
#1447=LINE('',#1446,#1445);
#1448=CARTESIAN_POINT('',(3.,-0.510809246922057,-15.6265702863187));
#1449=VERTEX_POINT('',#1448);
#1450=EDGE_CURVE('E1282',#1441,#1449,#1447,.T.);
#1451=ORIENTED_EDGE('',*,*,#1450,.T.);
#1452=DIRECTION('',(0.,-0.0682424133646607,-0.99766876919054));
#1453=VECTOR('',#1452,1.);
#1454=CARTESIAN_POINT('',(3.,-0.573670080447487,-16.5455631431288));
#1455=LINE('',#1454,#1453);
#1456=CARTESIAN_POINT('',(3.,-0.254900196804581,-11.8853124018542));
#1457=VERTEX_POINT('',#1456);
#1458=EDGE_CURVE('E1279',#1449,#1457,#1455,.F.);
#1459=ORIENTED_EDGE('',*,*,#1458,.T.);
#1460=DIRECTION('',(0.,-0.99766876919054,0.0682424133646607));
#1461=VECTOR('',#1460,1.);
#1462=CARTESIAN_POINT('',(3.,-18.2288806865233,-10.6558584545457));
#1463=LINE('',#1462,#1461);
#1464=EDGE_CURVE('E1273',#1457,#1439,#1463,.T.);
#1465=ORIENTED_EDGE('',*,*,#1464,.T.);
#1466=EDGE_LOOP('',(#1443,#1451,#1459,#1465));
#1467=FACE_BOUND('',#1466,.T.);
#1468=DIRECTION('',(0.,0.203456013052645,-0.979084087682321));
#1469=VECTOR('',#1468,1.);
#1470=CARTESIAN_POINT('',(3.,2.82128077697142,-16.3133421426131));
#1471=LINE('',#1470,#1469);
#1472=CARTESIAN_POINT('',(3.,1.87090920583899,-11.7399030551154));
#1473=VERTEX_POINT('',#1472);
#1474=CARTESIAN_POINT('',(3.,2.63386925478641,-15.4114683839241));
#1475=VERTEX_POINT('',#1474);
#1476=EDGE_CURVE('E1288',#1473,#1475,#1471,.T.);
#1477=ORIENTED_EDGE('',*,*,#1476,.T.);
#1478=DIRECTION('',(0.,0.979084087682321,0.203456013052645));
#1479=VECTOR('',#1478,1.);
#1480=CARTESIAN_POINT('',(3.,-13.5965986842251,-18.7841984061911));
#1481=LINE('',#1480,#1479);
#1482=CARTESIAN_POINT('',(3.,3.72413115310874,-15.1849093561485));
#1483=VERTEX_POINT('',#1482);
#1484=EDGE_CURVE('E1294',#1475,#1483,#1481,.T.);
#1485=ORIENTED_EDGE('',*,*,#1484,.T.);
#1486=DIRECTION('',(0.,0.203456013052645,-0.979084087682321));
#1487=VECTOR('',#1486,1.);
#1488=CARTESIAN_POINT('',(3.,3.91154267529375,-16.0867831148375));
#1489=LINE('',#1488,#1487);
#1490=CARTESIAN_POINT('',(3.,2.96117110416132,-11.5133440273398));
#1491=VERTEX_POINT('',#1490);
#1492=EDGE_CURVE('E1291',#1483,#1491,#1489,.F.);
#1493=ORIENTED_EDGE('',*,*,#1492,.T.);
#1494=DIRECTION('',(0.,-0.979084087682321,-0.203456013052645));
#1495=VECTOR('',#1494,1.);
#1496=CARTESIAN_POINT('',(3.,-14.3595587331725,-15.1126330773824));
#1497=LINE('',#1496,#1495);
#1498=EDGE_CURVE('E1285',#1491,#1473,#1497,.T.);
#1499=ORIENTED_EDGE('',*,*,#1498,.T.);
#1500=EDGE_LOOP('',(#1477,#1485,#1493,#1499));
#1501=FACE_BOUND('',#1500,.T.);
#1502=DIRECTION('',(0.,0.460065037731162,-0.88788521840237));
#1503=VECTOR('',#1502,1.);
#1504=CARTESIAN_POINT('',(3.,7.11794706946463,-14.9472267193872));
#1505=LINE('',#1504,#1503);
#1506=CARTESIAN_POINT('',(3.,4.96891875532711,-10.7997903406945));
#1507=VERTEX_POINT('',#1506);
#1508=CARTESIAN_POINT('',(3.,6.69416264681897,-14.1293599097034));
#1509=VERTEX_POINT('',#1508);
#1510=EDGE_CURVE('E1300',#1507,#1509,#1505,.T.);
#1511=ORIENTED_EDGE('',*,*,#1510,.T.);
#1512=DIRECTION('',(0.,0.88788521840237,0.460065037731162));
#1513=VECTOR('',#1512,1.);
#1514=CARTESIAN_POINT('',(3.,-6.60743660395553,-21.0216931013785));
#1515=LINE('',#1514,#1513);
#1516=CARTESIAN_POINT('',(3.,7.68286978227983,-13.6170531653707));
#1517=VERTEX_POINT('',#1516);
#1518=EDGE_CURVE('E1306',#1509,#1517,#1515,.T.);
#1519=ORIENTED_EDGE('',*,*,#1518,.T.);
#1520=DIRECTION('',(0.,0.460065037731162,-0.88788521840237));
#1521=VECTOR('',#1520,1.);
#1522=CARTESIAN_POINT('',(3.,8.1066542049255,-14.4349199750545));
#1523=LINE('',#1522,#1521);
#1524=CARTESIAN_POINT('',(3.,5.95762589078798,-10.2874835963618));
#1525=VERTEX_POINT('',#1524);
#1526=EDGE_CURVE('E1303',#1517,#1525,#1523,.F.);
#1527=ORIENTED_EDGE('',*,*,#1526,.T.);
#1528=DIRECTION('',(0.,-0.88788521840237,-0.460065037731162));
#1529=VECTOR('',#1528,1.);
#1530=CARTESIAN_POINT('',(3.,-8.33268049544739,-17.6921235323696));
#1531=LINE('',#1530,#1529);
#1532=EDGE_CURVE('E1297',#1525,#1507,#1531,.T.);
#1533=ORIENTED_EDGE('',*,*,#1532,.T.);
#1534=EDGE_LOOP('',(#1511,#1519,#1527,#1533));
#1535=FACE_BOUND('',#1534,.T.);
#1536=DIRECTION('',(0.,0.682553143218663,-0.730835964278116));
#1537=VECTOR('',#1536,1.);
#1538=CARTESIAN_POINT('',(3.,10.8867077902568,-12.4725438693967));
#1539=LINE('',#1538,#1537);
#1540=CARTESIAN_POINT('',(3.,7.69840633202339,-9.05870658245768));
#1541=VERTEX_POINT('',#1540);
#1542=CARTESIAN_POINT('',(3.,10.2579806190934,-11.7993414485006));
#1543=VERTEX_POINT('',#1542);
#1544=EDGE_CURVE('E1312',#1541,#1543,#1539,.T.);
#1545=ORIENTED_EDGE('',*,*,#1544,.T.);
#1546=DIRECTION('',(0.,0.730835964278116,0.682553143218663));
#1547=VECTOR('',#1546,1.);
#1548=CARTESIAN_POINT('',(3.,1.31777174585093,-20.1489136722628));
#1549=LINE('',#1548,#1547);
#1550=CARTESIAN_POINT('',(3.,11.0718051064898,-11.0392824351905));
#1551=VERTEX_POINT('',#1550);
#1552=EDGE_CURVE('E1318',#1543,#1551,#1549,.T.);
#1553=ORIENTED_EDGE('',*,*,#1552,.T.);
#1554=DIRECTION('',(0.,0.682553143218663,-0.730835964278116));
#1555=VECTOR('',#1554,1.);
#1556=CARTESIAN_POINT('',(3.,11.7005322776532,-11.7124848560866));
#1557=LINE('',#1556,#1555);
#1558=CARTESIAN_POINT('',(3.,8.51223081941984,-8.29864756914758));
#1559=VERTEX_POINT('',#1558);
#1560=EDGE_CURVE('E1315',#1551,#1559,#1557,.F.);
#1561=ORIENTED_EDGE('',*,*,#1560,.T.);
#1562=DIRECTION('',(0.,-0.730835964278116,-0.682553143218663));
#1563=VECTOR('',#1562,1.);
#1564=CARTESIAN_POINT('',(3.,-1.24180254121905,-17.4082788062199));
#1565=LINE('',#1564,#1563);
#1566=EDGE_CURVE('E1309',#1559,#1541,#1565,.T.);
#1567=ORIENTED_EDGE('',*,*,#1566,.T.);
#1568=EDGE_LOOP('',(#1545,#1553,#1561,#1567));
#1569=FACE_BOUND('',#1568,.T.);
#1570=DIRECTION('',(0.,0.854419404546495,-0.519583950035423));
#1571=VECTOR('',#1570,1.);
#1572=CARTESIAN_POINT('',(3.,13.8480511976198,-9.07282949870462));
#1573=LINE('',#1572,#1571);
#1574=CARTESIAN_POINT('',(3.,9.85693832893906,-6.6457799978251));
#1575=VERTEX_POINT('',#1574);
#1576=CARTESIAN_POINT('',(3.,13.0610110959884,-8.59421981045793));
#1577=VERTEX_POINT('',#1576);
#1578=EDGE_CURVE('E1324',#1575,#1577,#1573,.T.);
#1579=ORIENTED_EDGE('',*,*,#1578,.T.);
#1580=DIRECTION('',(0.,0.519583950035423,0.854419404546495));
#1581=VECTOR('',#1580,1.);
#1582=CARTESIAN_POINT('',(3.,8.62587227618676,-15.8874948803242));
#1583=LINE('',#1582,#1581);
#1584=CARTESIAN_POINT('',(3.,13.6395952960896,-7.64277862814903));
#1585=VERTEX_POINT('',#1584);
#1586=EDGE_CURVE('E605',#1577,#1585,#1583,.T.);
#1587=ORIENTED_EDGE('',*,*,#1586,.T.);
#1588=DIRECTION('',(0.,0.854419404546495,-0.519583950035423));
#1589=VECTOR('',#1588,1.);
#1590=CARTESIAN_POINT('',(3.,14.426635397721,-8.12138831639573));
#1591=LINE('',#1590,#1589);
#1592=CARTESIAN_POINT('',(3.,10.4355225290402,-5.6943388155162));
#1593=VERTEX_POINT('',#1592);
#1594=EDGE_CURVE('E1327',#1585,#1593,#1591,.F.);
#1595=ORIENTED_EDGE('',*,*,#1594,.T.);
#1596=DIRECTION('',(0.,-0.519583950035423,-0.854419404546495));
#1597=VECTOR('',#1596,1.);
#1598=CARTESIAN_POINT('',(3.,5.4217995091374,-13.9390550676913));
#1599=LINE('',#1598,#1597);
#1600=EDGE_CURVE('E1321',#1593,#1575,#1599,.T.);
#1601=ORIENTED_EDGE('',*,*,#1600,.T.);
#1602=EDGE_LOOP('',(#1579,#1587,#1595,#1601));
#1603=FACE_BOUND('',#1602,.T.);
#1604=DIRECTION('',(0.,0.962917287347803,-0.269796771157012));
#1605=VECTOR('',#1604,1.);
#1606=CARTESIAN_POINT('',(3.,15.7823479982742,-5.00022486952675));
#1607=LINE('',#1606,#1605);
#1608=CARTESIAN_POINT('',(3.,11.2844263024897,-3.73996631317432));
#1609=VERTEX_POINT('',#1608);
#1610=CARTESIAN_POINT('',(3.,14.895366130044,-4.75170420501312));
#1611=VERTEX_POINT('',#1610);
#1612=EDGE_CURVE('E604',#1609,#1611,#1607,.T.);
#1613=ORIENTED_EDGE('',*,*,#1612,.T.);
#1614=DIRECTION('',(0.,0.269796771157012,0.962917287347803));
#1615=VECTOR('',#1614,1.);
#1616=CARTESIAN_POINT('',(3.,13.7717524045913,-8.76193411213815));
#1617=LINE('',#1616,#1615);
#1618=CARTESIAN_POINT('',(3.,15.1957990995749,-3.67944489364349));
#1619=VERTEX_POINT('',#1618);
#1620=EDGE_CURVE('E618',#1611,#1619,#1617,.T.);
#1621=ORIENTED_EDGE('',*,*,#1620,.T.);
#1622=DIRECTION('',(0.,0.962917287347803,-0.269796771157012));
#1623=VECTOR('',#1622,1.);
#1624=CARTESIAN_POINT('',(3.,16.0827809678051,-3.92796555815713));
#1625=LINE('',#1624,#1623);
#1626=CARTESIAN_POINT('',(3.,11.5848592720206,-2.6677070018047));
#1627=VERTEX_POINT('',#1626);
#1628=EDGE_CURVE('E610',#1619,#1627,#1625,.F.);
#1629=ORIENTED_EDGE('',*,*,#1628,.T.);
#1630=DIRECTION('',(0.,-0.269796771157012,-0.962917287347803));
#1631=VECTOR('',#1630,1.);
#1632=CARTESIAN_POINT('',(3.,10.160812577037,-7.75019622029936));
#1633=LINE('',#1632,#1631);
#1634=EDGE_CURVE('E599',#1627,#1609,#1633,.T.);
#1635=ORIENTED_EDGE('',*,*,#1634,.T.);
#1636=EDGE_LOOP('',(#1613,#1621,#1629,#1635));
#1637=FACE_BOUND('',#1636,.T.);
#1638=ADVANCED_FACE('F617',(#844,#855,#889,#923,#957,#991,#1025,#1059,#1093,#1127,#1161,#1195,
#1229,#1263,#1297,#1331,#1365,#1399,#1433,#1467,#1501,#1535,#1569,#1603,#1637),#833,.T.);
#1639=CARTESIAN_POINT('',(1.5,16.5461402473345,0.));
#1640=DIRECTION('',(0.,1.,0.));
#1641=DIRECTION('',(0.,0.,1.));
#1642=AXIS2_PLACEMENT_3D('',#1639,#1640,#1641);
#1643=CYLINDRICAL_SURFACE('',#1642,1.6);
#1644=CARTESIAN_POINT('',(1.5,11.875,0.));
#1645=DIRECTION('',(0.,1.,0.));
#1646=DIRECTION('',(0.,0.,1.));
#1647=AXIS2_PLACEMENT_3D('',#1644,#1645,#1646);
#1648=CIRCLE('',#1647,1.6);
#1649=EDGE_CURVE('E1052',#51,#871,#1648,.T.);
#1650=ORIENTED_EDGE('',*,*,#1649,.T.);
#1651=ORIENTED_EDGE('',*,*,#872,.T.);
#1652=CARTESIAN_POINT('',(1.5,15.625,0.));
#1653=DIRECTION('',(0.,1.,0.));
#1654=DIRECTION('',(0.,0.,1.));
#1655=AXIS2_PLACEMENT_3D('',#1652,#1653,#1654);
#1656=CIRCLE('',#1655,1.6);
#1657=EDGE_CURVE('E1064',#53,#861,#1656,.T.);
#1658=ORIENTED_EDGE('',*,*,#1657,.F.);
#1659=ORIENTED_EDGE('',*,*,#54,.F.);
#1660=EDGE_LOOP('',(#1650,#1651,#1658,#1659));
#1661=FACE_BOUND('',#1660,.T.);
#1662=ADVANCED_FACE('F695',(#1661),#1643,.T.);
#1663=CARTESIAN_POINT('',(-25.1852941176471,0.,0.));
#1664=DIRECTION('',(-1.,0.,0.));
#1665=DIRECTION('',(0.,-1.,0.));
#1666=AXIS2_PLACEMENT_3D('',#1663,#1664,#1665);
#1667=CYLINDRICAL_SURFACE('',#1666,17.5);
#1668=CARTESIAN_POINT('',(-0.300000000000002,0.,0.));
#1669=DIRECTION('',(1.,0.,0.));
#1670=DIRECTION('',(0.,1.,0.));
#1671=AXIS2_PLACEMENT_3D('',#1668,#1669,#1670);
#1672=CIRCLE('',#1671,17.5);
#1673=CARTESIAN_POINT('',(-0.300000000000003,17.5,0.));
#1674=VERTEX_POINT('',#1673);
#1675=EDGE_CURVE('E662',#1674,#1674,#1672,.F.);
#1676=ORIENTED_EDGE('',*,*,#1675,.T.);
#1677=EDGE_LOOP('',(#1676));
#1678=FACE_BOUND('',#1677,.T.);
#1679=CARTESIAN_POINT('',(-2.7,0.,0.));
#1680=DIRECTION('',(-1.,0.,0.));
#1681=DIRECTION('',(0.,-1.,0.));
#1682=AXIS2_PLACEMENT_3D('',#1679,#1680,#1681);
#1683=CIRCLE('',#1682,17.5);
#1684=CARTESIAN_POINT('',(-2.7,-17.5,0.));
#1685=VERTEX_POINT('',#1684);
#1686=EDGE_CURVE('E659',#1685,#1685,#1683,.F.);
#1687=ORIENTED_EDGE('',*,*,#1686,.T.);
#1688=EDGE_LOOP('',(#1687));
#1689=FACE_BOUND('',#1688,.T.);
#1690=ADVANCED_FACE('F686',(#1678,#1689),#1667,.T.);
#1691=CARTESIAN_POINT('',(-3.,-17.5,0.));
#1692=DIRECTION('',(-1.,0.,0.));
#1693=DIRECTION('',(0.,-1.,0.));
#1694=AXIS2_PLACEMENT_3D('',#1691,#1692,#1693);
#1695=PLANE('',#1694);
#1696=CARTESIAN_POINT('',(-3.,0.,0.));
#1697=DIRECTION('',(-1.,0.,0.));
#1698=DIRECTION('',(0.,-1.,0.));
#1699=AXIS2_PLACEMENT_3D('',#1696,#1697,#1698);
#1700=CIRCLE('',#1699,17.2);
#1701=CARTESIAN_POINT('',(-3.,-17.2,0.));
#1702=VERTEX_POINT('',#1701);
#1703=EDGE_CURVE('E11',#1702,#1702,#1700,.T.);
#1704=ORIENTED_EDGE('',*,*,#1703,.T.);
#1705=EDGE_LOOP('',(#1704));
#1706=FACE_BOUND('',#1705,.T.);
#1707=CARTESIAN_POINT('',(-3.,0.,0.));
#1708=DIRECTION('',(-1.,0.,0.));
#1709=DIRECTION('',(0.,-1.,0.));
#1710=AXIS2_PLACEMENT_3D('',#1707,#1708,#1709);
#1711=CIRCLE('',#1710,10.3);
#1712=CARTESIAN_POINT('',(-3.,-10.3,0.));
#1713=VERTEX_POINT('',#1712);
#1714=EDGE_CURVE('E41',#1713,#1713,#1711,.F.);
#1715=ORIENTED_EDGE('',*,*,#1714,.T.);
#1716=EDGE_LOOP('',(#1715));
#1717=FACE_BOUND('',#1716,.T.);
#1718=ADVANCED_FACE('F667',(#1706,#1717),#1695,.T.);
#1719=CARTESIAN_POINT('',(-25.1852941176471,0.,0.));
#1720=DIRECTION('',(-1.,0.,0.));
#1721=DIRECTION('',(0.,-1.,0.));
#1722=AXIS2_PLACEMENT_3D('',#1719,#1720,#1721);
#1723=CYLINDRICAL_SURFACE('',#1722,10.);
#1724=CARTESIAN_POINT('',(-0.300000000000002,0.,0.));
#1725=DIRECTION('',(1.,0.,0.));
#1726=DIRECTION('',(0.,1.,0.));
#1727=AXIS2_PLACEMENT_3D('',#1724,#1725,#1726);
#1728=CIRCLE('',#1727,10.);
#1729=CARTESIAN_POINT('',(-0.300000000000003,10.,0.));
#1730=VERTEX_POINT('',#1729);
#1731=EDGE_CURVE('E650',#1730,#1730,#1728,.T.);
#1732=ORIENTED_EDGE('',*,*,#1731,.T.);
#1733=EDGE_LOOP('',(#1732));
#1734=FACE_BOUND('',#1733,.T.);
#1735=CARTESIAN_POINT('',(-2.7,0.,0.));
#1736=DIRECTION('',(-1.,0.,0.));
#1737=DIRECTION('',(0.,-1.,0.));
#1738=AXIS2_PLACEMENT_3D('',#1735,#1736,#1737);
#1739=CIRCLE('',#1738,10.);
#1740=CARTESIAN_POINT('',(-2.7,-10.,0.));
#1741=VERTEX_POINT('',#1740);
#1742=EDGE_CURVE('E647',#1741,#1741,#1739,.T.);
#1743=ORIENTED_EDGE('',*,*,#1742,.T.);
#1744=EDGE_LOOP('',(#1743));
#1745=FACE_BOUND('',#1744,.T.);
#1746=ADVANCED_FACE('F674',(#1734,#1745),#1723,.F.);
#1747=CARTESIAN_POINT('',(1.5,15.625,0.));
#1748=DIRECTION('',(0.,-1.,0.));
#1749=DIRECTION('',(0.,0.,-1.));
#1750=AXIS2_PLACEMENT_3D('',#1747,#1748,#1749);
#1751=PLANE('',#1750);
#1752=ORIENTED_EDGE('',*,*,#1657,.T.);
#1753=ORIENTED_EDGE('',*,*,#864,.T.);
#1754=EDGE_CURVE('E1061',#863,#61,#1656,.T.);
#1755=ORIENTED_EDGE('',*,*,#1754,.T.);
#1756=ORIENTED_EDGE('',*,*,#62,.F.);
#1757=EDGE_LOOP('',(#1752,#1753,#1755,#1756));
#1758=FACE_BOUND('',#1757,.T.);
#1759=ADVANCED_FACE('F676',(#1758),#1751,.F.);
#1760=ORIENTED_EDGE('',*,*,#1754,.F.);
#1761=ORIENTED_EDGE('',*,*,#886,.T.);
#1762=EDGE_CURVE('E1062',#879,#69,#1648,.T.);
#1763=ORIENTED_EDGE('',*,*,#1762,.T.);
#1764=ORIENTED_EDGE('',*,*,#70,.F.);
#1765=EDGE_LOOP('',(#1760,#1761,#1763,#1764));
#1766=FACE_BOUND('',#1765,.T.);
#1767=ADVANCED_FACE('F683',(#1766),#1643,.T.);
#1768=CARTESIAN_POINT('',(3.1,11.875,0.));
#1769=DIRECTION('',(0.,1.,0.));
#1770=DIRECTION('',(0.,0.,1.));
#1771=AXIS2_PLACEMENT_3D('',#1768,#1769,#1770);
#1772=PLANE('',#1771);
#1773=ORIENTED_EDGE('',*,*,#1762,.F.);
#1774=ORIENTED_EDGE('',*,*,#880,.T.);
#1775=ORIENTED_EDGE('',*,*,#1649,.F.);
#1776=ORIENTED_EDGE('',*,*,#76,.F.);
#1777=EDGE_LOOP('',(#1773,#1774,#1775,#1776));
#1778=FACE_BOUND('',#1777,.T.);
#1779=ADVANCED_FACE('F702',(#1778),#1772,.F.);
#1780=CARTESIAN_POINT('',(-15.6127450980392,0.,0.));
#1781=DIRECTION('',(-1.,0.,0.));
#1782=DIRECTION('',(0.,-1.,0.));
#1783=AXIS2_PLACEMENT_3D('',#1780,#1781,#1782);
#1784=CYLINDRICAL_SURFACE('',#1783,17.5);
#1785=CARTESIAN_POINT('',(5.70000000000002,0.,0.));
#1786=DIRECTION('',(1.,0.,0.));
#1787=DIRECTION('',(0.,1.,0.));
#1788=AXIS2_PLACEMENT_3D('',#1785,#1786,#1787);
#1789=CIRCLE('',#1788,17.5);
#1790=CARTESIAN_POINT('',(5.70000000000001,17.5,0.));
#1791=VERTEX_POINT('',#1790);
#1792=EDGE_CURVE('E656',#1791,#1791,#1789,.F.);
#1793=ORIENTED_EDGE('',*,*,#1792,.T.);
#1794=EDGE_LOOP('',(#1793));
#1795=FACE_BOUND('',#1794,.T.);
#1796=CARTESIAN_POINT('',(3.3,0.,0.));
#1797=DIRECTION('',(-1.,0.,0.));
#1798=DIRECTION('',(0.,-1.,0.));
#1799=AXIS2_PLACEMENT_3D('',#1796,#1797,#1798);
#1800=CIRCLE('',#1799,17.5);
#1801=CARTESIAN_POINT('',(3.3,-17.5,0.));
#1802=VERTEX_POINT('',#1801);
#1803=EDGE_CURVE('E653',#1802,#1802,#1800,.F.);
#1804=ORIENTED_EDGE('',*,*,#1803,.T.);
#1805=EDGE_LOOP('',(#1804));
#1806=FACE_BOUND('',#1805,.T.);
#1807=ADVANCED_FACE('F706',(#1795,#1806),#1784,.T.);
#1808=CARTESIAN_POINT('',(6.00000000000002,-17.5,0.));
#1809=DIRECTION('',(1.,0.,0.));
#1810=DIRECTION('',(0.,1.,0.));
#1811=AXIS2_PLACEMENT_3D('',#1808,#1809,#1810);
#1812=PLANE('',#1811);
#1813=CARTESIAN_POINT('',(6.00000000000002,0.,0.));
#1814=DIRECTION('',(1.,0.,0.));
#1815=DIRECTION('',(0.,1.,0.));
#1816=AXIS2_PLACEMENT_3D('',#1813,#1814,#1815);
#1817=CIRCLE('',#1816,10.8);
#1818=CARTESIAN_POINT('',(6.00000000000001,10.8,0.));
#1819=VERTEX_POINT('',#1818);
#1820=EDGE_CURVE('E638',#1819,#1819,#1817,.F.);
#1821=ORIENTED_EDGE('',*,*,#1820,.T.);
#1822=EDGE_LOOP('',(#1821));
#1823=FACE_BOUND('',#1822,.T.);
#1824=CARTESIAN_POINT('',(6.00000000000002,0.,0.));
#1825=DIRECTION('',(1.,0.,0.));
#1826=DIRECTION('',(0.,1.,0.));
#1827=AXIS2_PLACEMENT_3D('',#1824,#1825,#1826);
#1828=CIRCLE('',#1827,17.2);
#1829=CARTESIAN_POINT('',(6.00000000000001,17.2,0.));
#1830=VERTEX_POINT('',#1829);
#1831=EDGE_CURVE('E635',#1830,#1830,#1828,.T.);
#1832=ORIENTED_EDGE('',*,*,#1831,.T.);
#1833=EDGE_LOOP('',(#1832));
#1834=FACE_BOUND('',#1833,.T.);
#1835=ADVANCED_FACE('F710',(#1823,#1834),#1812,.T.);
#1836=CARTESIAN_POINT('',(-15.6127450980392,0.,0.));
#1837=DIRECTION('',(-1.,0.,0.));
#1838=DIRECTION('',(0.,-1.,0.));
#1839=AXIS2_PLACEMENT_3D('',#1836,#1837,#1838);
#1840=CYLINDRICAL_SURFACE('',#1839,10.5);
#1841=CARTESIAN_POINT('',(3.3,0.,0.));
#1842=DIRECTION('',(-1.,0.,0.));
#1843=DIRECTION('',(0.,-1.,0.));
#1844=AXIS2_PLACEMENT_3D('',#1841,#1842,#1843);
#1845=CIRCLE('',#1844,10.5);
#1846=CARTESIAN_POINT('',(3.3,-10.5,0.));
#1847=VERTEX_POINT('',#1846);
#1848=EDGE_CURVE('E626',#1847,#1847,#1845,.T.);
#1849=ORIENTED_EDGE('',*,*,#1848,.T.);
#1850=EDGE_LOOP('',(#1849));
#1851=FACE_BOUND('',#1850,.T.);
#1852=CARTESIAN_POINT('',(5.70000000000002,0.,0.));
#1853=DIRECTION('',(1.,0.,0.));
#1854=DIRECTION('',(0.,1.,0.));
#1855=AXIS2_PLACEMENT_3D('',#1852,#1853,#1854);
#1856=CIRCLE('',#1855,10.5);
#1857=CARTESIAN_POINT('',(5.70000000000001,10.5,0.));
#1858=VERTEX_POINT('',#1857);
#1859=EDGE_CURVE('E620',#1858,#1858,#1856,.T.);
#1860=ORIENTED_EDGE('',*,*,#1859,.T.);
#1861=EDGE_LOOP('',(#1860));
#1862=FACE_BOUND('',#1861,.T.);
#1863=ADVANCED_FACE('F714',(#1851,#1862),#1840,.F.);
#1864=CARTESIAN_POINT('',(1.5,15.9325644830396,4.46409521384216));
#1865=DIRECTION('',(0.,0.962917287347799,0.269796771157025));
#1866=DIRECTION('',(0.,-0.269796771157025,0.962917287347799));
#1867=AXIS2_PLACEMENT_3D('',#1864,#1865,#1866);
#1868=CYLINDRICAL_SURFACE('',#1867,1.6);
#1869=ORIENTED_EDGE('',*,*,#104,.F.);
#1870=CARTESIAN_POINT('',(1.5,15.0455826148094,4.21557454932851));
#1871=DIRECTION('',(0.,0.962917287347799,0.269796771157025));
#1872=DIRECTION('',(0.,-0.269796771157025,0.962917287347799));
#1873=AXIS2_PLACEMENT_3D('',#1870,#1871,#1872);
#1874=CIRCLE('',#1873,1.6);
#1875=EDGE_CURVE('E1746',#897,#95,#1874,.T.);
#1876=ORIENTED_EDGE('',*,*,#1875,.F.);
#1877=ORIENTED_EDGE('',*,*,#898,.F.);
#1878=CARTESIAN_POINT('',(1.5,11.4346427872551,3.20383665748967));
#1879=DIRECTION('',(0.,0.962917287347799,0.269796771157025));
#1880=DIRECTION('',(0.,-0.269796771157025,0.962917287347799));
#1881=AXIS2_PLACEMENT_3D('',#1878,#1879,#1880);
#1882=CIRCLE('',#1881,1.6);
#1883=EDGE_CURVE('E1742',#895,#103,#1882,.T.);
#1884=ORIENTED_EDGE('',*,*,#1883,.T.);
#1885=EDGE_LOOP('',(#1869,#1876,#1877,#1884));
#1886=FACE_BOUND('',#1885,.T.);
#1887=ADVANCED_FACE('F717',(#1886),#1868,.T.);
#1888=CARTESIAN_POINT('',(1.5,15.0455826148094,4.21557454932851));
#1889=DIRECTION('',(0.,-0.962917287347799,-0.269796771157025));
#1890=DIRECTION('',(0.,0.269796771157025,-0.962917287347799));
#1891=AXIS2_PLACEMENT_3D('',#1888,#1889,#1890);
#1892=PLANE('',#1891);
#1893=ORIENTED_EDGE('',*,*,#96,.F.);
#1894=EDGE_CURVE('E1743',#87,#905,#1874,.T.);
#1895=ORIENTED_EDGE('',*,*,#1894,.T.);
#1896=ORIENTED_EDGE('',*,*,#906,.F.);
#1897=ORIENTED_EDGE('',*,*,#1875,.T.);
#1898=EDGE_LOOP('',(#1893,#1895,#1896,#1897));
#1899=FACE_BOUND('',#1898,.T.);
#1900=ADVANCED_FACE('F720',(#1899),#1892,.F.);
#1901=ORIENTED_EDGE('',*,*,#88,.F.);
#1902=EDGE_CURVE('E1739',#85,#913,#1882,.T.);
#1903=ORIENTED_EDGE('',*,*,#1902,.T.);
#1904=ORIENTED_EDGE('',*,*,#914,.F.);
#1905=ORIENTED_EDGE('',*,*,#1894,.F.);
#1906=EDGE_LOOP('',(#1901,#1903,#1904,#1905));
#1907=FACE_BOUND('',#1906,.T.);
#1908=ADVANCED_FACE('F723',(#1907),#1868,.T.);
#1909=CARTESIAN_POINT('',(3.1,11.4346427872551,3.20383665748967));
#1910=DIRECTION('',(0.,0.962917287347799,0.269796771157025));
#1911=DIRECTION('',(0.,-0.269796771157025,0.962917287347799));
#1912=AXIS2_PLACEMENT_3D('',#1909,#1910,#1911);
#1913=PLANE('',#1912);
#1914=ORIENTED_EDGE('',*,*,#110,.F.);
#1915=ORIENTED_EDGE('',*,*,#1883,.F.);
#1916=ORIENTED_EDGE('',*,*,#920,.F.);
#1917=ORIENTED_EDGE('',*,*,#1902,.F.);
#1918=EDGE_LOOP('',(#1914,#1915,#1916,#1917));
#1919=FACE_BOUND('',#1918,.T.);
#1920=ADVANCED_FACE('F727',(#1919),#1913,.F.);
#1921=CARTESIAN_POINT('',(1.5,14.1373432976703,8.59710890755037));
#1922=DIRECTION('',(0.,0.854419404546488,0.519583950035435));
#1923=DIRECTION('',(0.,-0.519583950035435,0.854419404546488));
#1924=AXIS2_PLACEMENT_3D('',#1921,#1922,#1923);
#1925=CYLINDRICAL_SURFACE('',#1924,1.6);
#1926=ORIENTED_EDGE('',*,*,#138,.F.);
#1927=CARTESIAN_POINT('',(1.5,13.3503031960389,8.11849921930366));
#1928=DIRECTION('',(0.,0.854419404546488,0.519583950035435));
#1929=DIRECTION('',(0.,-0.519583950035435,0.854419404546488));
#1930=AXIS2_PLACEMENT_3D('',#1927,#1928,#1929);
#1931=CIRCLE('',#1930,1.6);
#1932=EDGE_CURVE('E1726',#931,#129,#1931,.T.);
#1933=ORIENTED_EDGE('',*,*,#1932,.F.);
#1934=ORIENTED_EDGE('',*,*,#932,.F.);
#1935=CARTESIAN_POINT('',(1.5,10.1462304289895,6.17005940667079));
#1936=DIRECTION('',(0.,0.854419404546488,0.519583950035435));
#1937=DIRECTION('',(0.,-0.519583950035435,0.854419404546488));
#1938=AXIS2_PLACEMENT_3D('',#1935,#1936,#1937);
#1939=CIRCLE('',#1938,1.6);
#1940=EDGE_CURVE('E1722',#929,#137,#1939,.T.);
#1941=ORIENTED_EDGE('',*,*,#1940,.T.);
#1942=EDGE_LOOP('',(#1926,#1933,#1934,#1941));
#1943=FACE_BOUND('',#1942,.T.);
#1944=ADVANCED_FACE('F731',(#1943),#1925,.T.);
#1945=CARTESIAN_POINT('',(1.5,13.3503031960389,8.11849921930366));
#1946=DIRECTION('',(0.,-0.854419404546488,-0.519583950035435));
#1947=DIRECTION('',(0.,0.519583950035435,-0.854419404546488));
#1948=AXIS2_PLACEMENT_3D('',#1945,#1946,#1947);
#1949=PLANE('',#1948);
#1950=ORIENTED_EDGE('',*,*,#130,.F.);
#1951=EDGE_CURVE('E1723',#121,#939,#1931,.T.);
#1952=ORIENTED_EDGE('',*,*,#1951,.T.);
#1953=ORIENTED_EDGE('',*,*,#940,.F.);
#1954=ORIENTED_EDGE('',*,*,#1932,.T.);
#1955=EDGE_LOOP('',(#1950,#1952,#1953,#1954));
#1956=FACE_BOUND('',#1955,.T.);
#1957=ADVANCED_FACE('F733',(#1956),#1949,.F.);
#1958=ORIENTED_EDGE('',*,*,#122,.F.);
#1959=EDGE_CURVE('E1719',#119,#947,#1939,.T.);
#1960=ORIENTED_EDGE('',*,*,#1959,.T.);
#1961=ORIENTED_EDGE('',*,*,#948,.F.);
#1962=ORIENTED_EDGE('',*,*,#1951,.F.);
#1963=EDGE_LOOP('',(#1958,#1960,#1961,#1962));
#1964=FACE_BOUND('',#1963,.T.);
#1965=ADVANCED_FACE('F736',(#1964),#1925,.T.);
#1966=CARTESIAN_POINT('',(3.1,10.1462304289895,6.17005940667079));
#1967=DIRECTION('',(0.,0.854419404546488,0.519583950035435));
#1968=DIRECTION('',(0.,-0.519583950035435,0.854419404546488));
#1969=AXIS2_PLACEMENT_3D('',#1966,#1967,#1968);
#1970=PLANE('',#1969);
#1971=ORIENTED_EDGE('',*,*,#144,.F.);
#1972=ORIENTED_EDGE('',*,*,#1940,.F.);
#1973=ORIENTED_EDGE('',*,*,#954,.F.);
#1974=ORIENTED_EDGE('',*,*,#1959,.F.);
#1975=EDGE_LOOP('',(#1971,#1972,#1973,#1974));
#1976=FACE_BOUND('',#1975,.T.);
#1977=ADVANCED_FACE('F740',(#1976),#1970,.F.);
#1978=CARTESIAN_POINT('',(1.5,11.2936200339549,12.0925143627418));
#1979=DIRECTION('',(0.,0.682553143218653,0.730835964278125));
#1980=DIRECTION('',(0.,-0.730835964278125,0.682553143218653));
#1981=AXIS2_PLACEMENT_3D('',#1978,#1979,#1980);
#1982=CYLINDRICAL_SURFACE('',#1981,1.6);
#1983=ORIENTED_EDGE('',*,*,#172,.F.);
#1984=CARTESIAN_POINT('',(1.5,10.6648928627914,11.4193119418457));
#1985=DIRECTION('',(0.,0.682553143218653,0.730835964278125));
#1986=DIRECTION('',(0.,-0.730835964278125,0.682553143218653));
#1987=AXIS2_PLACEMENT_3D('',#1984,#1985,#1986);
#1988=CIRCLE('',#1987,1.6);
#1989=EDGE_CURVE('E1706',#965,#163,#1988,.T.);
#1990=ORIENTED_EDGE('',*,*,#1989,.F.);
#1991=ORIENTED_EDGE('',*,*,#966,.F.);
#1992=CARTESIAN_POINT('',(1.5,8.1053185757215,8.67867707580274));
#1993=DIRECTION('',(0.,0.682553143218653,0.730835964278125));
#1994=DIRECTION('',(0.,-0.730835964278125,0.682553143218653));
#1995=AXIS2_PLACEMENT_3D('',#1992,#1993,#1994);
#1996=CIRCLE('',#1995,1.6);
#1997=EDGE_CURVE('E1702',#963,#171,#1996,.T.);
#1998=ORIENTED_EDGE('',*,*,#1997,.T.);
#1999=EDGE_LOOP('',(#1983,#1990,#1991,#1998));
#2000=FACE_BOUND('',#1999,.T.);
#2001=ADVANCED_FACE('F744',(#2000),#1982,.T.);
#2002=CARTESIAN_POINT('',(1.5,10.6648928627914,11.4193119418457));
#2003=DIRECTION('',(0.,-0.682553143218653,-0.730835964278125));
#2004=DIRECTION('',(0.,0.730835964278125,-0.682553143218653));
#2005=AXIS2_PLACEMENT_3D('',#2002,#2003,#2004);
#2006=PLANE('',#2005);
#2007=ORIENTED_EDGE('',*,*,#164,.F.);
#2008=EDGE_CURVE('E1703',#155,#973,#1988,.T.);
#2009=ORIENTED_EDGE('',*,*,#2008,.T.);
#2010=ORIENTED_EDGE('',*,*,#974,.F.);
#2011=ORIENTED_EDGE('',*,*,#1989,.T.);
#2012=EDGE_LOOP('',(#2007,#2009,#2010,#2011));
#2013=FACE_BOUND('',#2012,.T.);
#2014=ADVANCED_FACE('F746',(#2013),#2006,.F.);
#2015=ORIENTED_EDGE('',*,*,#156,.F.);
#2016=EDGE_CURVE('E1699',#153,#981,#1996,.T.);
#2017=ORIENTED_EDGE('',*,*,#2016,.T.);
#2018=ORIENTED_EDGE('',*,*,#982,.F.);
#2019=ORIENTED_EDGE('',*,*,#2008,.F.);
#2020=EDGE_LOOP('',(#2015,#2017,#2018,#2019));
#2021=FACE_BOUND('',#2020,.T.);
#2022=ADVANCED_FACE('F749',(#2021),#1982,.T.);
#2023=CARTESIAN_POINT('',(3.1,8.1053185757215,8.67867707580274));
#2024=DIRECTION('',(0.,0.682553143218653,0.730835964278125));
#2025=DIRECTION('',(0.,-0.730835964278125,0.682553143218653));
#2026=AXIS2_PLACEMENT_3D('',#2023,#2024,#2025);
#2027=PLANE('',#2026);
#2028=ORIENTED_EDGE('',*,*,#178,.F.);
#2029=ORIENTED_EDGE('',*,*,#1997,.F.);
#2030=ORIENTED_EDGE('',*,*,#988,.F.);
#2031=ORIENTED_EDGE('',*,*,#2016,.F.);
#2032=EDGE_LOOP('',(#2028,#2029,#2030,#2031));
#2033=FACE_BOUND('',#2032,.T.);
#2034=ADVANCED_FACE('F753',(#2033),#2027,.F.);
#2035=CARTESIAN_POINT('',(1.5,7.61230063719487,14.691073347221));
#2036=DIRECTION('',(0.,0.46006503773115,0.887885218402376));
#2037=DIRECTION('',(0.,-0.887885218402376,0.46006503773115));
#2038=AXIS2_PLACEMENT_3D('',#2035,#2036,#2037);
#2039=CYLINDRICAL_SURFACE('',#2038,1.6);
#2040=ORIENTED_EDGE('',*,*,#206,.F.);
#2041=CARTESIAN_POINT('',(1.5,7.18851621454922,13.8732065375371));
#2042=DIRECTION('',(0.,0.46006503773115,0.887885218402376));
#2043=DIRECTION('',(0.,-0.887885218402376,0.46006503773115));
#2044=AXIS2_PLACEMENT_3D('',#2041,#2042,#2043);
#2045=CIRCLE('',#2044,1.6);
#2046=EDGE_CURVE('E1686',#999,#197,#2045,.T.);
#2047=ORIENTED_EDGE('',*,*,#2046,.F.);
#2048=ORIENTED_EDGE('',*,*,#1000,.F.);
#2049=CARTESIAN_POINT('',(1.5,5.46327232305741,10.5436369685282));
#2050=DIRECTION('',(0.,0.46006503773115,0.887885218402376));
#2051=DIRECTION('',(0.,-0.887885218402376,0.46006503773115));
#2052=AXIS2_PLACEMENT_3D('',#2049,#2050,#2051);
#2053=CIRCLE('',#2052,1.6);
#2054=EDGE_CURVE('E1682',#997,#205,#2053,.T.);
#2055=ORIENTED_EDGE('',*,*,#2054,.T.);
#2056=EDGE_LOOP('',(#2040,#2047,#2048,#2055));
#2057=FACE_BOUND('',#2056,.T.);
#2058=ADVANCED_FACE('F757',(#2057),#2039,.T.);
#2059=CARTESIAN_POINT('',(1.5,7.18851621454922,13.8732065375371));
#2060=DIRECTION('',(0.,-0.46006503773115,-0.887885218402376));
#2061=DIRECTION('',(0.,0.887885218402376,-0.46006503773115));
#2062=AXIS2_PLACEMENT_3D('',#2059,#2060,#2061);
#2063=PLANE('',#2062);
#2064=ORIENTED_EDGE('',*,*,#198,.F.);
#2065=EDGE_CURVE('E1683',#189,#1007,#2045,.T.);
#2066=ORIENTED_EDGE('',*,*,#2065,.T.);
#2067=ORIENTED_EDGE('',*,*,#1008,.F.);
#2068=ORIENTED_EDGE('',*,*,#2046,.T.);
#2069=EDGE_LOOP('',(#2064,#2066,#2067,#2068));
#2070=FACE_BOUND('',#2069,.T.);
#2071=ADVANCED_FACE('F759',(#2070),#2063,.F.);
#2072=ORIENTED_EDGE('',*,*,#190,.F.);
#2073=EDGE_CURVE('E1679',#187,#1015,#2053,.T.);
#2074=ORIENTED_EDGE('',*,*,#2073,.T.);
#2075=ORIENTED_EDGE('',*,*,#1016,.F.);
#2076=ORIENTED_EDGE('',*,*,#2065,.F.);
#2077=EDGE_LOOP('',(#2072,#2074,#2075,#2076));
#2078=FACE_BOUND('',#2077,.T.);
#2079=ADVANCED_FACE('F762',(#2078),#2039,.T.);
#2080=CARTESIAN_POINT('',(3.1,5.46327232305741,10.5436369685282));
#2081=DIRECTION('',(0.,0.46006503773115,0.887885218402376));
#2082=DIRECTION('',(0.,-0.887885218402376,0.46006503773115));
#2083=AXIS2_PLACEMENT_3D('',#2080,#2081,#2082);
#2084=PLANE('',#2083);
#2085=ORIENTED_EDGE('',*,*,#212,.F.);
#2086=ORIENTED_EDGE('',*,*,#2054,.F.);
#2087=ORIENTED_EDGE('',*,*,#1022,.F.);
#2088=ORIENTED_EDGE('',*,*,#2073,.F.);
#2089=EDGE_LOOP('',(#2085,#2086,#2087,#2088));
#2090=FACE_BOUND('',#2089,.T.);
#2091=ADVANCED_FACE('F766',(#2090),#2084,.F.);
#2092=CARTESIAN_POINT('',(1.5,3.36641172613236,16.2000626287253));
#2093=DIRECTION('',(0.,0.203456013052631,0.979084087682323));
#2094=DIRECTION('',(0.,-0.979084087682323,0.203456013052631));
#2095=AXIS2_PLACEMENT_3D('',#2092,#2093,#2094);
#2096=CYLINDRICAL_SURFACE('',#2095,1.6);
#2097=ORIENTED_EDGE('',*,*,#240,.F.);
#2098=CARTESIAN_POINT('',(1.5,3.17900020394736,15.2981888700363));
#2099=DIRECTION('',(0.,0.203456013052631,0.979084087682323));
#2100=DIRECTION('',(0.,-0.979084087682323,0.203456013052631));
#2101=AXIS2_PLACEMENT_3D('',#2098,#2099,#2100);
#2102=CIRCLE('',#2101,1.6);
#2103=EDGE_CURVE('E1666',#1033,#231,#2102,.T.);
#2104=ORIENTED_EDGE('',*,*,#2103,.F.);
#2105=ORIENTED_EDGE('',*,*,#1034,.F.);
#2106=CARTESIAN_POINT('',(1.5,2.41604015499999,11.6266235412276));
#2107=DIRECTION('',(0.,0.203456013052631,0.979084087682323));
#2108=DIRECTION('',(0.,-0.979084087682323,0.203456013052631));
#2109=AXIS2_PLACEMENT_3D('',#2106,#2107,#2108);
#2110=CIRCLE('',#2109,1.6);
#2111=EDGE_CURVE('E1662',#1031,#239,#2110,.T.);
#2112=ORIENTED_EDGE('',*,*,#2111,.T.);
#2113=EDGE_LOOP('',(#2097,#2104,#2105,#2112));
#2114=FACE_BOUND('',#2113,.T.);
#2115=ADVANCED_FACE('F770',(#2114),#2096,.T.);
#2116=CARTESIAN_POINT('',(1.5,3.17900020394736,15.2981888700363));
#2117=DIRECTION('',(0.,-0.203456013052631,-0.979084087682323));
#2118=DIRECTION('',(0.,0.979084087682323,-0.203456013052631));
#2119=AXIS2_PLACEMENT_3D('',#2116,#2117,#2118);
#2120=PLANE('',#2119);
#2121=ORIENTED_EDGE('',*,*,#232,.F.);
#2122=EDGE_CURVE('E1663',#223,#1041,#2102,.T.);
#2123=ORIENTED_EDGE('',*,*,#2122,.T.);
#2124=ORIENTED_EDGE('',*,*,#1042,.F.);
#2125=ORIENTED_EDGE('',*,*,#2103,.T.);
#2126=EDGE_LOOP('',(#2121,#2123,#2124,#2125));
#2127=FACE_BOUND('',#2126,.T.);
#2128=ADVANCED_FACE('F772',(#2127),#2120,.F.);
#2129=ORIENTED_EDGE('',*,*,#224,.F.);
#2130=EDGE_CURVE('E1659',#221,#1049,#2110,.T.);
#2131=ORIENTED_EDGE('',*,*,#2130,.T.);
#2132=ORIENTED_EDGE('',*,*,#1050,.F.);
#2133=ORIENTED_EDGE('',*,*,#2122,.F.);
#2134=EDGE_LOOP('',(#2129,#2131,#2132,#2133));
#2135=FACE_BOUND('',#2134,.T.);
#2136=ADVANCED_FACE('F775',(#2135),#2096,.T.);
#2137=CARTESIAN_POINT('',(3.1,2.41604015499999,11.6266235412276));
#2138=DIRECTION('',(0.,0.203456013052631,0.979084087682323));
#2139=DIRECTION('',(0.,-0.979084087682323,0.203456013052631));
#2140=AXIS2_PLACEMENT_3D('',#2137,#2138,#2139);
#2141=PLANE('',#2140);
#2142=ORIENTED_EDGE('',*,*,#246,.F.);
#2143=ORIENTED_EDGE('',*,*,#2111,.F.);
#2144=ORIENTED_EDGE('',*,*,#1056,.F.);
#2145=ORIENTED_EDGE('',*,*,#2130,.F.);
#2146=EDGE_LOOP('',(#2142,#2143,#2144,#2145));
#2147=FACE_BOUND('',#2146,.T.);
#2148=ADVANCED_FACE('F779',(#2147),#2141,.F.);
#2149=CARTESIAN_POINT('',(1.5,-1.12914854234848,16.5075673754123));
#2150=DIRECTION('',(0.,-0.0682424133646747,0.997668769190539));
#2151=DIRECTION('',(0.,-0.997668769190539,-0.0682424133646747));
#2152=AXIS2_PLACEMENT_3D('',#2149,#2150,#2151);
#2153=CYLINDRICAL_SURFACE('',#2152,1.6);
#2154=ORIENTED_EDGE('',*,*,#274,.F.);
#2155=CARTESIAN_POINT('',(1.5,-1.06628770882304,15.5885745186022));
#2156=DIRECTION('',(0.,-0.0682424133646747,0.997668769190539));
#2157=DIRECTION('',(0.,-0.997668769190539,-0.0682424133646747));
#2158=AXIS2_PLACEMENT_3D('',#2155,#2156,#2157);
#2159=CIRCLE('',#2158,1.6);
#2160=EDGE_CURVE('E1646',#1067,#265,#2159,.T.);
#2161=ORIENTED_EDGE('',*,*,#2160,.F.);
#2162=ORIENTED_EDGE('',*,*,#1068,.F.);
#2163=CARTESIAN_POINT('',(1.5,-0.810378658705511,11.8473166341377));
#2164=DIRECTION('',(0.,-0.0682424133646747,0.997668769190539));
#2165=DIRECTION('',(0.,-0.997668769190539,-0.0682424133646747));
#2166=AXIS2_PLACEMENT_3D('',#2163,#2164,#2165);
#2167=CIRCLE('',#2166,1.6);
#2168=EDGE_CURVE('E1642',#1065,#273,#2167,.T.);
#2169=ORIENTED_EDGE('',*,*,#2168,.T.);
#2170=EDGE_LOOP('',(#2154,#2161,#2162,#2169));
#2171=FACE_BOUND('',#2170,.T.);
#2172=ADVANCED_FACE('F783',(#2171),#2153,.T.);
#2173=CARTESIAN_POINT('',(1.5,-1.06628770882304,15.5885745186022));
#2174=DIRECTION('',(0.,0.0682424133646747,-0.997668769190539));
#2175=DIRECTION('',(0.,0.997668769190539,0.0682424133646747));
#2176=AXIS2_PLACEMENT_3D('',#2173,#2174,#2175);
#2177=PLANE('',#2176);
#2178=ORIENTED_EDGE('',*,*,#266,.F.);
#2179=EDGE_CURVE('E1643',#257,#1075,#2159,.T.);
#2180=ORIENTED_EDGE('',*,*,#2179,.T.);
#2181=ORIENTED_EDGE('',*,*,#1076,.F.);
#2182=ORIENTED_EDGE('',*,*,#2160,.T.);
#2183=EDGE_LOOP('',(#2178,#2180,#2181,#2182));
#2184=FACE_BOUND('',#2183,.T.);
#2185=ADVANCED_FACE('F785',(#2184),#2177,.F.);
#2186=ORIENTED_EDGE('',*,*,#258,.F.);
#2187=EDGE_CURVE('E1639',#255,#1083,#2167,.T.);
#2188=ORIENTED_EDGE('',*,*,#2187,.T.);
#2189=ORIENTED_EDGE('',*,*,#1084,.F.);
#2190=ORIENTED_EDGE('',*,*,#2179,.F.);
#2191=EDGE_LOOP('',(#2186,#2188,#2189,#2190));
#2192=FACE_BOUND('',#2191,.T.);
#2193=ADVANCED_FACE('F788',(#2192),#2153,.T.);
#2194=CARTESIAN_POINT('',(3.1,-0.810378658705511,11.8473166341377));
#2195=DIRECTION('',(0.,-0.0682424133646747,0.997668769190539));
#2196=DIRECTION('',(0.,-0.997668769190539,-0.0682424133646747));
#2197=AXIS2_PLACEMENT_3D('',#2194,#2195,#2196);
#2198=PLANE('',#2197);
#2199=ORIENTED_EDGE('',*,*,#280,.F.);
#2200=ORIENTED_EDGE('',*,*,#2168,.F.);
#2201=ORIENTED_EDGE('',*,*,#1090,.F.);
#2202=ORIENTED_EDGE('',*,*,#2187,.F.);
#2203=EDGE_LOOP('',(#2199,#2200,#2201,#2202));
#2204=FACE_BOUND('',#2203,.T.);
#2205=ADVANCED_FACE('F792',(#2204),#2198,.F.);
#2206=CARTESIAN_POINT('',(1.5,-5.54096502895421,15.5907813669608));
#2207=DIRECTION('',(0.,-0.33487961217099,0.942260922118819));
#2208=DIRECTION('',(0.,-0.942260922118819,-0.33487961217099));
#2209=AXIS2_PLACEMENT_3D('',#2206,#2207,#2208);
#2210=CYLINDRICAL_SURFACE('',#2209,1.6);
#2211=ORIENTED_EDGE('',*,*,#308,.F.);
#2212=CARTESIAN_POINT('',(1.5,-5.23249394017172,14.7228269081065));
#2213=DIRECTION('',(0.,-0.33487961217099,0.942260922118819));
#2214=DIRECTION('',(0.,-0.942260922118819,-0.33487961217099));
#2215=AXIS2_PLACEMENT_3D('',#2212,#2213,#2214);
#2216=CIRCLE('',#2215,1.6);
#2217=EDGE_CURVE('E1626',#1101,#299,#2216,.T.);
#2218=ORIENTED_EDGE('',*,*,#2217,.F.);
#2219=ORIENTED_EDGE('',*,*,#1102,.F.);
#2220=CARTESIAN_POINT('',(1.5,-3.97669539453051,11.189348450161));
#2221=DIRECTION('',(0.,-0.33487961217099,0.942260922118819));
#2222=DIRECTION('',(0.,-0.942260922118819,-0.33487961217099));
#2223=AXIS2_PLACEMENT_3D('',#2220,#2221,#2222);
#2224=CIRCLE('',#2223,1.6);
#2225=EDGE_CURVE('E1622',#1099,#307,#2224,.T.);
#2226=ORIENTED_EDGE('',*,*,#2225,.T.);
#2227=EDGE_LOOP('',(#2211,#2218,#2219,#2226));
#2228=FACE_BOUND('',#2227,.T.);
#2229=ADVANCED_FACE('F796',(#2228),#2210,.T.);
#2230=CARTESIAN_POINT('',(1.5,-5.23249394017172,14.7228269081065));
#2231=DIRECTION('',(0.,0.33487961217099,-0.942260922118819));
#2232=DIRECTION('',(0.,0.942260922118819,0.33487961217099));
#2233=AXIS2_PLACEMENT_3D('',#2230,#2231,#2232);
#2234=PLANE('',#2233);
#2235=ORIENTED_EDGE('',*,*,#300,.F.);
#2236=EDGE_CURVE('E1623',#291,#1109,#2216,.T.);
#2237=ORIENTED_EDGE('',*,*,#2236,.T.);
#2238=ORIENTED_EDGE('',*,*,#1110,.F.);
#2239=ORIENTED_EDGE('',*,*,#2217,.T.);
#2240=EDGE_LOOP('',(#2235,#2237,#2238,#2239));
#2241=FACE_BOUND('',#2240,.T.);
#2242=ADVANCED_FACE('F798',(#2241),#2234,.F.);
#2243=ORIENTED_EDGE('',*,*,#292,.F.);
#2244=EDGE_CURVE('E1619',#289,#1117,#2224,.T.);
#2245=ORIENTED_EDGE('',*,*,#2244,.T.);
#2246=ORIENTED_EDGE('',*,*,#1118,.F.);
#2247=ORIENTED_EDGE('',*,*,#2236,.F.);
#2248=EDGE_LOOP('',(#2243,#2245,#2246,#2247));
#2249=FACE_BOUND('',#2248,.T.);
#2250=ADVANCED_FACE('F801',(#2249),#2210,.T.);
#2251=CARTESIAN_POINT('',(3.1,-3.97669539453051,11.189348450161));
#2252=DIRECTION('',(0.,-0.33487961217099,0.942260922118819));
#2253=DIRECTION('',(0.,-0.942260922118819,-0.33487961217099));
#2254=AXIS2_PLACEMENT_3D('',#2251,#2252,#2253);
#2255=PLANE('',#2254);
#2256=ORIENTED_EDGE('',*,*,#314,.F.);
#2257=ORIENTED_EDGE('',*,*,#2225,.F.);
#2258=ORIENTED_EDGE('',*,*,#1124,.F.);
#2259=ORIENTED_EDGE('',*,*,#2244,.F.);
#2260=EDGE_LOOP('',(#2256,#2257,#2258,#2259));
#2261=FACE_BOUND('',#2260,.T.);
#2262=ADVANCED_FACE('F805',(#2261),#2255,.F.);
#2263=CARTESIAN_POINT('',(1.5,-9.54183348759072,13.5176984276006));
#2264=DIRECTION('',(0.,-0.576680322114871,0.816969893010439));
#2265=DIRECTION('',(0.,-0.816969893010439,-0.576680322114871));
#2266=AXIS2_PLACEMENT_3D('',#2263,#2264,#2265);
#2267=CYLINDRICAL_SURFACE('',#2266,1.6);
#2268=ORIENTED_EDGE('',*,*,#342,.F.);
#2269=CARTESIAN_POINT('',(1.5,-9.01063003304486,12.7651545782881));
#2270=DIRECTION('',(0.,-0.576680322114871,0.816969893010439));
#2271=DIRECTION('',(0.,-0.816969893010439,-0.576680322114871));
#2272=AXIS2_PLACEMENT_3D('',#2269,#2270,#2271);
#2273=CIRCLE('',#2272,1.6);
#2274=EDGE_CURVE('E1606',#1135,#333,#2273,.T.);
#2275=ORIENTED_EDGE('',*,*,#2274,.F.);
#2276=ORIENTED_EDGE('',*,*,#1136,.F.);
#2277=CARTESIAN_POINT('',(1.5,-6.84807882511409,9.70151747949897));
#2278=DIRECTION('',(0.,-0.576680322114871,0.816969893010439));
#2279=DIRECTION('',(0.,-0.816969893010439,-0.576680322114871));
#2280=AXIS2_PLACEMENT_3D('',#2277,#2278,#2279);
#2281=CIRCLE('',#2280,1.6);
#2282=EDGE_CURVE('E1602',#1133,#341,#2281,.T.);
#2283=ORIENTED_EDGE('',*,*,#2282,.T.);
#2284=EDGE_LOOP('',(#2268,#2275,#2276,#2283));
#2285=FACE_BOUND('',#2284,.T.);
#2286=ADVANCED_FACE('F809',(#2285),#2267,.T.);
#2287=CARTESIAN_POINT('',(1.5,-9.01063003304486,12.7651545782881));
#2288=DIRECTION('',(0.,0.576680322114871,-0.816969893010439));
#2289=DIRECTION('',(0.,0.816969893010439,0.576680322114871));
#2290=AXIS2_PLACEMENT_3D('',#2287,#2288,#2289);
#2291=PLANE('',#2290);
#2292=ORIENTED_EDGE('',*,*,#334,.F.);
#2293=EDGE_CURVE('E1603',#325,#1143,#2273,.T.);
#2294=ORIENTED_EDGE('',*,*,#2293,.T.);
#2295=ORIENTED_EDGE('',*,*,#1144,.F.);
#2296=ORIENTED_EDGE('',*,*,#2274,.T.);
#2297=EDGE_LOOP('',(#2292,#2294,#2295,#2296));
#2298=FACE_BOUND('',#2297,.T.);
#2299=ADVANCED_FACE('F811',(#2298),#2291,.F.);
#2300=ORIENTED_EDGE('',*,*,#326,.F.);
#2301=EDGE_CURVE('E1599',#323,#1151,#2281,.T.);
#2302=ORIENTED_EDGE('',*,*,#2301,.T.);
#2303=ORIENTED_EDGE('',*,*,#1152,.F.);
#2304=ORIENTED_EDGE('',*,*,#2293,.F.);
#2305=EDGE_LOOP('',(#2300,#2302,#2303,#2304));
#2306=FACE_BOUND('',#2305,.T.);
#2307=ADVANCED_FACE('F814',(#2306),#2267,.T.);
#2308=CARTESIAN_POINT('',(3.1,-6.84807882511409,9.70151747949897));
#2309=DIRECTION('',(0.,-0.576680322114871,0.816969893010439));
#2310=DIRECTION('',(0.,-0.816969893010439,-0.576680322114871));
#2311=AXIS2_PLACEMENT_3D('',#2308,#2309,#2310);
#2312=PLANE('',#2311);
#2313=ORIENTED_EDGE('',*,*,#348,.F.);
#2314=ORIENTED_EDGE('',*,*,#2282,.F.);
#2315=ORIENTED_EDGE('',*,*,#1158,.F.);
#2316=ORIENTED_EDGE('',*,*,#2301,.F.);
#2317=EDGE_LOOP('',(#2313,#2314,#2315,#2316));
#2318=FACE_BOUND('',#2317,.T.);
#2319=ADVANCED_FACE('F818',(#2318),#2312,.F.);
#2320=CARTESIAN_POINT('',(1.5,-12.8350278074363,10.4420696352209));
#2321=DIRECTION('',(0.,-0.775711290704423,0.631087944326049));
#2322=DIRECTION('',(0.,-0.631087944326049,-0.775711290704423));
#2323=AXIS2_PLACEMENT_3D('',#2320,#2321,#2322);
#2324=CYLINDRICAL_SURFACE('',#2323,1.6);
#2325=ORIENTED_EDGE('',*,*,#376,.F.);
#2326=CARTESIAN_POINT('',(1.5,-12.1204889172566,9.86074913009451));
#2327=DIRECTION('',(0.,-0.775711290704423,0.631087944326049));
#2328=DIRECTION('',(0.,-0.631087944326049,-0.775711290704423));
#2329=AXIS2_PLACEMENT_3D('',#2326,#2327,#2328);
#2330=CIRCLE('',#2329,1.6);
#2331=EDGE_CURVE('E1586',#1169,#367,#2330,.T.);
#2332=ORIENTED_EDGE('',*,*,#2331,.F.);
#2333=ORIENTED_EDGE('',*,*,#1170,.F.);
#2334=CARTESIAN_POINT('',(1.5,-9.21157157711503,7.49416933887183));
#2335=DIRECTION('',(0.,-0.775711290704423,0.631087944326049));
#2336=DIRECTION('',(0.,-0.631087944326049,-0.775711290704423));
#2337=AXIS2_PLACEMENT_3D('',#2334,#2335,#2336);
#2338=CIRCLE('',#2337,1.6);
#2339=EDGE_CURVE('E1582',#1167,#375,#2338,.T.);
#2340=ORIENTED_EDGE('',*,*,#2339,.T.);
#2341=EDGE_LOOP('',(#2325,#2332,#2333,#2340));
#2342=FACE_BOUND('',#2341,.T.);
#2343=ADVANCED_FACE('F822',(#2342),#2324,.T.);
#2344=CARTESIAN_POINT('',(1.5,-12.1204889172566,9.86074913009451));
#2345=DIRECTION('',(0.,0.775711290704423,-0.631087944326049));
#2346=DIRECTION('',(0.,0.631087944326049,0.775711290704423));
#2347=AXIS2_PLACEMENT_3D('',#2344,#2345,#2346);
#2348=PLANE('',#2347);
#2349=ORIENTED_EDGE('',*,*,#368,.F.);
#2350=EDGE_CURVE('E1583',#359,#1177,#2330,.T.);
#2351=ORIENTED_EDGE('',*,*,#2350,.T.);
#2352=ORIENTED_EDGE('',*,*,#1178,.F.);
#2353=ORIENTED_EDGE('',*,*,#2331,.T.);
#2354=EDGE_LOOP('',(#2349,#2351,#2352,#2353));
#2355=FACE_BOUND('',#2354,.T.);
#2356=ADVANCED_FACE('F824',(#2355),#2348,.F.);
#2357=ORIENTED_EDGE('',*,*,#360,.F.);
#2358=EDGE_CURVE('E1579',#357,#1185,#2338,.T.);
#2359=ORIENTED_EDGE('',*,*,#2358,.T.);
#2360=ORIENTED_EDGE('',*,*,#1186,.F.);
#2361=ORIENTED_EDGE('',*,*,#2350,.F.);
#2362=EDGE_LOOP('',(#2357,#2359,#2360,#2361));
#2363=FACE_BOUND('',#2362,.T.);
#2364=ADVANCED_FACE('F827',(#2363),#2324,.T.);
#2365=CARTESIAN_POINT('',(3.1,-9.21157157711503,7.49416933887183));
#2366=DIRECTION('',(0.,-0.775711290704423,0.631087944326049));
#2367=DIRECTION('',(0.,-0.631087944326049,-0.775711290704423));
#2368=AXIS2_PLACEMENT_3D('',#2365,#2366,#2367);
#2369=PLANE('',#2368);
#2370=ORIENTED_EDGE('',*,*,#382,.F.);
#2371=ORIENTED_EDGE('',*,*,#2339,.F.);
#2372=ORIENTED_EDGE('',*,*,#1192,.F.);
#2373=ORIENTED_EDGE('',*,*,#2358,.F.);
#2374=EDGE_LOOP('',(#2370,#2371,#2372,#2373));
#2375=FACE_BOUND('',#2374,.T.);
#2376=ADVANCED_FACE('F831',(#2375),#2369,.F.);
#2377=CARTESIAN_POINT('',(1.5,-15.1763068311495,6.59200030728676));
#2378=DIRECTION('',(0.,-0.917211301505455,0.398401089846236));
#2379=DIRECTION('',(0.,-0.398401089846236,-0.917211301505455));
#2380=AXIS2_PLACEMENT_3D('',#2377,#2378,#2379);
#2381=CYLINDRICAL_SURFACE('',#2380,1.6);
#2382=ORIENTED_EDGE('',*,*,#410,.F.);
#2383=CARTESIAN_POINT('',(1.5,-14.3314265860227,6.22501702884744));
#2384=DIRECTION('',(0.,-0.917211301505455,0.398401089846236));
#2385=DIRECTION('',(0.,-0.398401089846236,-0.917211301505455));
#2386=AXIS2_PLACEMENT_3D('',#2383,#2384,#2385);
#2387=CIRCLE('',#2386,1.6);
#2388=EDGE_CURVE('E1566',#1203,#401,#2387,.T.);
#2389=ORIENTED_EDGE('',*,*,#2388,.F.);
#2390=ORIENTED_EDGE('',*,*,#1204,.F.);
#2391=CARTESIAN_POINT('',(1.5,-10.8918842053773,4.73101294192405));
#2392=DIRECTION('',(0.,-0.917211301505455,0.398401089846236));
#2393=DIRECTION('',(0.,-0.398401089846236,-0.917211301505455));
#2394=AXIS2_PLACEMENT_3D('',#2391,#2392,#2393);
#2395=CIRCLE('',#2394,1.6);
#2396=EDGE_CURVE('E1562',#1201,#409,#2395,.T.);
#2397=ORIENTED_EDGE('',*,*,#2396,.T.);
#2398=EDGE_LOOP('',(#2382,#2389,#2390,#2397));
#2399=FACE_BOUND('',#2398,.T.);
#2400=ADVANCED_FACE('F835',(#2399),#2381,.T.);
#2401=CARTESIAN_POINT('',(1.5,-14.3314265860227,6.22501702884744));
#2402=DIRECTION('',(0.,0.917211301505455,-0.398401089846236));
#2403=DIRECTION('',(0.,0.398401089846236,0.917211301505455));
#2404=AXIS2_PLACEMENT_3D('',#2401,#2402,#2403);
#2405=PLANE('',#2404);
#2406=ORIENTED_EDGE('',*,*,#402,.F.);
#2407=EDGE_CURVE('E1563',#393,#1211,#2387,.T.);
#2408=ORIENTED_EDGE('',*,*,#2407,.T.);
#2409=ORIENTED_EDGE('',*,*,#1212,.F.);
#2410=ORIENTED_EDGE('',*,*,#2388,.T.);
#2411=EDGE_LOOP('',(#2406,#2408,#2409,#2410));
#2412=FACE_BOUND('',#2411,.T.);
#2413=ADVANCED_FACE('F837',(#2412),#2405,.F.);
#2414=ORIENTED_EDGE('',*,*,#394,.F.);
#2415=EDGE_CURVE('E1559',#391,#1219,#2395,.T.);
#2416=ORIENTED_EDGE('',*,*,#2415,.T.);
#2417=ORIENTED_EDGE('',*,*,#1220,.F.);
#2418=ORIENTED_EDGE('',*,*,#2407,.F.);
#2419=EDGE_LOOP('',(#2414,#2416,#2417,#2418));
#2420=FACE_BOUND('',#2419,.T.);
#2421=ADVANCED_FACE('F840',(#2420),#2381,.T.);
#2422=CARTESIAN_POINT('',(3.1,-10.8918842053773,4.73101294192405));
#2423=DIRECTION('',(0.,-0.917211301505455,0.398401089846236));
#2424=DIRECTION('',(0.,-0.398401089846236,-0.917211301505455));
#2425=AXIS2_PLACEMENT_3D('',#2422,#2423,#2424);
#2426=PLANE('',#2425);
#2427=ORIENTED_EDGE('',*,*,#416,.F.);
#2428=ORIENTED_EDGE('',*,*,#2396,.F.);
#2429=ORIENTED_EDGE('',*,*,#1226,.F.);
#2430=ORIENTED_EDGE('',*,*,#2415,.F.);
#2431=EDGE_LOOP('',(#2427,#2428,#2429,#2430));
#2432=FACE_BOUND('',#2431,.T.);
#2433=ADVANCED_FACE('F844',(#2432),#2426,.F.);
#2434=CARTESIAN_POINT('',(1.5,-16.3920286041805,2.25303247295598));
#2435=DIRECTION('',(0.,-0.990685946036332,0.13616664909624));
#2436=DIRECTION('',(0.,-0.13616664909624,-0.990685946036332));
#2437=AXIS2_PLACEMENT_3D('',#2434,#2435,#2436);
#2438=CYLINDRICAL_SURFACE('',#2437,1.6);
#2439=ORIENTED_EDGE('',*,*,#444,.F.);
#2440=CARTESIAN_POINT('',(1.5,-15.4794679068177,2.12760389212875));
#2441=DIRECTION('',(0.,-0.990685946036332,0.13616664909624));
#2442=DIRECTION('',(0.,-0.13616664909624,-0.990685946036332));
#2443=AXIS2_PLACEMENT_3D('',#2440,#2441,#2442);
#2444=CIRCLE('',#2443,1.6);
#2445=EDGE_CURVE('E1546',#1237,#435,#2444,.T.);
#2446=ORIENTED_EDGE('',*,*,#2445,.F.);
#2447=ORIENTED_EDGE('',*,*,#1238,.F.);
#2448=CARTESIAN_POINT('',(1.5,-11.7643956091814,1.61697895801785));
#2449=DIRECTION('',(0.,-0.990685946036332,0.13616664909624));
#2450=DIRECTION('',(0.,-0.13616664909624,-0.990685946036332));
#2451=AXIS2_PLACEMENT_3D('',#2448,#2449,#2450);
#2452=CIRCLE('',#2451,1.6);
#2453=EDGE_CURVE('E1542',#1235,#443,#2452,.T.);
#2454=ORIENTED_EDGE('',*,*,#2453,.T.);
#2455=EDGE_LOOP('',(#2439,#2446,#2447,#2454));
#2456=FACE_BOUND('',#2455,.T.);
#2457=ADVANCED_FACE('F848',(#2456),#2438,.T.);
#2458=CARTESIAN_POINT('',(1.5,-15.4794679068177,2.12760389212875));
#2459=DIRECTION('',(0.,0.990685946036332,-0.13616664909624));
#2460=DIRECTION('',(0.,0.13616664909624,0.990685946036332));
#2461=AXIS2_PLACEMENT_3D('',#2458,#2459,#2460);
#2462=PLANE('',#2461);
#2463=ORIENTED_EDGE('',*,*,#436,.F.);
#2464=EDGE_CURVE('E1543',#427,#1245,#2444,.T.);
#2465=ORIENTED_EDGE('',*,*,#2464,.T.);
#2466=ORIENTED_EDGE('',*,*,#1246,.F.);
#2467=ORIENTED_EDGE('',*,*,#2445,.T.);
#2468=EDGE_LOOP('',(#2463,#2465,#2466,#2467));
#2469=FACE_BOUND('',#2468,.T.);
#2470=ADVANCED_FACE('F850',(#2469),#2462,.F.);
#2471=ORIENTED_EDGE('',*,*,#428,.F.);
#2472=EDGE_CURVE('E1539',#425,#1253,#2452,.T.);
#2473=ORIENTED_EDGE('',*,*,#2472,.T.);
#2474=ORIENTED_EDGE('',*,*,#1254,.F.);
#2475=ORIENTED_EDGE('',*,*,#2464,.F.);
#2476=EDGE_LOOP('',(#2471,#2473,#2474,#2475));
#2477=FACE_BOUND('',#2476,.T.);
#2478=ADVANCED_FACE('F853',(#2477),#2438,.T.);
#2479=CARTESIAN_POINT('',(3.1,-11.7643956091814,1.61697895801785));
#2480=DIRECTION('',(0.,-0.990685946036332,0.13616664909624));
#2481=DIRECTION('',(0.,-0.13616664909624,-0.990685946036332));
#2482=AXIS2_PLACEMENT_3D('',#2479,#2480,#2481);
#2483=PLANE('',#2482);
#2484=ORIENTED_EDGE('',*,*,#450,.F.);
#2485=ORIENTED_EDGE('',*,*,#2453,.F.);
#2486=ORIENTED_EDGE('',*,*,#1260,.F.);
#2487=ORIENTED_EDGE('',*,*,#2472,.F.);
#2488=EDGE_LOOP('',(#2484,#2485,#2486,#2487));
#2489=FACE_BOUND('',#2488,.T.);
#2490=ADVANCED_FACE('F857',(#2489),#2483,.F.);
#2491=CARTESIAN_POINT('',(1.5,-16.3920286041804,-2.25303247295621));
#2492=DIRECTION('',(0.,-0.99068594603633,-0.136166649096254));
#2493=DIRECTION('',(0.,0.136166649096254,-0.99068594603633));
#2494=AXIS2_PLACEMENT_3D('',#2491,#2492,#2493);
#2495=CYLINDRICAL_SURFACE('',#2494,1.6);
#2496=ORIENTED_EDGE('',*,*,#478,.F.);
#2497=CARTESIAN_POINT('',(1.5,-15.4794679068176,-2.12760389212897));
#2498=DIRECTION('',(0.,-0.99068594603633,-0.136166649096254));
#2499=DIRECTION('',(0.,0.136166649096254,-0.99068594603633));
#2500=AXIS2_PLACEMENT_3D('',#2497,#2498,#2499);
#2501=CIRCLE('',#2500,1.6);
#2502=EDGE_CURVE('E1526',#1271,#469,#2501,.T.);
#2503=ORIENTED_EDGE('',*,*,#2502,.F.);
#2504=ORIENTED_EDGE('',*,*,#1272,.F.);
#2505=CARTESIAN_POINT('',(1.5,-11.7643956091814,-1.61697895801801));
#2506=DIRECTION('',(0.,-0.99068594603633,-0.136166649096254));
#2507=DIRECTION('',(0.,0.136166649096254,-0.99068594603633));
#2508=AXIS2_PLACEMENT_3D('',#2505,#2506,#2507);
#2509=CIRCLE('',#2508,1.6);
#2510=EDGE_CURVE('E1522',#1269,#477,#2509,.T.);
#2511=ORIENTED_EDGE('',*,*,#2510,.T.);
#2512=EDGE_LOOP('',(#2496,#2503,#2504,#2511));
#2513=FACE_BOUND('',#2512,.T.);
#2514=ADVANCED_FACE('F861',(#2513),#2495,.T.);
#2515=CARTESIAN_POINT('',(1.5,-15.4794679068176,-2.12760389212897));
#2516=DIRECTION('',(0.,0.99068594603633,0.136166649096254));
#2517=DIRECTION('',(0.,-0.136166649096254,0.99068594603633));
#2518=AXIS2_PLACEMENT_3D('',#2515,#2516,#2517);
#2519=PLANE('',#2518);
#2520=ORIENTED_EDGE('',*,*,#470,.F.);
#2521=EDGE_CURVE('E1523',#461,#1279,#2501,.T.);
#2522=ORIENTED_EDGE('',*,*,#2521,.T.);
#2523=ORIENTED_EDGE('',*,*,#1280,.F.);
#2524=ORIENTED_EDGE('',*,*,#2502,.T.);
#2525=EDGE_LOOP('',(#2520,#2522,#2523,#2524));
#2526=FACE_BOUND('',#2525,.T.);
#2527=ADVANCED_FACE('F863',(#2526),#2519,.F.);
#2528=ORIENTED_EDGE('',*,*,#462,.F.);
#2529=EDGE_CURVE('E1519',#459,#1287,#2509,.T.);
#2530=ORIENTED_EDGE('',*,*,#2529,.T.);
#2531=ORIENTED_EDGE('',*,*,#1288,.F.);
#2532=ORIENTED_EDGE('',*,*,#2521,.F.);
#2533=EDGE_LOOP('',(#2528,#2530,#2531,#2532));
#2534=FACE_BOUND('',#2533,.T.);
#2535=ADVANCED_FACE('F866',(#2534),#2495,.T.);
#2536=CARTESIAN_POINT('',(3.1,-11.7643956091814,-1.61697895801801));
#2537=DIRECTION('',(0.,-0.99068594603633,-0.136166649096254));
#2538=DIRECTION('',(0.,0.136166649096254,-0.99068594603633));
#2539=AXIS2_PLACEMENT_3D('',#2536,#2537,#2538);
#2540=PLANE('',#2539);
#2541=ORIENTED_EDGE('',*,*,#484,.F.);
#2542=ORIENTED_EDGE('',*,*,#2510,.F.);
#2543=ORIENTED_EDGE('',*,*,#1294,.F.);
#2544=ORIENTED_EDGE('',*,*,#2529,.F.);
#2545=EDGE_LOOP('',(#2541,#2542,#2543,#2544));
#2546=FACE_BOUND('',#2545,.T.);
#2547=ADVANCED_FACE('F870',(#2546),#2540,.F.);
#2548=CARTESIAN_POINT('',(1.5,-15.1763068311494,-6.59200030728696));
#2549=DIRECTION('',(0.,-0.91721130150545,-0.398401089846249));
#2550=DIRECTION('',(0.,0.398401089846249,-0.91721130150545));
#2551=AXIS2_PLACEMENT_3D('',#2548,#2549,#2550);
#2552=CYLINDRICAL_SURFACE('',#2551,1.6);
#2553=ORIENTED_EDGE('',*,*,#512,.F.);
#2554=CARTESIAN_POINT('',(1.5,-14.3314265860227,-6.22501702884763));
#2555=DIRECTION('',(0.,-0.91721130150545,-0.398401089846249));
#2556=DIRECTION('',(0.,0.398401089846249,-0.91721130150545));
#2557=AXIS2_PLACEMENT_3D('',#2554,#2555,#2556);
#2558=CIRCLE('',#2557,1.6);
#2559=EDGE_CURVE('E1506',#1305,#503,#2558,.T.);
#2560=ORIENTED_EDGE('',*,*,#2559,.F.);
#2561=ORIENTED_EDGE('',*,*,#1306,.F.);
#2562=CARTESIAN_POINT('',(1.5,-10.8918842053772,-4.7310129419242));
#2563=DIRECTION('',(0.,-0.91721130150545,-0.398401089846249));
#2564=DIRECTION('',(0.,0.398401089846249,-0.91721130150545));
#2565=AXIS2_PLACEMENT_3D('',#2562,#2563,#2564);
#2566=CIRCLE('',#2565,1.6);
#2567=EDGE_CURVE('E1502',#1303,#511,#2566,.T.);
#2568=ORIENTED_EDGE('',*,*,#2567,.T.);
#2569=EDGE_LOOP('',(#2553,#2560,#2561,#2568));
#2570=FACE_BOUND('',#2569,.T.);
#2571=ADVANCED_FACE('F874',(#2570),#2552,.T.);
#2572=CARTESIAN_POINT('',(1.5,-14.3314265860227,-6.22501702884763));
#2573=DIRECTION('',(0.,0.91721130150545,0.398401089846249));
#2574=DIRECTION('',(0.,-0.398401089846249,0.91721130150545));
#2575=AXIS2_PLACEMENT_3D('',#2572,#2573,#2574);
#2576=PLANE('',#2575);
#2577=ORIENTED_EDGE('',*,*,#504,.F.);
#2578=EDGE_CURVE('E1503',#495,#1313,#2558,.T.);
#2579=ORIENTED_EDGE('',*,*,#2578,.T.);
#2580=ORIENTED_EDGE('',*,*,#1314,.F.);
#2581=ORIENTED_EDGE('',*,*,#2559,.T.);
#2582=EDGE_LOOP('',(#2577,#2579,#2580,#2581));
#2583=FACE_BOUND('',#2582,.T.);
#2584=ADVANCED_FACE('F876',(#2583),#2576,.F.);
#2585=ORIENTED_EDGE('',*,*,#496,.F.);
#2586=EDGE_CURVE('E1499',#493,#1321,#2566,.T.);
#2587=ORIENTED_EDGE('',*,*,#2586,.T.);
#2588=ORIENTED_EDGE('',*,*,#1322,.F.);
#2589=ORIENTED_EDGE('',*,*,#2578,.F.);
#2590=EDGE_LOOP('',(#2585,#2587,#2588,#2589));
#2591=FACE_BOUND('',#2590,.T.);
#2592=ADVANCED_FACE('F879',(#2591),#2552,.T.);
#2593=CARTESIAN_POINT('',(3.1,-10.8918842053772,-4.7310129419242));
#2594=DIRECTION('',(0.,-0.91721130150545,-0.398401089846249));
#2595=DIRECTION('',(0.,0.398401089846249,-0.91721130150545));
#2596=AXIS2_PLACEMENT_3D('',#2593,#2594,#2595);
#2597=PLANE('',#2596);
#2598=ORIENTED_EDGE('',*,*,#518,.F.);
#2599=ORIENTED_EDGE('',*,*,#2567,.F.);
#2600=ORIENTED_EDGE('',*,*,#1328,.F.);
#2601=ORIENTED_EDGE('',*,*,#2586,.F.);
#2602=EDGE_LOOP('',(#2598,#2599,#2600,#2601));
#2603=FACE_BOUND('',#2602,.T.);
#2604=ADVANCED_FACE('F883',(#2603),#2597,.F.);
#2605=CARTESIAN_POINT('',(1.5,-12.8350278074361,-10.442069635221));
#2606=DIRECTION('',(0.,-0.775711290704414,-0.631087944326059));
#2607=DIRECTION('',(0.,0.631087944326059,-0.775711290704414));
#2608=AXIS2_PLACEMENT_3D('',#2605,#2606,#2607);
#2609=CYLINDRICAL_SURFACE('',#2608,1.6);
#2610=ORIENTED_EDGE('',*,*,#546,.F.);
#2611=CARTESIAN_POINT('',(1.5,-12.1204889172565,-9.86074913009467));
#2612=DIRECTION('',(0.,-0.775711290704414,-0.631087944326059));
#2613=DIRECTION('',(0.,0.631087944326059,-0.775711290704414));
#2614=AXIS2_PLACEMENT_3D('',#2611,#2612,#2613);
#2615=CIRCLE('',#2614,1.6);
#2616=EDGE_CURVE('E1486',#1339,#537,#2615,.T.);
#2617=ORIENTED_EDGE('',*,*,#2616,.F.);
#2618=ORIENTED_EDGE('',*,*,#1340,.F.);
#2619=CARTESIAN_POINT('',(1.5,-9.21157157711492,-7.49416933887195));
#2620=DIRECTION('',(0.,-0.775711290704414,-0.631087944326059));
#2621=DIRECTION('',(0.,0.631087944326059,-0.775711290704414));
#2622=AXIS2_PLACEMENT_3D('',#2619,#2620,#2621);
#2623=CIRCLE('',#2622,1.6);
#2624=EDGE_CURVE('E1482',#1337,#545,#2623,.T.);
#2625=ORIENTED_EDGE('',*,*,#2624,.T.);
#2626=EDGE_LOOP('',(#2610,#2617,#2618,#2625));
#2627=FACE_BOUND('',#2626,.T.);
#2628=ADVANCED_FACE('F887',(#2627),#2609,.T.);
#2629=CARTESIAN_POINT('',(1.5,-12.1204889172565,-9.86074913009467));
#2630=DIRECTION('',(0.,0.775711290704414,0.631087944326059));
#2631=DIRECTION('',(0.,-0.631087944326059,0.775711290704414));
#2632=AXIS2_PLACEMENT_3D('',#2629,#2630,#2631);
#2633=PLANE('',#2632);
#2634=ORIENTED_EDGE('',*,*,#538,.F.);
#2635=EDGE_CURVE('E1483',#529,#1347,#2615,.T.);
#2636=ORIENTED_EDGE('',*,*,#2635,.T.);
#2637=ORIENTED_EDGE('',*,*,#1348,.F.);
#2638=ORIENTED_EDGE('',*,*,#2616,.T.);
#2639=EDGE_LOOP('',(#2634,#2636,#2637,#2638));
#2640=FACE_BOUND('',#2639,.T.);
#2641=ADVANCED_FACE('F889',(#2640),#2633,.F.);
#2642=ORIENTED_EDGE('',*,*,#530,.F.);
#2643=EDGE_CURVE('E1479',#527,#1355,#2623,.T.);
#2644=ORIENTED_EDGE('',*,*,#2643,.T.);
#2645=ORIENTED_EDGE('',*,*,#1356,.F.);
#2646=ORIENTED_EDGE('',*,*,#2635,.F.);
#2647=EDGE_LOOP('',(#2642,#2644,#2645,#2646));
#2648=FACE_BOUND('',#2647,.T.);
#2649=ADVANCED_FACE('F892',(#2648),#2609,.T.);
#2650=CARTESIAN_POINT('',(3.1,-9.21157157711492,-7.49416933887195));
#2651=DIRECTION('',(0.,-0.775711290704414,-0.631087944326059));
#2652=DIRECTION('',(0.,0.631087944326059,-0.775711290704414));
#2653=AXIS2_PLACEMENT_3D('',#2650,#2651,#2652);
#2654=PLANE('',#2653);
#2655=ORIENTED_EDGE('',*,*,#552,.F.);
#2656=ORIENTED_EDGE('',*,*,#2624,.F.);
#2657=ORIENTED_EDGE('',*,*,#1362,.F.);
#2658=ORIENTED_EDGE('',*,*,#2643,.F.);
#2659=EDGE_LOOP('',(#2655,#2656,#2657,#2658));
#2660=FACE_BOUND('',#2659,.T.);
#2661=ADVANCED_FACE('F896',(#2660),#2654,.F.);
#2662=CARTESIAN_POINT('',(1.5,-9.54183348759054,-13.5176984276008));
#2663=DIRECTION('',(0.,-0.57668032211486,-0.816969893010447));
#2664=DIRECTION('',(0.,0.816969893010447,-0.57668032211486));
#2665=AXIS2_PLACEMENT_3D('',#2662,#2663,#2664);
#2666=CYLINDRICAL_SURFACE('',#2665,1.6);
#2667=ORIENTED_EDGE('',*,*,#580,.F.);
#2668=CARTESIAN_POINT('',(1.5,-9.01063003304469,-12.7651545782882));
#2669=DIRECTION('',(0.,-0.57668032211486,-0.816969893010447));
#2670=DIRECTION('',(0.,0.816969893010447,-0.57668032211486));
#2671=AXIS2_PLACEMENT_3D('',#2668,#2669,#2670);
#2672=CIRCLE('',#2671,1.6);
#2673=EDGE_CURVE('E1466',#1373,#571,#2672,.T.);
#2674=ORIENTED_EDGE('',*,*,#2673,.F.);
#2675=ORIENTED_EDGE('',*,*,#1374,.F.);
#2676=CARTESIAN_POINT('',(1.5,-6.84807882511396,-9.70151747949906));
#2677=DIRECTION('',(0.,-0.57668032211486,-0.816969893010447));
#2678=DIRECTION('',(0.,0.816969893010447,-0.57668032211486));
#2679=AXIS2_PLACEMENT_3D('',#2676,#2677,#2678);
#2680=CIRCLE('',#2679,1.6);
#2681=EDGE_CURVE('E1462',#1371,#579,#2680,.T.);
#2682=ORIENTED_EDGE('',*,*,#2681,.T.);
#2683=EDGE_LOOP('',(#2667,#2674,#2675,#2682));
#2684=FACE_BOUND('',#2683,.T.);
#2685=ADVANCED_FACE('F900',(#2684),#2666,.T.);
#2686=CARTESIAN_POINT('',(1.5,-9.01063003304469,-12.7651545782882));
#2687=DIRECTION('',(0.,0.57668032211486,0.816969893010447));
#2688=DIRECTION('',(0.,-0.816969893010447,0.57668032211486));
#2689=AXIS2_PLACEMENT_3D('',#2686,#2687,#2688);
#2690=PLANE('',#2689);
#2691=ORIENTED_EDGE('',*,*,#572,.F.);
#2692=EDGE_CURVE('E1463',#563,#1381,#2672,.T.);
#2693=ORIENTED_EDGE('',*,*,#2692,.T.);
#2694=ORIENTED_EDGE('',*,*,#1382,.F.);
#2695=ORIENTED_EDGE('',*,*,#2673,.T.);
#2696=EDGE_LOOP('',(#2691,#2693,#2694,#2695));
#2697=FACE_BOUND('',#2696,.T.);
#2698=ADVANCED_FACE('F902',(#2697),#2690,.F.);
#2699=ORIENTED_EDGE('',*,*,#564,.F.);
#2700=EDGE_CURVE('E1459',#561,#1389,#2680,.T.);
#2701=ORIENTED_EDGE('',*,*,#2700,.T.);
#2702=ORIENTED_EDGE('',*,*,#1390,.F.);
#2703=ORIENTED_EDGE('',*,*,#2692,.F.);
#2704=EDGE_LOOP('',(#2699,#2701,#2702,#2703));
#2705=FACE_BOUND('',#2704,.T.);
#2706=ADVANCED_FACE('F905',(#2705),#2666,.T.);
#2707=CARTESIAN_POINT('',(3.1,-6.84807882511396,-9.70151747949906));
#2708=DIRECTION('',(0.,-0.57668032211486,-0.816969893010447));
#2709=DIRECTION('',(0.,0.816969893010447,-0.57668032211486));
#2710=AXIS2_PLACEMENT_3D('',#2707,#2708,#2709);
#2711=PLANE('',#2710);
#2712=ORIENTED_EDGE('',*,*,#586,.F.);
#2713=ORIENTED_EDGE('',*,*,#2681,.F.);
#2714=ORIENTED_EDGE('',*,*,#1396,.F.);
#2715=ORIENTED_EDGE('',*,*,#2700,.F.);
#2716=EDGE_LOOP('',(#2712,#2713,#2714,#2715));
#2717=FACE_BOUND('',#2716,.T.);
#2718=ADVANCED_FACE('F909',(#2717),#2711,.F.);
#2719=CARTESIAN_POINT('',(1.5,-5.54096502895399,-15.5907813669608));
#2720=DIRECTION('',(0.,-0.334879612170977,-0.942260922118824));
#2721=DIRECTION('',(0.,0.942260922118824,-0.334879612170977));
#2722=AXIS2_PLACEMENT_3D('',#2719,#2720,#2721);
#2723=CYLINDRICAL_SURFACE('',#2722,1.6);
#2724=ORIENTED_EDGE('',*,*,#614,.F.);
#2725=CARTESIAN_POINT('',(1.5,-5.23249394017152,-14.7228269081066));
#2726=DIRECTION('',(0.,-0.334879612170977,-0.942260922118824));
#2727=DIRECTION('',(0.,0.942260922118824,-0.334879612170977));
#2728=AXIS2_PLACEMENT_3D('',#2725,#2726,#2727);
#2729=CIRCLE('',#2728,1.6);
#2730=EDGE_CURVE('E1446',#1407,#605,#2729,.T.);
#2731=ORIENTED_EDGE('',*,*,#2730,.F.);
#2732=ORIENTED_EDGE('',*,*,#1408,.F.);
#2733=CARTESIAN_POINT('',(1.5,-3.97669539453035,-11.189348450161));
#2734=DIRECTION('',(0.,-0.334879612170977,-0.942260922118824));
#2735=DIRECTION('',(0.,0.942260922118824,-0.334879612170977));
#2736=AXIS2_PLACEMENT_3D('',#2733,#2734,#2735);
#2737=CIRCLE('',#2736,1.6);
#2738=EDGE_CURVE('E1442',#1405,#613,#2737,.T.);
#2739=ORIENTED_EDGE('',*,*,#2738,.T.);
#2740=EDGE_LOOP('',(#2724,#2731,#2732,#2739));
#2741=FACE_BOUND('',#2740,.T.);
#2742=ADVANCED_FACE('F913',(#2741),#2723,.T.);
#2743=CARTESIAN_POINT('',(1.5,-5.23249394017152,-14.7228269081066));
#2744=DIRECTION('',(0.,0.334879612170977,0.942260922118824));
#2745=DIRECTION('',(0.,-0.942260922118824,0.334879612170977));
#2746=AXIS2_PLACEMENT_3D('',#2743,#2744,#2745);
#2747=PLANE('',#2746);
#2748=ORIENTED_EDGE('',*,*,#606,.F.);
#2749=EDGE_CURVE('E1443',#597,#1415,#2729,.T.);
#2750=ORIENTED_EDGE('',*,*,#2749,.T.);
#2751=ORIENTED_EDGE('',*,*,#1416,.F.);
#2752=ORIENTED_EDGE('',*,*,#2730,.T.);
#2753=EDGE_LOOP('',(#2748,#2750,#2751,#2752));
#2754=FACE_BOUND('',#2753,.T.);
#2755=ADVANCED_FACE('F915',(#2754),#2747,.F.);
#2756=ORIENTED_EDGE('',*,*,#598,.F.);
#2757=EDGE_CURVE('E1439',#595,#1423,#2737,.T.);
#2758=ORIENTED_EDGE('',*,*,#2757,.T.);
#2759=ORIENTED_EDGE('',*,*,#1424,.F.);
#2760=ORIENTED_EDGE('',*,*,#2749,.F.);
#2761=EDGE_LOOP('',(#2756,#2758,#2759,#2760));
#2762=FACE_BOUND('',#2761,.T.);
#2763=ADVANCED_FACE('F918',(#2762),#2723,.T.);
#2764=CARTESIAN_POINT('',(3.1,-3.97669539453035,-11.189348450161));
#2765=DIRECTION('',(0.,-0.334879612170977,-0.942260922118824));
#2766=DIRECTION('',(0.,0.942260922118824,-0.334879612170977));
#2767=AXIS2_PLACEMENT_3D('',#2764,#2765,#2766);
#2768=PLANE('',#2767);
#2769=ORIENTED_EDGE('',*,*,#620,.F.);
#2770=ORIENTED_EDGE('',*,*,#2738,.F.);
#2771=ORIENTED_EDGE('',*,*,#1430,.F.);
#2772=ORIENTED_EDGE('',*,*,#2757,.F.);
#2773=EDGE_LOOP('',(#2769,#2770,#2771,#2772));
#2774=FACE_BOUND('',#2773,.T.);
#2775=ADVANCED_FACE('F922',(#2774),#2768,.F.);
#2776=CARTESIAN_POINT('',(1.5,-1.12914854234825,-16.5075673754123));
#2777=DIRECTION('',(0.,-0.0682424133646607,-0.99766876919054));
#2778=DIRECTION('',(0.,0.99766876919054,-0.0682424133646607));
#2779=AXIS2_PLACEMENT_3D('',#2776,#2777,#2778);
#2780=CYLINDRICAL_SURFACE('',#2779,1.6);
#2781=ORIENTED_EDGE('',*,*,#648,.F.);
#2782=CARTESIAN_POINT('',(1.5,-1.06628770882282,-15.5885745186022));
#2783=DIRECTION('',(0.,-0.0682424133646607,-0.99766876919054));
#2784=DIRECTION('',(0.,0.99766876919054,-0.0682424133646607));
#2785=AXIS2_PLACEMENT_3D('',#2782,#2783,#2784);
#2786=CIRCLE('',#2785,1.6);
#2787=EDGE_CURVE('E1426',#1441,#639,#2786,.T.);
#2788=ORIENTED_EDGE('',*,*,#2787,.F.);
#2789=ORIENTED_EDGE('',*,*,#1442,.F.);
#2790=CARTESIAN_POINT('',(1.5,-0.810378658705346,-11.8473166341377));
#2791=DIRECTION('',(0.,-0.0682424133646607,-0.99766876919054));
#2792=DIRECTION('',(0.,0.99766876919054,-0.0682424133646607));
#2793=AXIS2_PLACEMENT_3D('',#2790,#2791,#2792);
#2794=CIRCLE('',#2793,1.6);
#2795=EDGE_CURVE('E1422',#1439,#647,#2794,.T.);
#2796=ORIENTED_EDGE('',*,*,#2795,.T.);
#2797=EDGE_LOOP('',(#2781,#2788,#2789,#2796));
#2798=FACE_BOUND('',#2797,.T.);
#2799=ADVANCED_FACE('F926',(#2798),#2780,.T.);
#2800=CARTESIAN_POINT('',(1.5,-1.06628770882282,-15.5885745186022));
#2801=DIRECTION('',(0.,0.0682424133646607,0.99766876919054));
#2802=DIRECTION('',(0.,-0.99766876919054,0.0682424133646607));
#2803=AXIS2_PLACEMENT_3D('',#2800,#2801,#2802);
#2804=PLANE('',#2803);
#2805=ORIENTED_EDGE('',*,*,#640,.F.);
#2806=EDGE_CURVE('E1423',#631,#1449,#2786,.T.);
#2807=ORIENTED_EDGE('',*,*,#2806,.T.);
#2808=ORIENTED_EDGE('',*,*,#1450,.F.);
#2809=ORIENTED_EDGE('',*,*,#2787,.T.);
#2810=EDGE_LOOP('',(#2805,#2807,#2808,#2809));
#2811=FACE_BOUND('',#2810,.T.);
#2812=ADVANCED_FACE('F928',(#2811),#2804,.F.);
#2813=ORIENTED_EDGE('',*,*,#632,.F.);
#2814=EDGE_CURVE('E1419',#629,#1457,#2794,.T.);
#2815=ORIENTED_EDGE('',*,*,#2814,.T.);
#2816=ORIENTED_EDGE('',*,*,#1458,.F.);
#2817=ORIENTED_EDGE('',*,*,#2806,.F.);
#2818=EDGE_LOOP('',(#2813,#2815,#2816,#2817));
#2819=FACE_BOUND('',#2818,.T.);
#2820=ADVANCED_FACE('F931',(#2819),#2780,.T.);
#2821=CARTESIAN_POINT('',(3.1,-0.810378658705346,-11.8473166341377));
#2822=DIRECTION('',(0.,-0.0682424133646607,-0.99766876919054));
#2823=DIRECTION('',(0.,0.99766876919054,-0.0682424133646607));
#2824=AXIS2_PLACEMENT_3D('',#2821,#2822,#2823);
#2825=PLANE('',#2824);
#2826=ORIENTED_EDGE('',*,*,#654,.F.);
#2827=ORIENTED_EDGE('',*,*,#2795,.F.);
#2828=ORIENTED_EDGE('',*,*,#1464,.F.);
#2829=ORIENTED_EDGE('',*,*,#2814,.F.);
#2830=EDGE_LOOP('',(#2826,#2827,#2828,#2829));
#2831=FACE_BOUND('',#2830,.T.);
#2832=ADVANCED_FACE('F935',(#2831),#2825,.F.);
#2833=CARTESIAN_POINT('',(1.5,3.36641172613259,-16.2000626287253));
#2834=DIRECTION('',(0.,0.203456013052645,-0.979084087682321));
#2835=DIRECTION('',(0.,0.979084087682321,0.203456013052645));
#2836=AXIS2_PLACEMENT_3D('',#2833,#2834,#2835);
#2837=CYLINDRICAL_SURFACE('',#2836,1.6);
#2838=ORIENTED_EDGE('',*,*,#682,.F.);
#2839=CARTESIAN_POINT('',(1.5,3.17900020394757,-15.2981888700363));
#2840=DIRECTION('',(0.,0.203456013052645,-0.979084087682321));
#2841=DIRECTION('',(0.,0.979084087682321,0.203456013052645));
#2842=AXIS2_PLACEMENT_3D('',#2839,#2840,#2841);
#2843=CIRCLE('',#2842,1.6);
#2844=EDGE_CURVE('E1406',#1475,#673,#2843,.T.);
#2845=ORIENTED_EDGE('',*,*,#2844,.F.);
#2846=ORIENTED_EDGE('',*,*,#1476,.F.);
#2847=CARTESIAN_POINT('',(1.5,2.41604015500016,-11.6266235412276));
#2848=DIRECTION('',(0.,0.203456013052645,-0.979084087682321));
#2849=DIRECTION('',(0.,0.979084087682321,0.203456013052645));
#2850=AXIS2_PLACEMENT_3D('',#2847,#2848,#2849);
#2851=CIRCLE('',#2850,1.6);
#2852=EDGE_CURVE('E1402',#1473,#681,#2851,.T.);
#2853=ORIENTED_EDGE('',*,*,#2852,.T.);
#2854=EDGE_LOOP('',(#2838,#2845,#2846,#2853));
#2855=FACE_BOUND('',#2854,.T.);
#2856=ADVANCED_FACE('F939',(#2855),#2837,.T.);
#2857=CARTESIAN_POINT('',(1.5,3.17900020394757,-15.2981888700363));
#2858=DIRECTION('',(0.,-0.203456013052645,0.979084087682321));
#2859=DIRECTION('',(0.,-0.979084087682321,-0.203456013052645));
#2860=AXIS2_PLACEMENT_3D('',#2857,#2858,#2859);
#2861=PLANE('',#2860);
#2862=ORIENTED_EDGE('',*,*,#674,.F.);
#2863=EDGE_CURVE('E1403',#665,#1483,#2843,.T.);
#2864=ORIENTED_EDGE('',*,*,#2863,.T.);
#2865=ORIENTED_EDGE('',*,*,#1484,.F.);
#2866=ORIENTED_EDGE('',*,*,#2844,.T.);
#2867=EDGE_LOOP('',(#2862,#2864,#2865,#2866));
#2868=FACE_BOUND('',#2867,.T.);
#2869=ADVANCED_FACE('F941',(#2868),#2861,.F.);
#2870=ORIENTED_EDGE('',*,*,#666,.F.);
#2871=EDGE_CURVE('E1399',#663,#1491,#2851,.T.);
#2872=ORIENTED_EDGE('',*,*,#2871,.T.);
#2873=ORIENTED_EDGE('',*,*,#1492,.F.);
#2874=ORIENTED_EDGE('',*,*,#2863,.F.);
#2875=EDGE_LOOP('',(#2870,#2872,#2873,#2874));
#2876=FACE_BOUND('',#2875,.T.);
#2877=ADVANCED_FACE('F944',(#2876),#2837,.T.);
#2878=CARTESIAN_POINT('',(3.1,2.41604015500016,-11.6266235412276));
#2879=DIRECTION('',(0.,0.203456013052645,-0.979084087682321));
#2880=DIRECTION('',(0.,0.979084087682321,0.203456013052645));
#2881=AXIS2_PLACEMENT_3D('',#2878,#2879,#2880);
#2882=PLANE('',#2881);
#2883=ORIENTED_EDGE('',*,*,#688,.F.);
#2884=ORIENTED_EDGE('',*,*,#2852,.F.);
#2885=ORIENTED_EDGE('',*,*,#1498,.F.);
#2886=ORIENTED_EDGE('',*,*,#2871,.F.);
#2887=EDGE_LOOP('',(#2883,#2884,#2885,#2886));
#2888=FACE_BOUND('',#2887,.T.);
#2889=ADVANCED_FACE('F948',(#2888),#2882,.F.);
#2890=CARTESIAN_POINT('',(1.5,7.61230063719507,-14.6910733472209));
#2891=DIRECTION('',(0.,0.460065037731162,-0.88788521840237));
#2892=DIRECTION('',(0.,0.88788521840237,0.460065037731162));
#2893=AXIS2_PLACEMENT_3D('',#2890,#2891,#2892);
#2894=CYLINDRICAL_SURFACE('',#2893,1.6);
#2895=ORIENTED_EDGE('',*,*,#716,.F.);
#2896=CARTESIAN_POINT('',(1.5,7.1885162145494,-13.873206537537));
#2897=DIRECTION('',(0.,0.460065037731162,-0.88788521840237));
#2898=DIRECTION('',(0.,0.88788521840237,0.460065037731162));
#2899=AXIS2_PLACEMENT_3D('',#2896,#2897,#2898);
#2900=CIRCLE('',#2899,1.6);
#2901=EDGE_CURVE('E1386',#1509,#707,#2900,.T.);
#2902=ORIENTED_EDGE('',*,*,#2901,.F.);
#2903=ORIENTED_EDGE('',*,*,#1510,.F.);
#2904=CARTESIAN_POINT('',(1.5,5.46327232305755,-10.5436369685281));
#2905=DIRECTION('',(0.,0.460065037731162,-0.88788521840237));
#2906=DIRECTION('',(0.,0.88788521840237,0.460065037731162));
#2907=AXIS2_PLACEMENT_3D('',#2904,#2905,#2906);
#2908=CIRCLE('',#2907,1.6);
#2909=EDGE_CURVE('E1382',#1507,#715,#2908,.T.);
#2910=ORIENTED_EDGE('',*,*,#2909,.T.);
#2911=EDGE_LOOP('',(#2895,#2902,#2903,#2910));
#2912=FACE_BOUND('',#2911,.T.);
#2913=ADVANCED_FACE('F952',(#2912),#2894,.T.);
#2914=CARTESIAN_POINT('',(1.5,7.1885162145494,-13.873206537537));
#2915=DIRECTION('',(0.,-0.460065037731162,0.88788521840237));
#2916=DIRECTION('',(0.,-0.88788521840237,-0.460065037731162));
#2917=AXIS2_PLACEMENT_3D('',#2914,#2915,#2916);
#2918=PLANE('',#2917);
#2919=ORIENTED_EDGE('',*,*,#708,.F.);
#2920=EDGE_CURVE('E1383',#699,#1517,#2900,.T.);
#2921=ORIENTED_EDGE('',*,*,#2920,.T.);
#2922=ORIENTED_EDGE('',*,*,#1518,.F.);
#2923=ORIENTED_EDGE('',*,*,#2901,.T.);
#2924=EDGE_LOOP('',(#2919,#2921,#2922,#2923));
#2925=FACE_BOUND('',#2924,.T.);
#2926=ADVANCED_FACE('F954',(#2925),#2918,.F.);
#2927=ORIENTED_EDGE('',*,*,#700,.F.);
#2928=EDGE_CURVE('E1379',#697,#1525,#2908,.T.);
#2929=ORIENTED_EDGE('',*,*,#2928,.T.);
#2930=ORIENTED_EDGE('',*,*,#1526,.F.);
#2931=ORIENTED_EDGE('',*,*,#2920,.F.);
#2932=EDGE_LOOP('',(#2927,#2929,#2930,#2931));
#2933=FACE_BOUND('',#2932,.T.);
#2934=ADVANCED_FACE('F957',(#2933),#2894,.T.);
#2935=CARTESIAN_POINT('',(3.1,5.46327232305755,-10.5436369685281));
#2936=DIRECTION('',(0.,0.460065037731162,-0.88788521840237));
#2937=DIRECTION('',(0.,0.88788521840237,0.460065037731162));
#2938=AXIS2_PLACEMENT_3D('',#2935,#2936,#2937);
#2939=PLANE('',#2938);
#2940=ORIENTED_EDGE('',*,*,#722,.F.);
#2941=ORIENTED_EDGE('',*,*,#2909,.F.);
#2942=ORIENTED_EDGE('',*,*,#1532,.F.);
#2943=ORIENTED_EDGE('',*,*,#2928,.F.);
#2944=EDGE_LOOP('',(#2940,#2941,#2942,#2943));
#2945=FACE_BOUND('',#2944,.T.);
#2946=ADVANCED_FACE('F961',(#2945),#2939,.F.);
#2947=CARTESIAN_POINT('',(1.5,11.293620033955,-12.0925143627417));
#2948=DIRECTION('',(0.,0.682553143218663,-0.730835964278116));
#2949=DIRECTION('',(0.,0.730835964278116,0.682553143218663));
#2950=AXIS2_PLACEMENT_3D('',#2947,#2948,#2949);
#2951=CYLINDRICAL_SURFACE('',#2950,1.6);
#2952=ORIENTED_EDGE('',*,*,#750,.F.);
#2953=CARTESIAN_POINT('',(1.5,10.6648928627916,-11.4193119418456));
#2954=DIRECTION('',(0.,0.682553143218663,-0.730835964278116));
#2955=DIRECTION('',(0.,0.730835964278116,0.682553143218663));
#2956=AXIS2_PLACEMENT_3D('',#2953,#2954,#2955);
#2957=CIRCLE('',#2956,1.6);
#2958=EDGE_CURVE('E1366',#1543,#741,#2957,.T.);
#2959=ORIENTED_EDGE('',*,*,#2958,.F.);
#2960=ORIENTED_EDGE('',*,*,#1544,.F.);
#2961=CARTESIAN_POINT('',(1.5,8.10531857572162,-8.67867707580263));
#2962=DIRECTION('',(0.,0.682553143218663,-0.730835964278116));
#2963=DIRECTION('',(0.,0.730835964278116,0.682553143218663));
#2964=AXIS2_PLACEMENT_3D('',#2961,#2962,#2963);
#2965=CIRCLE('',#2964,1.6);
#2966=EDGE_CURVE('E1362',#1541,#749,#2965,.T.);
#2967=ORIENTED_EDGE('',*,*,#2966,.T.);
#2968=EDGE_LOOP('',(#2952,#2959,#2960,#2967));
#2969=FACE_BOUND('',#2968,.T.);
#2970=ADVANCED_FACE('F965',(#2969),#2951,.T.);
#2971=CARTESIAN_POINT('',(1.5,10.6648928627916,-11.4193119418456));
#2972=DIRECTION('',(0.,-0.682553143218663,0.730835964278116));
#2973=DIRECTION('',(0.,-0.730835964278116,-0.682553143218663));
#2974=AXIS2_PLACEMENT_3D('',#2971,#2972,#2973);
#2975=PLANE('',#2974);
#2976=ORIENTED_EDGE('',*,*,#742,.F.);
#2977=EDGE_CURVE('E1363',#733,#1551,#2957,.T.);
#2978=ORIENTED_EDGE('',*,*,#2977,.T.);
#2979=ORIENTED_EDGE('',*,*,#1552,.F.);
#2980=ORIENTED_EDGE('',*,*,#2958,.T.);
#2981=EDGE_LOOP('',(#2976,#2978,#2979,#2980));
#2982=FACE_BOUND('',#2981,.T.);
#2983=ADVANCED_FACE('F967',(#2982),#2975,.F.);
#2984=ORIENTED_EDGE('',*,*,#734,.F.);
#2985=EDGE_CURVE('E1359',#731,#1559,#2965,.T.);
#2986=ORIENTED_EDGE('',*,*,#2985,.T.);
#2987=ORIENTED_EDGE('',*,*,#1560,.F.);
#2988=ORIENTED_EDGE('',*,*,#2977,.F.);
#2989=EDGE_LOOP('',(#2984,#2986,#2987,#2988));
#2990=FACE_BOUND('',#2989,.T.);
#2991=ADVANCED_FACE('F970',(#2990),#2951,.T.);
#2992=CARTESIAN_POINT('',(3.1,8.10531857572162,-8.67867707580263));
#2993=DIRECTION('',(0.,0.682553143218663,-0.730835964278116));
#2994=DIRECTION('',(0.,0.730835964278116,0.682553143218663));
#2995=AXIS2_PLACEMENT_3D('',#2992,#2993,#2994);
#2996=PLANE('',#2995);
#2997=ORIENTED_EDGE('',*,*,#756,.F.);
#2998=ORIENTED_EDGE('',*,*,#2966,.F.);
#2999=ORIENTED_EDGE('',*,*,#1566,.F.);
#3000=ORIENTED_EDGE('',*,*,#2985,.F.);
#3001=EDGE_LOOP('',(#2997,#2998,#2999,#3000));
#3002=FACE_BOUND('',#3001,.T.);
#3003=ADVANCED_FACE('F974',(#3002),#2996,.F.);
#3004=CARTESIAN_POINT('',(1.5,14.1373432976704,-8.59710890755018));
#3005=DIRECTION('',(0.,0.854419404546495,-0.519583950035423));
#3006=DIRECTION('',(0.,0.519583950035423,0.854419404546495));
#3007=AXIS2_PLACEMENT_3D('',#3004,#3005,#3006);
#3008=CYLINDRICAL_SURFACE('',#3007,1.6);
#3009=ORIENTED_EDGE('',*,*,#784,.F.);
#3010=CARTESIAN_POINT('',(1.5,13.350303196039,-8.11849921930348));
#3011=DIRECTION('',(0.,0.854419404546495,-0.519583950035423));
#3012=DIRECTION('',(0.,0.519583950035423,0.854419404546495));
#3013=AXIS2_PLACEMENT_3D('',#3010,#3011,#3012);
#3014=CIRCLE('',#3013,1.6);
#3015=EDGE_CURVE('E1336',#1577,#775,#3014,.T.);
#3016=ORIENTED_EDGE('',*,*,#3015,.F.);
#3017=ORIENTED_EDGE('',*,*,#1578,.F.);
#3018=CARTESIAN_POINT('',(1.5,10.1462304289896,-6.17005940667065));
#3019=DIRECTION('',(0.,0.854419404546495,-0.519583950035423));
#3020=DIRECTION('',(0.,0.519583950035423,0.854419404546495));
#3021=AXIS2_PLACEMENT_3D('',#3018,#3019,#3020);
#3022=CIRCLE('',#3021,1.6);
#3023=EDGE_CURVE('E1349',#1575,#783,#3022,.T.);
#3024=ORIENTED_EDGE('',*,*,#3023,.T.);
#3025=EDGE_LOOP('',(#3009,#3016,#3017,#3024));
#3026=FACE_BOUND('',#3025,.T.);
#3027=ADVANCED_FACE('F978',(#3026),#3008,.T.);
#3028=CARTESIAN_POINT('',(1.5,13.350303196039,-8.11849921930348));
#3029=DIRECTION('',(0.,-0.854419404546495,0.519583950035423));
#3030=DIRECTION('',(0.,-0.519583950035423,-0.854419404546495));
#3031=AXIS2_PLACEMENT_3D('',#3028,#3029,#3030);
#3032=PLANE('',#3031);
#3033=ORIENTED_EDGE('',*,*,#776,.F.);
#3034=EDGE_CURVE('E1339',#767,#1585,#3014,.T.);
#3035=ORIENTED_EDGE('',*,*,#3034,.T.);
#3036=ORIENTED_EDGE('',*,*,#1586,.F.);
#3037=ORIENTED_EDGE('',*,*,#3015,.T.);
#3038=EDGE_LOOP('',(#3033,#3035,#3036,#3037));
#3039=FACE_BOUND('',#3038,.T.);
#3040=ADVANCED_FACE('F980',(#3039),#3032,.F.);
#3041=ORIENTED_EDGE('',*,*,#768,.F.);
#3042=EDGE_CURVE('E1351',#765,#1593,#3022,.T.);
#3043=ORIENTED_EDGE('',*,*,#3042,.T.);
#3044=ORIENTED_EDGE('',*,*,#1594,.F.);
#3045=ORIENTED_EDGE('',*,*,#3034,.F.);
#3046=EDGE_LOOP('',(#3041,#3043,#3044,#3045));
#3047=FACE_BOUND('',#3046,.T.);
#3048=ADVANCED_FACE('F983',(#3047),#3008,.T.);
#3049=CARTESIAN_POINT('',(3.1,10.1462304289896,-6.17005940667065));
#3050=DIRECTION('',(0.,0.854419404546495,-0.519583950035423));
#3051=DIRECTION('',(0.,0.519583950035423,0.854419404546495));
#3052=AXIS2_PLACEMENT_3D('',#3049,#3050,#3051);
#3053=PLANE('',#3052);
#3054=ORIENTED_EDGE('',*,*,#790,.F.);
#3055=ORIENTED_EDGE('',*,*,#3023,.F.);
#3056=ORIENTED_EDGE('',*,*,#1600,.F.);
#3057=ORIENTED_EDGE('',*,*,#3042,.F.);
#3058=EDGE_LOOP('',(#3054,#3055,#3056,#3057));
#3059=FACE_BOUND('',#3058,.T.);
#3060=ADVANCED_FACE('F987',(#3059),#3053,.F.);
#3061=CARTESIAN_POINT('',(1.5,15.9325644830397,-4.46409521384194));
#3062=DIRECTION('',(0.,0.962917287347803,-0.269796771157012));
#3063=DIRECTION('',(0.,0.269796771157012,0.962917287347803));
#3064=AXIS2_PLACEMENT_3D('',#3061,#3062,#3063);
#3065=CYLINDRICAL_SURFACE('',#3064,1.6);
#3066=ORIENTED_EDGE('',*,*,#818,.F.);
#3067=CARTESIAN_POINT('',(1.5,15.0455826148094,-4.2155745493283));
#3068=DIRECTION('',(0.,0.962917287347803,-0.269796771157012));
#3069=DIRECTION('',(0.,0.269796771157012,0.962917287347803));
#3070=AXIS2_PLACEMENT_3D('',#3067,#3068,#3069);
#3071=CIRCLE('',#3070,1.6);
#3072=EDGE_CURVE('E1825',#1611,#809,#3071,.T.);
#3073=ORIENTED_EDGE('',*,*,#3072,.F.);
#3074=ORIENTED_EDGE('',*,*,#1612,.F.);
#3075=CARTESIAN_POINT('',(1.5,11.4346427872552,-3.20383665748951));
#3076=DIRECTION('',(0.,0.962917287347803,-0.269796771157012));
#3077=DIRECTION('',(0.,0.269796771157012,0.962917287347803));
#3078=AXIS2_PLACEMENT_3D('',#3075,#3076,#3077);
#3079=CIRCLE('',#3078,1.6);
#3080=EDGE_CURVE('E53',#1609,#817,#3079,.T.);
#3081=ORIENTED_EDGE('',*,*,#3080,.T.);
#3082=EDGE_LOOP('',(#3066,#3073,#3074,#3081));
#3083=FACE_BOUND('',#3082,.T.);
#3084=ADVANCED_FACE('F991',(#3083),#3065,.T.);
#3085=CARTESIAN_POINT('',(1.5,15.0455826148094,-4.2155745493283));
#3086=DIRECTION('',(0.,-0.962917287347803,0.269796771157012));
#3087=DIRECTION('',(0.,-0.269796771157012,-0.962917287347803));
#3088=AXIS2_PLACEMENT_3D('',#3085,#3086,#3087);
#3089=PLANE('',#3088);
#3090=ORIENTED_EDGE('',*,*,#810,.F.);
#3091=EDGE_CURVE('E1829',#801,#1619,#3071,.T.);
#3092=ORIENTED_EDGE('',*,*,#3091,.T.);
#3093=ORIENTED_EDGE('',*,*,#1620,.F.);
#3094=ORIENTED_EDGE('',*,*,#3072,.T.);
#3095=EDGE_LOOP('',(#3090,#3092,#3093,#3094));
#3096=FACE_BOUND('',#3095,.T.);
#3097=ADVANCED_FACE('F993',(#3096),#3089,.F.);
#3098=ORIENTED_EDGE('',*,*,#802,.F.);
#3099=EDGE_CURVE('E48',#799,#1627,#3079,.T.);
#3100=ORIENTED_EDGE('',*,*,#3099,.T.);
#3101=ORIENTED_EDGE('',*,*,#1628,.F.);
#3102=ORIENTED_EDGE('',*,*,#3091,.F.);
#3103=EDGE_LOOP('',(#3098,#3100,#3101,#3102));
#3104=FACE_BOUND('',#3103,.T.);
#3105=ADVANCED_FACE('F608',(#3104),#3065,.T.);
#3106=CARTESIAN_POINT('',(3.1,11.4346427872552,-3.20383665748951));
#3107=DIRECTION('',(0.,0.962917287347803,-0.269796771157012));
#3108=DIRECTION('',(0.,0.269796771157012,0.962917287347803));
#3109=AXIS2_PLACEMENT_3D('',#3106,#3107,#3108);
#3110=PLANE('',#3109);
#3111=ORIENTED_EDGE('',*,*,#824,.F.);
#3112=ORIENTED_EDGE('',*,*,#3080,.F.);
#3113=ORIENTED_EDGE('',*,*,#1634,.F.);
#3114=ORIENTED_EDGE('',*,*,#3099,.F.);
#3115=EDGE_LOOP('',(#3111,#3112,#3113,#3114));
#3116=FACE_BOUND('',#3115,.T.);
#3117=ADVANCED_FACE('F600',(#3116),#3110,.F.);
#3118=CARTESIAN_POINT('',(3.3,0.,0.));
#3119=DIRECTION('',(-1.,0.,0.));
#3120=DIRECTION('',(0.,-1.,0.));
#3121=AXIS2_PLACEMENT_3D('',#3118,#3119,#3120);
#3122=TOROIDAL_SURFACE('',#3121,10.8,0.3);
#3123=ORIENTED_EDGE('',*,*,#841,.F.);
#3124=EDGE_LOOP('',(#3123));
#3125=FACE_BOUND('',#3124,.T.);
#3126=ORIENTED_EDGE('',*,*,#1848,.F.);
#3127=EDGE_LOOP('',(#3126));
#3128=FACE_BOUND('',#3127,.T.);
#3129=ADVANCED_FACE('F1000',(#3125,#3128),#3122,.T.);
#3130=CARTESIAN_POINT('',(5.70000000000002,0.,0.));
#3131=DIRECTION('',(1.,0.,0.));
#3132=DIRECTION('',(0.,1.,0.));
#3133=AXIS2_PLACEMENT_3D('',#3130,#3131,#3132);
#3134=TOROIDAL_SURFACE('',#3133,10.8,0.3);
#3135=ORIENTED_EDGE('',*,*,#1859,.F.);
#3136=EDGE_LOOP('',(#3135));
#3137=FACE_BOUND('',#3136,.T.);
#3138=ORIENTED_EDGE('',*,*,#1820,.F.);
#3139=EDGE_LOOP('',(#3138));
#3140=FACE_BOUND('',#3139,.T.);
#3141=ADVANCED_FACE('F1004',(#3137,#3140),#3134,.T.);
#3142=CARTESIAN_POINT('',(-0.300000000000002,0.,0.));
#3143=DIRECTION('',(1.,0.,0.));
#3144=DIRECTION('',(0.,1.,0.));
#3145=AXIS2_PLACEMENT_3D('',#3142,#3143,#3144);
#3146=TOROIDAL_SURFACE('',#3145,10.3,0.3);
#3147=ORIENTED_EDGE('',*,*,#1731,.F.);
#3148=EDGE_LOOP('',(#3147));
#3149=FACE_BOUND('',#3148,.T.);
#3150=ORIENTED_EDGE('',*,*,#31,.F.);
#3151=EDGE_LOOP('',(#3150));
#3152=FACE_BOUND('',#3151,.T.);
#3153=ADVANCED_FACE('F1010',(#3149,#3152),#3146,.T.);
#3154=CARTESIAN_POINT('',(5.70000000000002,0.,0.));
#3155=DIRECTION('',(1.,0.,0.));
#3156=DIRECTION('',(0.,1.,0.));
#3157=AXIS2_PLACEMENT_3D('',#3154,#3155,#3156);
#3158=TOROIDAL_SURFACE('',#3157,17.2,0.3);
#3159=ORIENTED_EDGE('',*,*,#1831,.F.);
#3160=EDGE_LOOP('',(#3159));
#3161=FACE_BOUND('',#3160,.T.);
#3162=ORIENTED_EDGE('',*,*,#1792,.F.);
#3163=EDGE_LOOP('',(#3162));
#3164=FACE_BOUND('',#3163,.T.);
#3165=ADVANCED_FACE('F1019',(#3161,#3164),#3158,.T.);
#3166=CARTESIAN_POINT('',(3.3,0.,0.));
#3167=DIRECTION('',(-1.,0.,0.));
#3168=DIRECTION('',(0.,-1.,0.));
#3169=AXIS2_PLACEMENT_3D('',#3166,#3167,#3168);
#3170=TOROIDAL_SURFACE('',#3169,17.2,0.3);
#3171=ORIENTED_EDGE('',*,*,#1803,.F.);
#3172=EDGE_LOOP('',(#3171));
#3173=FACE_BOUND('',#3172,.T.);
#3174=ORIENTED_EDGE('',*,*,#852,.F.);
#3175=EDGE_LOOP('',(#3174));
#3176=FACE_BOUND('',#3175,.T.);
#3177=ADVANCED_FACE('F1023',(#3173,#3176),#3170,.T.);
#3178=CARTESIAN_POINT('',(-0.300000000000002,0.,0.));
#3179=DIRECTION('',(1.,0.,0.));
#3180=DIRECTION('',(0.,1.,0.));
#3181=AXIS2_PLACEMENT_3D('',#3178,#3179,#3180);
#3182=TOROIDAL_SURFACE('',#3181,17.2,0.3);
#3183=ORIENTED_EDGE('',*,*,#42,.F.);
#3184=EDGE_LOOP('',(#3183));
#3185=FACE_BOUND('',#3184,.T.);
#3186=ORIENTED_EDGE('',*,*,#1675,.F.);
#3187=EDGE_LOOP('',(#3186));
#3188=FACE_BOUND('',#3187,.T.);
#3189=ADVANCED_FACE('F1027',(#3185,#3188),#3182,.T.);
#3190=CARTESIAN_POINT('',(-2.7,0.,0.));
#3191=DIRECTION('',(-1.,0.,0.));
#3192=DIRECTION('',(0.,-1.,0.));
#3193=AXIS2_PLACEMENT_3D('',#3190,#3191,#3192);
#3194=TOROIDAL_SURFACE('',#3193,17.2,0.3);
#3195=ORIENTED_EDGE('',*,*,#1686,.F.);
#3196=EDGE_LOOP('',(#3195));
#3197=FACE_BOUND('',#3196,.T.);
#3198=ORIENTED_EDGE('',*,*,#1703,.F.);
#3199=EDGE_LOOP('',(#3198));
#3200=FACE_BOUND('',#3199,.T.);
#3201=ADVANCED_FACE('F671',(#3197,#3200),#3194,.T.);
#3202=CARTESIAN_POINT('',(-2.7,0.,0.));
#3203=DIRECTION('',(-1.,0.,0.));
#3204=DIRECTION('',(0.,-1.,0.));
#3205=AXIS2_PLACEMENT_3D('',#3202,#3203,#3204);
#3206=TOROIDAL_SURFACE('',#3205,10.3,0.3);
#3207=ORIENTED_EDGE('',*,*,#1714,.F.);
#3208=EDGE_LOOP('',(#3207));
#3209=FACE_BOUND('',#3208,.T.);
#3210=ORIENTED_EDGE('',*,*,#1742,.F.);
#3211=EDGE_LOOP('',(#3210));
#3212=FACE_BOUND('',#3211,.T.);
#3213=ADVANCED_FACE('F35',(#3209,#3212),#3206,.T.);
#3214=CLOSED_SHELL('',(#828,#1638,#1662,#1690,#1718,#1746,#1759,#1767,#1779,#1807,#1835,#1863,
#1887,#1900,#1908,#1920,#1944,#1957,#1965,#1977,#2001,#2014,#2022,#2034,#2058,#2071,#2079,#2091,
#2115,#2128,#2136,#2148,#2172,#2185,#2193,#2205,#2229,#2242,#2250,#2262,#2286,#2299,#2307,#2319,
#2343,#2356,#2364,#2376,#2400,#2413,#2421,#2433,#2457,#2470,#2478,#2490,#2514,#2527,#2535,#2547,
#2571,#2584,#2592,#2604,#2628,#2641,#2649,#2661,#2685,#2698,#2706,#2718,#2742,#2755,#2763,#2775,
#2799,#2812,#2820,#2832,#2856,#2869,#2877,#2889,#2913,#2926,#2934,#2946,#2970,#2983,#2991,#3003,
#3027,#3040,#3048,#3060,#3084,#3097,#3105,#3117,#3129,#3141,#3153,#3165,#3177,#3189,#3201,#3213));
#3215=MANIFOLD_SOLID_BREP('B2',#3214);
#3216=ADVANCED_BREP_SHAPE_REPRESENTATION('',(#18,#3215),#14);
#3217=SHAPE_DEFINITION_REPRESENTATION(#9,#3216);
ENDSEC;
END-ISO-10303-21;
